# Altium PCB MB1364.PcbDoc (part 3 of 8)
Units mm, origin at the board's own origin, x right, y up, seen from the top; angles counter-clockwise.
Board outline 70 x 133.34 mm, 6 copper layers (Top Layer, Signal Layer 1, Signal Layer 2, Signal Layer 3, Signal Layer 4, Bottom Layer), stack 1.57 mm thick; 321 components, 287 nets, 1372 pads, 2051 vias.

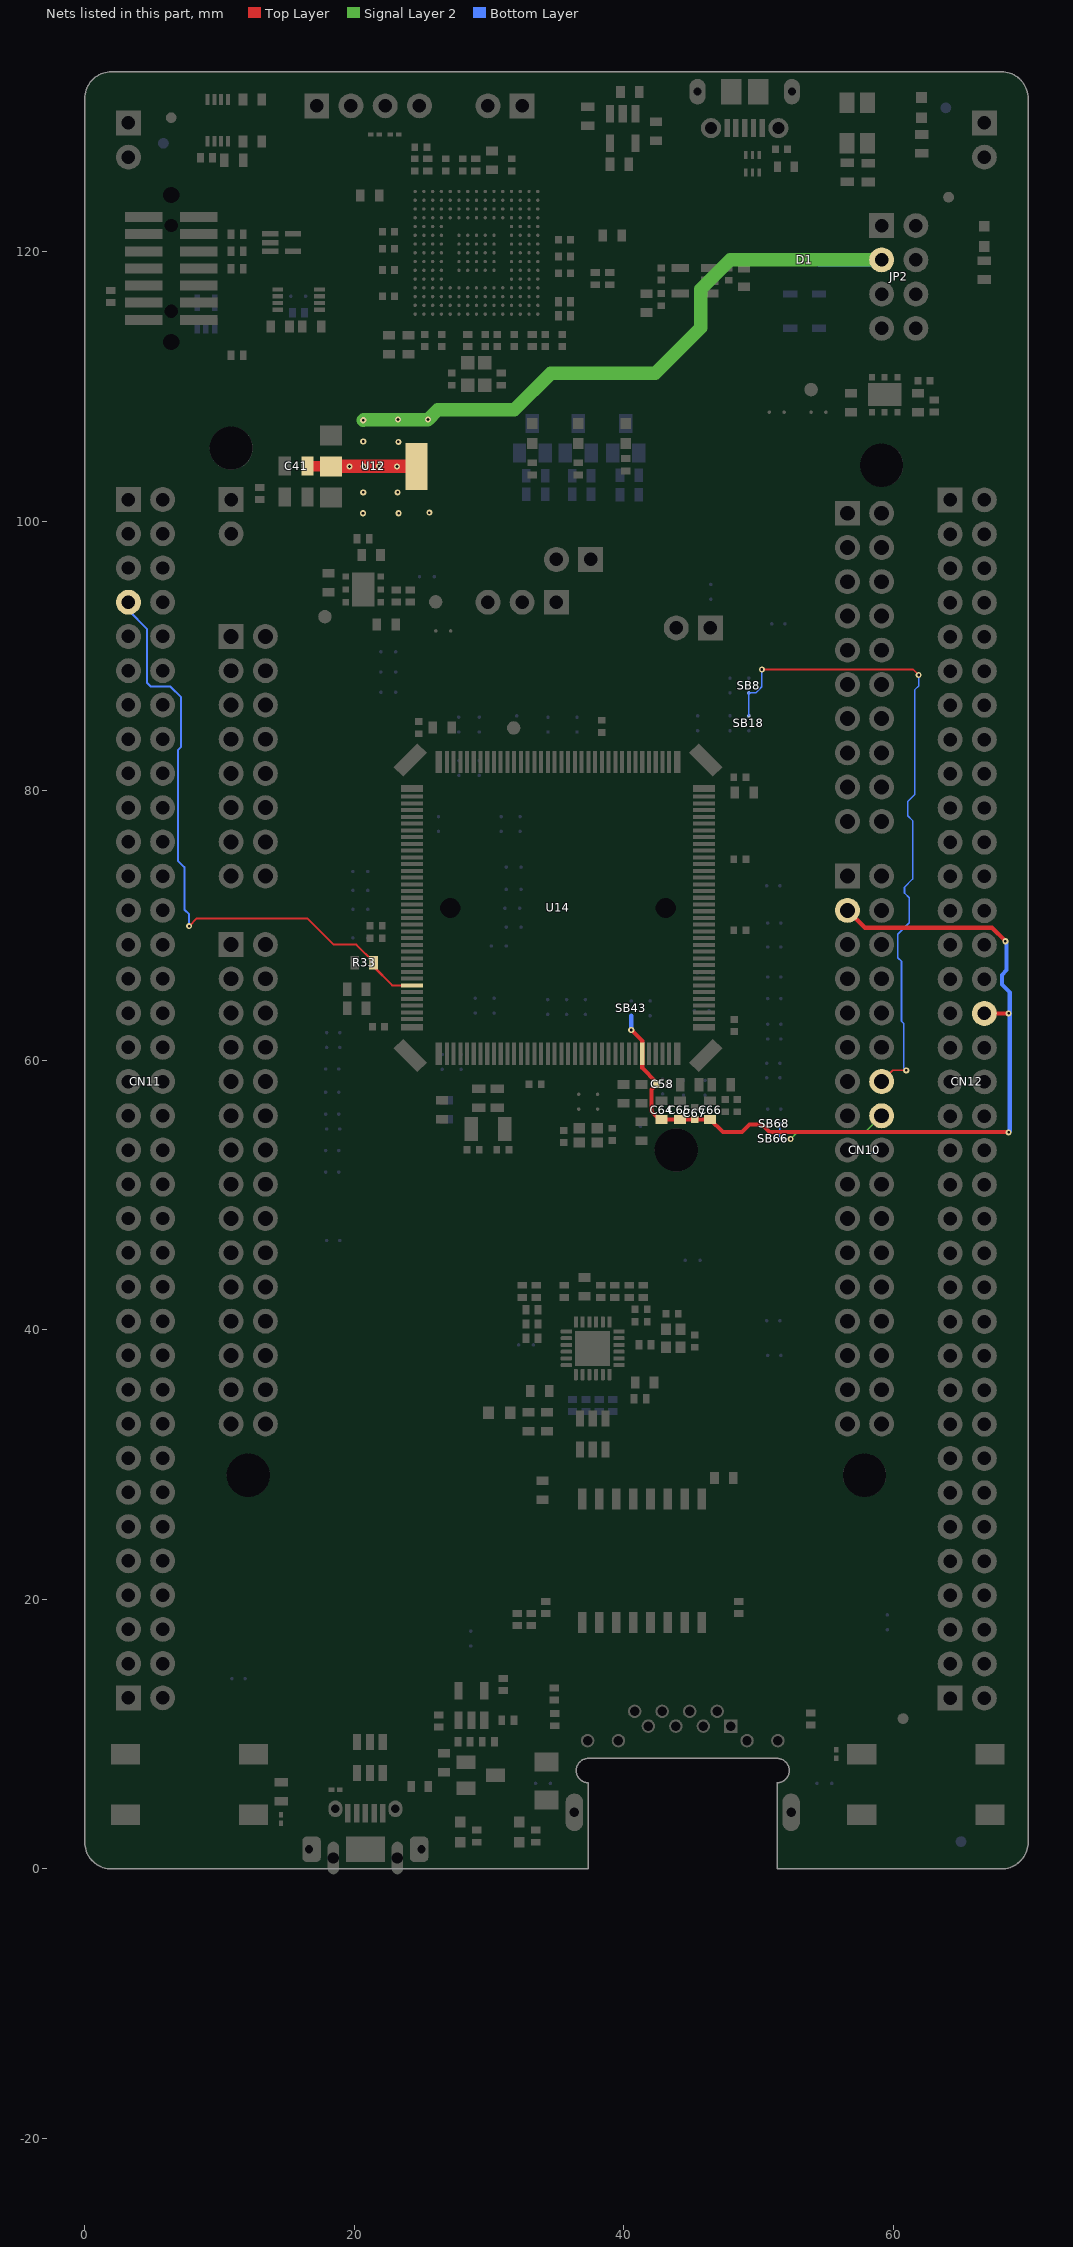
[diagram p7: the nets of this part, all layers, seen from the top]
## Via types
v1: diameter 0.45, hole 0.2, Top Layer to Bottom Layer, tented both sides, 1975 vias
v2: diameter 0.45, hole 0.2, Top Layer to Bottom Layer, tented top, 67 vias
v3: diameter 0.6, hole 0.3, Top Layer to Bottom Layer, tented both sides, 9 vias

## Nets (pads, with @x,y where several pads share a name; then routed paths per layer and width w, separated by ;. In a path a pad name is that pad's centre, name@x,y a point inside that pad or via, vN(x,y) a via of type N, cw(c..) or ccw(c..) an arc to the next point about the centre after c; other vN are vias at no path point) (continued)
5V_VIN: C41.2 D1.1 JP2.3 U12.2 U12.4 | length 57.8
  Top Layer w0.8: C41.2@16.541,104.074 U12.2@18.246,104.074
  Top Layer w1: U12.2@18.246,104.074 U12.2@18.266,104.054 v1(19.641,104.054) v1(20.691,104.054) v1(23.166,104.054) U12.4@24.616,104.054
  Signal Layer 2 w1: v1(20.666,107.479) 20.716,107.529 v1(23.241,107.529) v1(25.466,107.529) 26.191,108.254 31.866,108.254 34.591,110.979 42.341,110.979 45.716,114.354 45.716,117.204 47.891,119.379 JP2.3@59.126,119.379
  Bottom Layer w1: D1.1@54.481,119.379 JP2.3@59.126,119.379
  other v1: 20.641,100.579 23.291,100.579 25.566,100.629 20.666,102.129 23.216,102.129 21.841,104.079 23.266,105.879 20.666,105.904
AGND: C58.1 C64.2 C65.1 C66.2 C67.1 CN10.3 CN12.32 SB43.2 U14.31 | length 64.9
  Top Layer w0.3: v1(40.55,62.25) 41.366,61.434 U14.31@41.366,60.479 41.366,59.409 42.4,58.375 C58.1@42.4,58.225 42.4,58.175 42.05,57.825 42.05,56.2 42.65,55.6 C64.2@42.8,55.6 C65.1@44.15,55.6 C67.1@45.275,55.6 C66.2@46.4,55.6 47.341,54.659 48.421,54.659 48.76,54.659 49.327,55.225 50.25,55.225 50.816,54.659 55.716,54.659 68.541,54.659 v1(68.55,54.65) ; CN10.3@56.586,71.119 57.876,69.829 67.321,69.829 68.322,68.828 v1(68.303,68.828) ; CN12.32@66.746,63.474 68.555,63.474 68.556,63.475 v1(68.553,63.478)
  Bottom Layer w0.3: v1(40.55,62.25) SB43.2@40.55,63.3 ; v1(68.303,68.828) 68.391,68.741 68.391,66.68 68.04,66.329 68.04,65.616 68.631,65.025 68.631,63.556 v1(68.553,63.478) ; v1@68.549,63.474 v1(68.553,63.478) ; v1(68.55,54.65) 68.525,54.65 68.631,54.756 68.631,63.4 v1(68.553,63.478)
ARD_D0_RX: CN10.16 SB66.1 SB68.2 | length 9.4
  Signal Layer 2 w0.12: v1(52.375,54.15) 52.875,54.65 57.897,54.65 CN10.16@59.126,55.879
  Bottom Layer w0.12: SB68.2@51.65,55.275 51.575,55.2 SB66.1@51.575,54.175 52.35,54.175 v1(52.375,54.15)
ARD_D1_TX: CN10.14 SB8.1 SB18.2 | length 48.9
  Top Layer w0.12: v1(50.238,88.988) 61.462,88.988 v1(61.875,88.575) ; CN10.14@59.126,58.419 59.957,59.25 v1(60.95,59.25)
  Bottom Layer w0.12: SB18.2@49.275,85.55 SB8.1@49.275,87.25 49.776,87.25 50.238,87.712 v1(50.238,88.988) ; v1(60.95,59.25) 60.755,59.445 60.755,62.739 60.6,62.894 60.6,67.338 60.325,67.613 60.325,69.352 61.181,70.208 61.181,72.05 60.82,72.411 60.82,72.843 61.421,73.444 61.421,77.781 61.07,78.132 61.07,79.194 61.571,79.695 61.571,87.466 61.875,87.77 v1(61.875,88.575)
BOOT0: CN11.7 R33.1 U14.138 | length 46
  Top Layer w0.155: v1(7.75,69.95) 8.325,70.525 16.525,70.525 18.475,68.575 20.161,68.575 21.425,67.311 R33.1@21.425,67.225 21.425,66.95 22.821,65.554 U14.138@24.291,65.554
  Bottom Layer w0.155: CN11.7@3.246,93.979 3.246,93.376 4.616,92.006 4.616,88.023 4.911,87.728 6.353,87.728 7.156,86.926 7.156,83.252 6.909,83.005 6.909,74.813 7.395,74.326 7.395,71.179 7.75,70.825 v1(7.75,69.95)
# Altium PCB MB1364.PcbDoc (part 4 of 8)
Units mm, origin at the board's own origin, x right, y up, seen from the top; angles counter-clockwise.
Board outline 70 x 133.34 mm, 6 copper layers (Top Layer, Signal Layer 1, Signal Layer 2, Signal Layer 3, Signal Layer 4, Bottom Layer), stack 1.57 mm thick; 321 components, 287 nets, 1372 pads, 2051 vias.

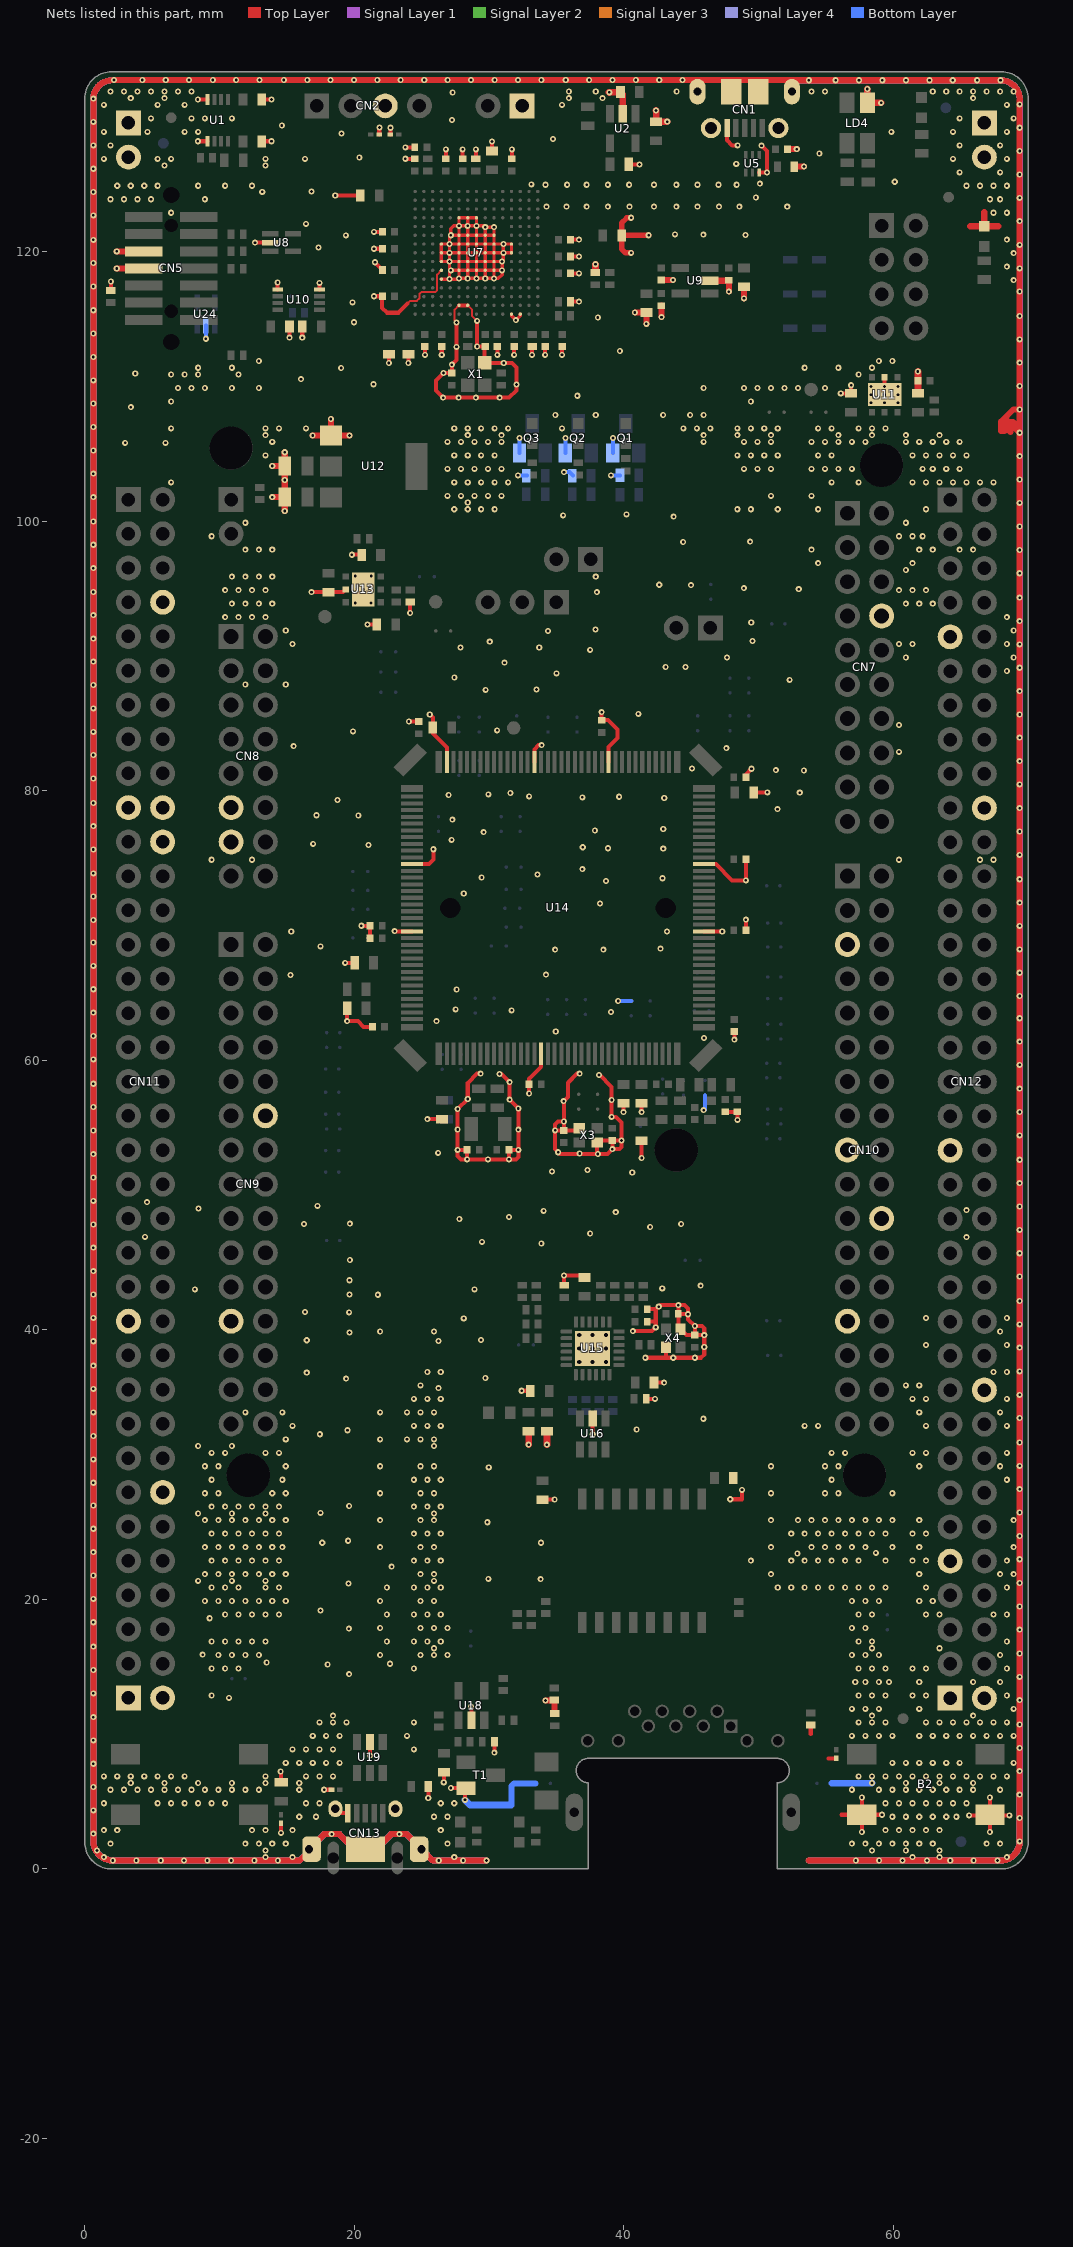
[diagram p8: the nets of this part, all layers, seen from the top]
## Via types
v1: diameter 0.45, hole 0.2, Top Layer to Bottom Layer, tented both sides, 1975 vias
v2: diameter 0.45, hole 0.2, Top Layer to Bottom Layer, tented top, 67 vias
v3: diameter 0.6, hole 0.3, Top Layer to Bottom Layer, tented both sides, 9 vias

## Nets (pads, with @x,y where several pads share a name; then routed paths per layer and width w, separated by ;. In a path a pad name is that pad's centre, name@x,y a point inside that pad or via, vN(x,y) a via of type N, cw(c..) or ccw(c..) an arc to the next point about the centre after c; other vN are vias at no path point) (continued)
GND: B2.3 B2.4 C1.1 C2.1 C3.1 C4.2 C5.1 C6.1 C7.1 C8.1 C9.1 C10.1 C11.1 C12.1 C13.1 C14.1 C15.1 C16.1 C17.1 C18.2 C19.1 C20.1 C21.1 C22.1 C23.1 C24.1 C25.1 C26.2 C27.1 C28.1 C29.1 C30.1 C31.1 C32.1 C33.1 C34.1 C35.1 C36.1 C37.1 C38.2 C39.1 C40.1 C41.1 C42.1 C43.1 C44.1 C45.1 C46.1 C47.1 C48.1 C49.1 C50.1 C51.1 C52.1 C53.1 C54.1 C55.1 C56.1 C57.1 C59.1 C60.1 C61.1 C62.2 C63.2 C68.1 C69.2 C70.2 C71.2 C72.2 C73.1 C74.1 C75.1 C76.1 C77.1 C78.1 C79.2 C80.1 C81.1 C82.1 C83.1 C84.1 CN1.5 CN1.6 CN1.7 CN1.8 CN1.9 CN1.10 CN1.11 CN2.3 CN3.1 CN3.2 CN4.1 CN4.2 CN5.5 CN5.7 CN7.8 CN8.11 CN8.13 CN9.12 CN9.23 CN10.5 CN10.17 CN10.22 CN10.27 CN11.8 CN11.19 CN11.20 CN11.22 CN11.49 CN11.60 CN12.9 CN12.20 CN12.39 CN12.54 CN12.63 CN13.5 CN13.6 CN13.7 CN13.8 CN13.9 CN13.10 CN15.1 CN15.2 CN16.1 CN16.2 JP1.1 LD4.1 LD5.2 Q1.2 Q2.2 Q3.2 R6.1 R7.2 R14.1 R17.1 R18.2 R22.1 R32.1 R33.2 R35.2 R42.2 R51.2 R57.1 R58.1 R59.1 R63.1 R64.1 R68.1 R69.1 R70.1 SB43.1 SB56.2 SB78.2 SB79.2 T1.2 U1.4 U1.5 U2.2 U3.2 U4.2 U5.3 U6.2 U7.D5 U7.D6 U7.D7 U7.D8 U7.D9 U7.F2 U7.F6 U7.F7 U7.F8 U7.F9 U7.F10 U7.F12 U7.G2 U7.G6 U7.G7 U7.G8 U7.G9 U7.G10 U7.G12 U7.H6 U7.H7 U7.H8 U7.H9 U7.H10 U7.H12 U7.J6 U7.J7 U7.J8 U7.J9 U7.J10 U7.K6 U7.K7 U7.K8 U7.K9 U7.K10 U7.M1 U7.M8 U7.M9 U7.N1 U8.2 U9.2 U10.4 U10.5 U11.2 U11.EP U12.1 U13.2 U13.EP U14.16 U14.51 U14.61 U14.83 U14.94 U14.107 U14.120 U14.130 U15.EP U16.2 U18.2 U19.2 U20.2 U21.2 U22.2 U23.2 U24.2 X1.2 X3.2 X3.4 X4.2 X4.4 | length 2601
  Top Layer w0.15: 23.966,116.154 24.146,116.334 24.649,116.334 24.841,116.526 24.841,116.854 24.971,116.984 25.996,116.984 26.146,117.134 26.146,118.284 U7.D6@26.466,118.604 ; v1(27.591,114.729) 27.441,114.879 27.441,115.679 U7.F2@27.766,116.004 ; U7.G2@28.416,116.004 28.741,115.679 28.741,115.204 29.091,114.854 v1(29.116,114.854)
  Top Layer w0.25: U7.D5@26.466,117.954 v1(27.066,117.954) ; U7.M1@31.666,115.354 31.666,115.229 v1(31.991,114.904) 32.316,115.229 U7.N1@32.316,115.354 ; U7.D8@26.466,119.904 v1(27.066,119.904) ; U7.D8@26.466,119.904 U7.D7@26.466,119.254 v1(27.066,119.254) ; U7.D8@26.466,119.904 U7.D9@26.466,120.554 v1(27.066,120.554) ; v1(27.066,117.954) 27.066,118.504 v1(27.166,118.604) ; v1(27.066,117.954) 27.716,117.954 v1(27.766,118.004) ; v1(27.066,119.254) U7.F7@27.766,119.254 ; v1(27.066,119.254) v1(27.066,119.904) ; v1(27.066,119.254) 27.066,118.704 v1(27.166,118.604) ; v1(27.066,119.904) U7.F8@27.766,119.904 ; v1(27.066,119.904) v1(27.066,120.554) ; v1(27.066,120.554) U7.F9@27.766,120.554 ; v1(27.066,120.554) 27.066,121.104 v1(27.166,121.204) ; v1(27.166,118.604) U7.F6@27.766,118.604 ; v1(27.166,121.204) U7.F10@27.766,121.204 ; v1(27.166,121.204) 27.166,121.679 27.391,121.904 v1(27.766,121.904) ; v1(27.766,118.004) U7.F6@27.766,118.604 ; v1(27.766,118.004) v1(28.416,118.004) ; U7.F6@27.766,118.604 U7.F7@27.766,119.254 ; U7.F6@27.766,118.604 U7.G6@28.416,118.604 ; U7.F7@27.766,119.254 U7.F8@27.766,119.904 ; U7.F7@27.766,119.254 U7.G7@28.416,119.254 ; U7.F8@27.766,119.904 U7.F9@27.766,120.554 ; U7.F8@27.766,119.904 U7.G8@28.416,119.904 ; U7.F9@27.766,120.554 U7.F10@27.766,121.204 ; U7.F9@27.766,120.554 U7.G9@28.416,120.554 ; U7.F10@27.766,121.204 U7.G10@28.416,121.204 ; U7.F10@27.766,121.204 v1(27.766,121.904) ; v1(27.766,121.904) U7.F12@27.766,122.504 U7.G12@28.416,122.504 ; v1(27.766,121.904) v1(28.416,121.904) ; v1(28.416,118.004) U7.G6@28.416,118.604 ; v1(28.416,118.004) v1(29.066,118.004) ; U7.G6@28.416,118.604 U7.H6@29.066,118.604 ; U7.G6@28.416,118.604 U7.G7@28.416,119.254 ; U7.G7@28.416,119.254 U7.H7@29.066,119.254 ; U7.G7@28.416,119.254 U7.G8@28.416,119.904 ; U7.G8@28.416,119.904 U7.H8@29.066,119.904 ; U7.G8@28.416,119.904 U7.G9@28.416,120.554 ; U7.G9@28.416,120.554 U7.H9@29.066,120.554 ; U7.G9@28.416,120.554 U7.G10@28.416,121.204 ; U7.G10@28.416,121.204 U7.H10@29.066,121.204 ; U7.G10@28.416,121.204 v1(28.416,121.904) ; v1(28.416,121.904) U7.G12@28.416,122.504 ; v1(28.416,121.904) v1(29.066,121.904) ; U7.G12@28.416,122.504 U7.H12@29.066,122.504 v1(29.066,121.904) ; v1(29.066,118.004) U7.H6@29.066,118.604 ; v1(29.066,118.004) v1(29.716,118.004) ; U7.H6@29.066,118.604 U7.J6@29.716,118.604 ; U7.H6@29.066,118.604 U7.H7@29.066,119.254 ; U7.H7@29.066,119.254 U7.J7@29.716,119.254 ; U7.H7@29.066,119.254 U7.H8@29.066,119.904 ; U7.H8@29.066,119.904 U7.J8@29.716,119.904 ; U7.H8@29.066,119.904 U7.H9@29.066,120.554 ; U7.H9@29.066,120.554 U7.J9@29.716,120.554 ; U7.H9@29.066,120.554 U7.H10@29.066,121.204 ; U7.H10@29.066,121.204 U7.J10@29.716,121.204 ; U7.H10@29.066,121.204 v1(29.066,121.904) ; v1(29.066,121.904) 29.616,121.904 v1(29.716,121.804) ; v1(29.716,118.004) U7.J6@29.716,118.604 ; v1(29.716,118.004) v1(30.366,118.004) ; U7.J6@29.716,118.604 U7.K6@30.366,118.604 ; U7.J6@29.716,118.604 U7.J7@29.716,119.254 ; U7.J7@29.716,119.254 U7.K7@30.366,119.254 ; U7.J7@29.716,119.254 U7.J8@29.716,119.904 ; U7.J8@29.716,119.904 U7.J9@29.716,120.554 ; U7.J8@29.716,119.904 U7.K8@30.366,119.904 ; U7.J9@29.716,120.554 U7.J10@29.716,121.204 ; U7.J9@29.716,120.554 U7.K9@30.366,120.554 ; U7.J10@29.716,121.204 v1(29.716,121.804) ; U7.J10@29.716,121.204 U7.K10@30.366,121.204 ; v1(29.716,121.804) v1(30.366,121.804) U7.K10@30.366,121.204 ; v1(30.366,118.004) U7.K6@30.366,118.604 ; v1(30.366,118.004) 30.691,118.004 30.966,118.279 v1(30.966,118.604) ; U7.K6@30.366,118.604 v1(30.966,118.604) ; U7.K6@30.366,118.604 U7.K7@30.366,119.254 ; U7.K7@30.366,119.254 v1(30.966,119.254) ; U7.K7@30.366,119.254 U7.K8@30.366,119.904 ; U7.K8@30.366,119.904 U7.K9@30.366,120.554 ; U7.K8@30.366,119.904 v1(31.066,119.904) ; U7.K9@30.366,120.554 U7.K10@30.366,121.204 ; U7.K9@30.366,120.554 v1(31.066,120.554) ; v1(30.966,118.604) v1(30.966,119.254) ; v1(30.966,119.254) 31.066,119.354 v1(31.066,119.904) ; v1(31.066,119.904) U7.M8@31.666,119.904 U7.M9@31.666,120.554 v1(31.066,120.554) ; v1(31.066,119.904) v1(31.066,120.554)
  Top Layer w0.3: R17.1@1.941,117.104 v1(1.941,117.779) ; v1(8.391,128.179) U1.5@9.116,128.179 ; v1(8.391,131.279) U1.4@9.116,131.279 ; v1(12.641,120.654) U8.2@13.766,120.654 ; C4.2@13.141,128.179 v1(13.866,128.179) ; C2.1@13.141,131.279 v1(13.866,131.279) ; U10.5@14.316,117.179 v1(14.316,117.704) ; v1(14.541,7.229) 14.566,7.204 R64.1@14.566,6.429 ; v1(14.566,2.679) U23.2@14.566,3.391 ; v1(15.191,113.604) C26.2@15.191,114.454 ; v1(16.141,113.604) C27.1@16.141,114.454 ; v1(16.825,94.725) C44.1@18.075,94.725 19.162,94.725 U13.2@19.366,94.929 ; U10.4@17.416,117.179 v1(17.416,117.679) ; v1(17.766,5.879) U22.2@18.304,5.879 ; v1(18.591,124.154) C12.1@20.441,124.154 ; CN13.6@18.598,4.464 18.923,4.139 CN13.5@19.523,4.139 ; v1(19.325,67.225) R33.2@20.025,67.225 ; R35.2@19.475,63.85 v1(19.475,62.9) 20.275,62.9 20.7,62.475 C56.1@21.35,62.475 ; v1(19.816,97.504) C43.1@20.566,97.504 ; v1(20.525,69.975) C52.1@21.175,69.975 C54.1@21.175,69.05 ; v1(20.975,92.325) C45.1@21.675,92.325 ; v1(21.166,8.404) U19.2@21.166,9.429 ; v1(21.466,116.679) C25.1@22.091,116.679 22.067,116.655 22.067,115.808 22.419,115.456 23.269,115.456 23.966,116.154 ; v1(21.466,120.204) C16.1@22.091,120.204 ; v1(21.466,121.454) C14.1@22.091,121.454 ; v1(21.541,119.204) 21.541,119.179 C21.1@22.091,118.629 ; U3.2@21.853,128.679 21.853,129.191 v1(21.866,129.204) ; v1(22.566,111.729) C35.1@22.566,112.379 ; U4.2@22.679,128.679 22.679,129.166 v1(22.691,129.179) ; v1(23,69.575) 23.021,69.554 U14.130@24.291,69.554 ; v1(23.791,126.879) C8.1@24.491,126.879 ; v1(23.791,127.729) C5.1@24.491,127.729 ; v1(24.016,111.729) C36.1@24.016,112.379 ; v1(24.05,85.125) C47.1@24.8,85.125 ; v1(24.15,93.175) R32.1@24.15,94 ; U14.120@24.291,74.554 25.529,74.554 25.866,74.891 v1(25.866,75.651) ; v1(25.241,112.329) C29.1@25.241,112.954 ; v1(25.425,55.625) C61.1@26.525,55.625 ; v1(25.491,5.264) U21.2@25.491,6.129 ; v1(25.6,85.65) 25.825,85.425 C48.1@25.825,84.675 25.825,84.24 26.866,83.199 U14.107@26.866,82.129 ; v1(26.491,112.329) C30.1@26.491,112.954 ; v1(26.641,6.429) C84.1@26.641,7.179 ; C9.1@26.791,126.879 v1(26.791,127.579) ; v1(27.166,6.004) T1.2@28.291,6.004 28.216,5.929 v1(28.216,5.129) ; v1(27.591,114.729) v1(27.591,112.929) 27.591,111.954 v1(27.241,111.604) C37.1@27.241,110.979 v1(26.616,110.979) 26.066,110.429 26.066,109.679 v1(26.591,109.154) v1(27.741,109.154) v1(29.016,109.154) v1(30.791,109.154) 31.491,109.154 32.041,109.704 v1(32.041,110.129) 32.036,110.134 32.036,111.384 31.691,111.729 v1(31.091,111.729) X1.2@29.666,111.729 29.666,112.904 C28.1@29.716,112.954 v1(29.116,112.954) v1(29.116,114.854) ; U7.F2@27.766,116.004 U7.G2@28.416,116.004 ; C10.1@28.041,126.879 v1(28.041,127.579) ; v1(28.666,12.054) 28.691,12.029 U18.2@28.691,11.024 ; R6.1@29.016,126.879 v1(29.016,127.579) ; v1(29.375,59) 29.1,59 28.42,58.32 v1(28.42,57.12) v1(27.675,56.375) v1(27.675,54.862) v1(27.675,53.35) ; C7.1@30.216,127.454 v1(30.216,128.154) ; v1(30.391,8.629) R63.1@30.391,9.454 ; v1(30.616,112.329) C31.1@30.616,112.954 ; v1(30.775,58.975) 30.925,58.975 v1(31.525,58.375) v1(31.525,57.075) v1(32.175,56.425) v1(32.175,54.85) v1(32.175,53.35) ; C11.1@31.691,126.879 v1(31.691,127.579) ; v1(31.866,112.329) C32.1@31.866,112.954 ; v1(32.416,35.479) C79.2@33.066,35.479 ; v1(32.975,57.525) C57.1@32.975,58.225 32.975,58.625 33.866,59.516 U14.16@33.866,60.479 ; v1(33.191,112.329) R22.1@33.191,112.954 ; U14.94@33.366,82.129 33.366,83.066 33.675,83.375 v1(33.9,83.375) ; C83.1@33.916,27.429 33.941,27.404 v1(34.866,27.404) ; v1(34.166,112.329) C33.1@34.166,112.954 ; v1(35.416,112.329) C34.1@35.416,112.954 ; v1(35.537,56.962) v1@35.55,56.975 ; R42.2@35.566,43.304 v1(35.566,44.029) 36.741,44.029 36.891,43.879 C73.1@37.091,43.879 ; R18.2@36.041,116.279 v1(36.666,116.279) ; C22.1@36.041,118.379 v1(36.666,118.379) ; C17.1@36.041,119.629 v1(36.666,119.629) ; C15.1@36.041,120.879 v1(36.666,120.879) ; X3.4@36.675,54.95 36.525,54.8 C70.2@35.55,54.8 ; v1(36.725,59) 36.521,59 35.85,58.329 35.85,57.275 v1@35.55,56.975 ; v1(37.691,32.229) U16.2@37.691,33.429 ; v1(38.15,58.9) 38.179,58.929 39.1,58.008 v1(39.1,57.05) v1(39.1,55.8) ; v1(38.35,85.825) C46.1@38.35,85.225 38.825,85.225 39.52,84.53 39.52,83.895 38.866,83.241 U14.83@38.866,82.129 ; v1@39.1,55.775 v1(39.1,55.8) ; v1(39.975,56.15) C59.1@39.975,56.8 ; R7.2@40.373,126.459 41.161,126.459 v1(41.166,126.454) ; v1(40.666,39.904) 42.091,39.904 v1(42.366,40.179) 42.366,40.629 ; v1(41.325,52.75) C68.1@41.325,54.025 ; v1(41.325,56.15) C60.1@41.325,56.8 ; v1(41.591,37.929) 43.141,37.929 ; R51.2@41.666,34.879 v1(42.316,34.879) ; C76.1@41.741,40.604 42.341,40.604 42.366,40.629 ; C74.1@41.741,41.529 42.366,41.529 ; C78.1@42.241,36.079 v1(42.991,36.079) ; X4.4@43.141,38.704 43.141,37.929 ; U14.51@45.941,69.554 47.296,69.554 v1(47.3,69.55) ; U14.61@45.941,74.554 46.821,74.554 48.025,73.35 v1(49.05,73.35) C51.1@49.05,74.925 ; C62.2@47.525,56.175 C63.2@48.425,56.175 v1(48.425,55.575) ; CN1.5@47.666,129.158 47.666,128.254 48.041,127.879 v1(48.441,127.879) ; v1(47.896,27.429) 48.766,27.429 v1(48.766,28.129) ; v1(48.2,61.525) C55.1@48.2,62.125 ; C53.1@49.05,69.65 49.05,70.426 v1(49.052,70.428) ; C49.1@49.05,81 49.05,81.2 v1(49.475,81.625) ; C50.1@49.625,79.875 v1(50.65,79.875) ; U5.3@50.041,125.854 v1(50.616,125.854) 50.616,127.454 v1(50.216,127.854) ; 53.866,10.004 R58.1@53.866,10.679 ; 55.185,8.21 U20.2@55.748,8.21 ; v1(56.091,109.479) C39.1@56.866,109.479 v1(56.866,110.079) ; 56.16,4.023 B2.3@57.653,4.023 ; v1(57.653,2.74) B2.3@57.653,4.023 ; v1(57.653,5.305) B2.3@57.653,4.023 ; v1(59.145,4.023) B2.3@57.653,4.023 ; v1(59.341,109.979) 59.348,109.986 U11.2@59.348,110.676 ; v1(65.616,3.979) B2.4@67.109,3.979 ; v1(67.153,2.74) B2.4@67.153,3.979 ; v1(67.153,5.305) B2.4@67.153,4.023 ; v1(68.602,3.979) B2.4@67.153,3.979 ; v1(27.675,53.35) 27.675,52.9 27.925,52.65 v1(28.375,52.65) ; v1(27.675,53.35) C71.2@28.375,53.35 v1(28.375,52.65) ; v1(28.375,52.65) v1(29.925,52.65) v1(31.475,52.65) ; v1(31.475,52.65) 32,52.65 32.175,52.825 v1(32.175,53.35) ; v1(31.475,52.65) C72.2@31.475,53.35 v1(32.175,53.35) ; v1(34.9,54.8) C70.2@35.55,54.8 ; v1(34.9,54.8) 34.9,55.225 35.125,55.45 v1(35.55,55.45) ; v1(34.9,54.8) 34.9,53.4 v1(35.125,53.175) 35.25,53.05 v1(38.075,53.05) ; C70.2@35.55,54.8 v1(35.55,55.45) ; v1(35.55,55.45) v1@35.55,56.975 ; v1(38.075,53.05) 38.8,53.05 v1(39.15,53.4) ; v1(38.075,53.05) 38.025,53.1 X3.2@38.025,53.9 38.175,54.05 C69.2@39.15,54.05 ; v1(39.1,55.8) 39.4,55.8 39.825,55.375 v1(39.825,54.05) ; v1(39.15,53.4) C69.2@39.15,54.05 ; v1(39.15,53.4) 39.675,53.4 39.825,53.55 v1(39.825,54.05) ; C69.2@39.15,54.05 v1(39.825,54.05) ; 42.366,40.629 42.366,41.529 ; 42.366,41.529 42.403,41.529 v1(42.591,41.716) 42.703,41.829 v1(44.041,41.829) ; 43.141,37.929 v1(43.666,37.929) v1(45.266,37.929) 45.741,37.929 45.966,38.154 v1(45.966,38.729) v1(45.966,39.604) ; C75.1@44.041,41.179 44.041,40.204 X4.2@44.191,40.054 44.641,39.604 C77.1@45.266,39.604 ; C75.1@44.041,41.179 44.741,41.179 v1(44.766,41.154) ; C75.1@44.041,41.179 v1(44.041,41.829) ; v1(44.041,41.829) 44.516,41.829 44.766,41.579 v1(44.766,41.154) ; v1(44.766,41.154) 44.766,40.779 v1(45.266,40.279) ; C77.1@45.266,39.604 v1(45.966,39.604) ; C77.1@45.266,39.604 v1(45.266,40.279) ; v1(45.266,40.279) 45.791,40.279 45.966,40.104 v1(45.966,39.604) ; B2.4@67.109,3.979 B2.4@67.153,3.979 ; B2.4@67.109,3.979 B2.4@67.153,4.023 ; B2.4@67.153,3.979 B2.4@67.153,4.023
  Top Layer w0.4: v1(40.541,119.904) 40.121,119.904 39.841,120.184 C13.1@39.841,121.204 ; v1(40.541,122.504) 40.229,122.504 39.841,122.116 C13.1@39.841,121.204 ; v1(41.841,121.204) C13.1@39.841,121.204
  Top Layer w0.45: v1(2.381,118.744) CN5.7@4.389,118.744 ; v1(2.381,120.014) CN5.5@4.389,120.014 ; v1@13.921,101.774 C42.1@14.841,101.774 ; v1@13.921,104.074 C41.1@14.841,104.074 ; v1(14.841,100.744) C42.1@14.841,101.774 ; v1(14.841,105.104) C41.1@14.841,104.074 ; v1(16.916,106.354) U12.1@18.266,106.354 ; v1(18.266,107.579) U12.1@18.266,106.354 ; v1(19.641,106.354) U12.1@18.266,106.354 ; v1@29.816,0.625 25.837,0.625 CN13.9@24.998,1.464 23.883,2.579 v1(23.341,2.579) 22.741,2.579 21.626,1.464 CN13.10@20.823,1.464 20.006,1.464 18.891,2.579 v1(18.327,2.579) 17.763,2.579 CN13.8@16.648,1.464 16.648,1.33 15.947,0.629 v1(14.329,0.629) v1(12.591,0.629) v1(10.866,0.629) v1(9.104,0.629) v1(7.366,0.629) v1(5.641,0.629) v1(3.829,0.629) v1(2.091,0.629) cw(c2.091,2.079) 0.641,2.079 v1(0.641,2.616) v1(0.641,4.354) v1(0.641,6.079) v1(0.641,7.804) v1(0.641,9.541) v1(0.641,11.266) v1(0.641,13.029) v1(0.641,14.766) v1(0.641,16.491) v1(0.641,18.304) v1(0.641,20.041) v1(0.641,21.766) v1(0.641,23.504) v1(0.641,25.241) v1(0.641,26.966) v1(0.641,28.654) v1(0.641,30.391) v1(0.641,32.116) v1(0.641,33.879) v1(0.641,35.616) v1(0.641,37.341) v1(0.641,39.154) v1(0.641,40.891) v1(0.641,42.616) v1(0.641,44.354) v1(0.641,46.091) v1(0.641,47.816) v1(0.641,49.566) v1(0.641,51.304) v1(0.641,53.029) v1(0.641,54.791) v1(0.641,56.529) v1(0.641,58.254) v1(0.641,60.066) v1(0.641,61.804) v1(0.641,63.529) v1(0.641,65.266) v1(0.641,67.004) v1(0.641,68.729) v1(0.641,70.404) v1(0.641,72.141) v1(0.641,73.866) v1(0.641,75.629) v1(0.641,77.366) v1(0.641,79.091) v1(0.641,80.904) v1(0.641,82.641) v1(0.641,84.366) v1(0.641,86.104) v1(0.641,87.841) v1(0.641,89.566) v1(0.641,91.279) v1(0.641,93.016) v1(0.641,94.741) v1(0.641,96.504) v1(0.641,98.241) v1(0.641,99.966) v1(0.641,101.779) v1(0.641,103.516) v1(0.641,105.241) v1(0.641,106.979) v1(0.641,108.716) v1(0.641,110.441) v1(0.641,112.179) v1(0.641,113.916) v1(0.641,115.641) v1(0.641,117.404) v1(0.641,119.141) v1(0.641,120.866) v1(0.641,122.679) v1(0.641,124.416) v1(0.641,126.141) v1(0.641,127.879) v1(0.641,129.616) 0.641,131.294 cw(c2.062,131.294) 2.062,132.715 CN1.8@45.441,132.715 ; v1(34.191,12.504) 34.822,12.504 R57.1@34.841,12.523 34.866,12.498 R59.1@34.866,11.529 ; v1(40.816,115.479) C23.1@41.666,115.479 v1(41.666,114.629) ; v1(42.791,115.129) C24.1@42.791,115.979 ; C19.1@42.791,117.879 v1(43.641,117.879) ; CN1.8@45.466,131.858 45.466,132.69 CN1.8@45.441,132.715 ; U9.2@46.391,117.829 47.752,117.829 C20.1@47.794,117.87 v1(47.794,117.02) ; v1(48.916,116.529) C18.2@48.916,117.379 ; C6.1@52.149,127.593 v1(52.83,127.593) ; U6.2@52.649,126.293 53.355,126.293 v1(53.366,126.304) ; 53.741,0.625 v1(57.216,0.625) v1(58.941,0.625) v1(60.678,0.625) v1(62.491,0.625) v1(64.216,0.625) v1(65.954,0.625) v1(67.716,0.625) 67.938,0.625 ccw(c67.938,2.053) v1(69.366,2.053) v1(69.366,3.778) v1(69.366,5.515) v1(69.366,7.253) v1(69.366,8.978) v1(69.366,10.715) v1(69.366,12.528) v1(69.366,14.253) v1(69.366,15.99) v1(69.366,17.753) v1(69.366,19.478) v1(69.366,21.215) v1(69.366,22.979) v1(69.366,24.704) v1(69.366,26.441) v1(69.366,28.179) v1(69.366,29.904) v1(69.366,31.641) v1(69.366,33.454) v1(69.366,35.179) v1(69.366,36.916) v1(69.366,38.679) v1(69.366,40.404) v1(69.366,42.141) v1(69.366,43.954) v1(69.366,45.679) v1(69.366,47.416) v1(69.366,49.154) v1(69.366,50.879) v1(69.366,52.616) v1(69.366,54.429) v1(69.366,56.154) v1(69.366,57.891) v1(69.366,59.654) v1(69.366,61.379) v1(69.366,63.116) v1(69.366,64.766) v1(69.366,66.491) v1(69.366,68.229) v1(69.366,69.966) v1(69.366,71.691) v1(69.366,73.429) v1(69.366,75.241) v1(69.366,76.966) v1(69.366,78.704) v1(69.366,80.466) v1(69.366,82.191) v1(69.366,83.929) v1(69.366,85.654) v1(69.366,87.379) v1(69.366,89.116) v1(69.366,90.854) v1(69.366,92.579) v1(69.366,94.316) v1(69.366,96.129) v1(69.366,97.854) v1(69.366,99.591) v1(69.366,101.354) v1(69.366,103.079) v1(69.366,104.816) v1(69.366,106.554) ; C42.1@14.841,101.774 v1(14.841,103.044) C41.1@14.841,104.074 ; CN1.8@45.441,132.715 52.341,132.715 52.352,132.704 v1(53.729,132.704) v1(55.712,132.704) v1(57.449,132.704) v1(59.174,132.704) v1(60.937,132.704) v1(62.674,132.704) v1(64.399,132.704) v1(66.212,132.704) v1(67.949,132.704) cw(c67.949,131.278) 69.375,131.278 69.366,131.269 v1(69.366,130.916) v1(69.366,129.179) v1(69.366,127.454) v1(69.366,125.716) v1(69.366,123.979) v1(69.366,122.254) v1(69.366,120.491) v1(69.366,118.754) v1(69.366,117.029) v1(69.366,115.216) v1(69.366,113.479) v1(69.366,111.754) v1(69.366,110.016) v1(69.366,108.279) ; 68.525,107.35 68.875,107.35 68.975,107.25 68.975,106.945 v1(69.366,106.554) ; 68.525,107.35 68.525,106.775 68.7,106.6 68.7,107.175 68.525,107.35 ; 68.525,107.35 68.4,107.475 68.225,107.475 68.225,106.675 68,106.675 68,107.375 68.904,108.279 v1(69.366,108.279) ; v1(69.366,106.554) v1(69.366,108.279)
  Top Layer w0.5: v1(32.941,31.479) C80.1@32.941,32.479 ; v1(34.291,31.479) C81.1@34.291,32.479 ; R14.1@37.891,118.429 v1(37.891,119.054) ; v1(38.923,131.804) 38.907,131.82 C1.1@39.748,131.82 39.916,131.652 U2.2@39.916,130.214 ; v1(42.391,130.454) 42.396,130.449 C3.1@42.396,129.627 43.218,129.627 v1(43.223,129.632) ; v1(58.066,132.054) LD4.1@58.066,131.029 v1(59.091,131.029) ; C40.1@61.816,109.479 C38.2@61.816,110.404 v1(61.816,111.104) ; 65.721,121.869 LD5.2@66.746,121.869 ; 66.746,122.894 LD5.2@66.746,121.869 ; 67.771,121.869 LD5.2@66.746,121.869
  Signal Layer 1 w0.45: v1@29.816,0.625 25.837,0.625 CN13.9@24.998,1.464 23.883,2.579 v1(23.341,2.579) 22.741,2.579 21.626,1.464 20.006,1.464 18.891,2.579 v1(18.327,2.579) 17.763,2.579 CN13.8@16.648,1.464 16.648,1.33 15.947,0.629 v1(14.329,0.629) v1(12.591,0.629) v1(10.866,0.629) v1(9.104,0.629) v1(7.366,0.629) v1(5.641,0.629) v1(3.829,0.629) v1(2.091,0.629) cw(c2.091,2.079) 0.641,2.079 v1(0.641,2.616) v1(0.641,4.354) v1(0.641,6.079) v1(0.641,7.804) v1(0.641,9.541) v1(0.641,11.266) v1(0.641,13.029) v1(0.641,14.766) v1(0.641,16.491) v1(0.641,18.304) v1(0.641,20.041) v1(0.641,21.766) v1(0.641,23.504) v1(0.641,25.241) v1(0.641,26.966) v1(0.641,28.654) v1(0.641,30.391) v1(0.641,32.116) v1(0.641,33.879) v1(0.641,35.616) v1(0.641,37.341) v1(0.641,39.154) v1(0.641,40.891) v1(0.641,42.616) v1(0.641,44.354) v1(0.641,46.091) v1(0.641,47.816) v1(0.641,49.566) v1(0.641,51.304) v1(0.641,53.029) v1(0.641,54.791) v1(0.641,56.529) v1(0.641,58.254) v1(0.641,60.066) v1(0.641,61.804) v1(0.641,63.529) v1(0.641,65.266) v1(0.641,67.004) v1(0.641,68.729) v1(0.641,70.404) v1(0.641,72.141) v1(0.641,73.866) v1(0.641,75.629) v1(0.641,77.366) v1(0.641,79.091) v1(0.641,80.904) v1(0.641,82.641) v1(0.641,84.366) v1(0.641,86.104) v1(0.641,87.841) v1(0.641,89.566) v1(0.641,91.279) v1(0.641,93.016) v1(0.641,94.741) v1(0.641,96.504) v1(0.641,98.241) v1(0.641,99.966) v1(0.641,101.779) v1(0.641,103.516) v1(0.641,105.241) v1(0.641,106.979) v1(0.641,108.716) v1(0.641,110.441) v1(0.641,112.179) v1(0.641,113.916) v1(0.641,115.641) v1(0.641,117.404) v1(0.641,119.141) v1(0.641,120.866) v1(0.641,122.679) v1(0.641,124.416) v1(0.641,126.141) v1(0.641,127.879) v1(0.641,129.616) 0.641,131.294 cw(c2.062,131.294) 2.062,132.715 CN1.8@45.441,132.715 ; CN1.8@45.466,131.858 45.466,132.69 CN1.8@45.441,132.715 ; 53.741,0.625 v1(57.216,0.625) v1(58.941,0.625) v1(60.678,0.625) v1(62.491,0.625) v1(64.216,0.625) v1(65.954,0.625) v1(67.716,0.625) 67.938,0.625 ccw(c67.938,2.053) v1(69.366,2.053) v1(69.366,3.778) v1(69.366,5.515) 69.366,5.552 69.375,5.561 69.375,131.278 ccw(c67.949,131.278) v1(67.949,132.704) v1(66.212,132.704) v1(64.399,132.704) v1(62.674,132.704) v1(60.937,132.704) v1(59.174,132.704) v1(57.449,132.704) v1(55.712,132.704) v1(53.729,132.704) 52.352,132.704 52.341,132.715 CN1.8@45.441,132.715
  Signal Layer 2 w0.3: v1@49.05,70.426 v1(49.052,70.428)
  Signal Layer 2 w0.45: v1@29.816,0.625 25.837,0.625 CN13.9@24.998,1.464 23.883,2.579 v1(23.341,2.579) 22.741,2.579 21.626,1.464 20.006,1.464 18.891,2.579 v1(18.327,2.579) 17.763,2.579 CN13.8@16.648,1.464 16.648,1.33 15.947,0.629 v1(14.329,0.629) v1(12.591,0.629) v1(10.866,0.629) v1(9.104,0.629) v1(7.366,0.629) v1(5.641,0.629) v1(3.829,0.629) v1(2.091,0.629) cw(c2.091,2.079) 0.641,2.079 v1(0.641,2.616) v1(0.641,4.354) v1(0.641,6.079) v1(0.641,7.804) v1(0.641,9.541) v1(0.641,11.266) v1(0.641,13.029) v1(0.641,14.766) v1(0.641,16.491) v1(0.641,18.304) v1(0.641,20.041) v1(0.641,21.766) v1(0.641,23.504) v1(0.641,25.241) v1(0.641,26.966) v1(0.641,28.654) v1(0.641,30.391) v1(0.641,32.116) v1(0.641,33.879) v1(0.641,35.616) v1(0.641,37.341) v1(0.641,39.154) v1(0.641,40.891) v1(0.641,42.616) v1(0.641,44.354) v1(0.641,46.091) v1(0.641,47.816) v1(0.641,49.566) v1(0.641,51.304) v1(0.641,53.029) v1(0.641,54.791) v1(0.641,56.529) v1(0.641,58.254) v1(0.641,60.066) v1(0.641,61.804) v1(0.641,63.529) v1(0.641,65.266) v1(0.641,67.004) v1(0.641,68.729) v1(0.641,70.404) v1(0.641,72.141) v1(0.641,73.866) v1(0.641,75.629) v1(0.641,77.366) v1(0.641,79.091) v1(0.641,80.904) v1(0.641,82.641) v1(0.641,84.366) v1(0.641,86.104) v1(0.641,87.841) v1(0.641,89.566) v1(0.641,91.279) v1(0.641,93.016) v1(0.641,94.741) v1(0.641,96.504) v1(0.641,98.241) v1(0.641,99.966) v1(0.641,101.779) v1(0.641,103.516) v1(0.641,105.241) v1(0.641,106.979) v1(0.641,108.716) v1(0.641,110.441) v1(0.641,112.179) v1(0.641,113.916) v1(0.641,115.641) v1(0.641,117.404) v1(0.641,119.141) v1(0.641,120.866) v1(0.641,122.679) v1(0.641,124.416) v1(0.641,126.141) v1(0.641,127.879) v1(0.641,129.616) 0.641,131.294 cw(c2.062,131.294) 2.062,132.715 CN1.8@45.441,132.715 ; CN1.8@45.466,131.858 45.466,132.69 CN1.8@45.441,132.715 ; 53.741,0.625 v1(57.216,0.625) v1(58.941,0.625) v1(60.678,0.625) v1(62.491,0.625) v1(64.216,0.625) v1(65.954,0.625) v1(67.716,0.625) 67.938,0.625 ccw(c67.938,2.053) v1(69.366,2.053) v1(69.366,3.778) v1(69.366,5.515) 69.366,5.552 69.375,5.561 69.375,131.278 ccw(c67.949,131.278) v1(67.949,132.704) v1(66.212,132.704) v1(64.399,132.704) v1(62.674,132.704) v1(60.937,132.704) v1(59.174,132.704) v1(57.449,132.704) v1(55.712,132.704) v1(53.729,132.704) 52.352,132.704 52.341,132.715 CN1.8@45.441,132.715
  Signal Layer 3 w0.45: v1@29.816,0.625 25.837,0.625 CN13.9@24.998,1.464 23.883,2.579 v1(23.341,2.579) 22.741,2.579 21.626,1.464 20.006,1.464 18.891,2.579 v1(18.327,2.579) 17.763,2.579 CN13.8@16.648,1.464 16.648,1.33 15.947,0.629 v1(14.329,0.629) v1(12.591,0.629) v1(10.866,0.629) v1(9.104,0.629) v1(7.366,0.629) v1(5.641,0.629) v1(3.829,0.629) v1(2.091,0.629) cw(c2.091,2.079) 0.641,2.079 v1(0.641,2.616) v1(0.641,4.354) v1(0.641,6.079) v1(0.641,7.804) v1(0.641,9.541) v1(0.641,11.266) v1(0.641,13.029) v1(0.641,14.766) v1(0.641,16.491) v1(0.641,18.304) v1(0.641,20.041) v1(0.641,21.766) v1(0.641,23.504) v1(0.641,25.241) v1(0.641,26.966) v1(0.641,28.654) v1(0.641,30.391) v1(0.641,32.116) v1(0.641,33.879) v1(0.641,35.616) v1(0.641,37.341) v1(0.641,39.154) v1(0.641,40.891) v1(0.641,42.616) v1(0.641,44.354) v1(0.641,46.091) v1(0.641,47.816) v1(0.641,49.566) v1(0.641,51.304) v1(0.641,53.029) v1(0.641,54.791) v1(0.641,56.529) v1(0.641,58.254) v1(0.641,60.066) v1(0.641,61.804) v1(0.641,63.529) v1(0.641,65.266) v1(0.641,67.004) v1(0.641,68.729) v1(0.641,70.404) v1(0.641,72.141) v1(0.641,73.866) v1(0.641,75.629) v1(0.641,77.366) v1(0.641,79.091) v1(0.641,80.904) v1(0.641,82.641) v1(0.641,84.366) v1(0.641,86.104) v1(0.641,87.841) v1(0.641,89.566) v1(0.641,91.279) v1(0.641,93.016) v1(0.641,94.741) v1(0.641,96.504) v1(0.641,98.241) v1(0.641,99.966) v1(0.641,101.779) v1(0.641,103.516) v1(0.641,105.241) v1(0.641,106.979) v1(0.641,108.716) v1(0.641,110.441) v1(0.641,112.179) v1(0.641,113.916) v1(0.641,115.641) v1(0.641,117.404) v1(0.641,119.141) v1(0.641,120.866) v1(0.641,122.679) v1(0.641,124.416) v1(0.641,126.141) v1(0.641,127.879) v1(0.641,129.616) 0.641,131.294 cw(c2.062,131.294) 2.062,132.715 CN1.8@45.441,132.715 ; CN1.8@45.466,131.858 45.466,132.69 CN1.8@45.441,132.715 ; 53.691,0.625 v1(57.216,0.625) v1(58.941,0.625) v1(60.678,0.625) v1(62.491,0.625) v1(64.216,0.625) v1(65.954,0.625) v1(67.716,0.625) 67.938,0.625 ccw(c67.938,2.053) v1(69.366,2.053) v1(69.366,3.778) v1(69.366,5.515) 69.366,5.552 69.375,5.561 69.375,131.278 ccw(c67.949,131.278) v1(67.949,132.704) v1(66.212,132.704) v1(64.399,132.704) v1(62.674,132.704) v1(60.937,132.704) v1(59.174,132.704) v1(57.449,132.704) v1(55.712,132.704) v1(53.729,132.704) 52.352,132.704 52.341,132.715 CN1.8@45.441,132.715
  Signal Layer 4 w0.45: v1@29.816,0.625 25.837,0.625 CN13.9@24.998,1.464 23.883,2.579 v1(23.341,2.579) 22.741,2.579 21.626,1.464 20.006,1.464 18.891,2.579 v1(18.327,2.579) 17.763,2.579 CN13.8@16.648,1.464 16.648,1.33 15.947,0.629 v1(14.329,0.629) v1(12.591,0.629) v1(10.866,0.629) v1(9.104,0.629) v1(7.366,0.629) v1(5.641,0.629) v1(3.829,0.629) v1(2.091,0.629) cw(c2.091,2.079) 0.641,2.079 v1(0.641,2.616) v1(0.641,4.354) v1(0.641,6.079) v1(0.641,7.804) v1(0.641,9.541) v1(0.641,11.266) v1(0.641,13.029) v1(0.641,14.766) v1(0.641,16.491) v1(0.641,18.304) v1(0.641,20.041) v1(0.641,21.766) v1(0.641,23.504) v1(0.641,25.241) v1(0.641,26.966) v1(0.641,28.654) v1(0.641,30.391) v1(0.641,32.116) v1(0.641,33.879) v1(0.641,35.616) v1(0.641,37.341) v1(0.641,39.154) v1(0.641,40.891) v1(0.641,42.616) v1(0.641,44.354) v1(0.641,46.091) v1(0.641,47.816) v1(0.641,49.566) v1(0.641,51.304) v1(0.641,53.029) v1(0.641,54.791) v1(0.641,56.529) v1(0.641,58.254) v1(0.641,60.066) v1(0.641,61.804) v1(0.641,63.529) v1(0.641,65.266) v1(0.641,67.004) v1(0.641,68.729) v1(0.641,70.404) v1(0.641,72.141) v1(0.641,73.866) v1(0.641,75.629) v1(0.641,77.366) v1(0.641,79.091) v1(0.641,80.904) v1(0.641,82.641) v1(0.641,84.366) v1(0.641,86.104) v1(0.641,87.841) v1(0.641,89.566) v1(0.641,91.279) v1(0.641,93.016) v1(0.641,94.741) v1(0.641,96.504) v1(0.641,98.241) v1(0.641,99.966) v1(0.641,101.779) v1(0.641,103.516) v1(0.641,105.241) v1(0.641,106.979) v1(0.641,108.716) v1(0.641,110.441) v1(0.641,112.179) v1(0.641,113.916) v1(0.641,115.641) v1(0.641,117.404) v1(0.641,119.141) v1(0.641,120.866) v1(0.641,122.679) v1(0.641,124.416) v1(0.641,126.141) v1(0.641,127.879) v1(0.641,129.616) 0.641,131.294 cw(c2.062,131.294) 2.062,132.715 CN1.8@45.441,132.715 ; CN1.8@45.466,131.858 45.466,132.69 CN1.8@45.441,132.715 ; v1(57.216,0.625) v1(58.941,0.625) v1(60.678,0.625) v1(62.491,0.625) v1(64.216,0.625) v1(65.954,0.625) v1(67.716,0.625) 67.938,0.625 ccw(c67.938,2.053) v1(69.366,2.053) v1(69.366,3.778) v1(69.366,5.515) 69.366,5.552 69.375,5.561 69.375,131.278 ccw(c67.949,131.278) v1(67.949,132.704) v1(66.212,132.704) v1(64.399,132.704) v1(62.674,132.704) v1(60.937,132.704) v1(59.174,132.704) v1(57.449,132.704) v1(55.712,132.704) v1(53.729,132.704) 52.352,132.704 52.341,132.715 CN1.8@45.441,132.715
  Bottom Layer w0.3: v1(8.991,113.529) U24.2@8.991,114.504 ; v1(32.15,103.392) 32.157,103.385 R70.1@32.811,103.385 ; Q3.2@32.258,105.047 v1(32.258,106.165) ; v1(35.566,103.629) 35.967,103.629 R69.1@36.211,103.385 ; Q2.2@35.666,105.047 v1(35.666,106.165) ; v1(39.05,103.392) 39.057,103.385 R68.1@39.711,103.385 ; Q1.2@39.191,105.047 v1(39.191,106.165) ; v1(39.575,64.4) SB43.1@40.55,64.4 ; v1(45.925,56.3) 46.025,56.3 SB56.2@46.025,57.4
  Bottom Layer w0.45: v1@29.816,0.625 25.837,0.625 CN13.9@24.998,1.464 23.883,2.579 v1(23.341,2.579) 22.741,2.579 21.626,1.464 20.006,1.464 18.891,2.579 v1(18.327,2.579) 17.763,2.579 CN13.8@16.648,1.464 16.648,1.33 15.947,0.629 v1(14.329,0.629) v1(12.591,0.629) v1(10.866,0.629) v1(9.104,0.629) v1(7.366,0.629) v1(5.641,0.629) v1(3.829,0.629) v1(2.091,0.629) cw(c2.091,2.079) 0.641,2.079 v1(0.641,2.616) v1(0.641,4.354) v1(0.641,6.079) v1(0.641,7.804) v1(0.641,9.541) v1(0.641,11.266) v1(0.641,13.029) v1(0.641,14.766) v1(0.641,16.491) v1(0.641,18.304) v1(0.641,20.041) v1(0.641,21.766) v1(0.641,23.504) v1(0.641,25.241) v1(0.641,26.966) v1(0.641,28.654) v1(0.641,30.391) v1(0.641,32.116) v1(0.641,33.879) v1(0.641,35.616) v1(0.641,37.341) v1(0.641,39.154) v1(0.641,40.891) v1(0.641,42.616) v1(0.641,44.354) v1(0.641,46.091) v1(0.641,47.816) v1(0.641,49.566) v1(0.641,51.304) v1(0.641,53.029) v1(0.641,54.791) v1(0.641,56.529) v1(0.641,58.254) v1(0.641,60.066) v1(0.641,61.804) v1(0.641,63.529) v1(0.641,65.266) v1(0.641,67.004) v1(0.641,68.729) v1(0.641,70.404) v1(0.641,72.141) v1(0.641,73.866) v1(0.641,75.629) v1(0.641,77.366) v1(0.641,79.091) v1(0.641,80.904) v1(0.641,82.641) v1(0.641,84.366) v1(0.641,86.104) v1(0.641,87.841) v1(0.641,89.566) v1(0.641,91.279) v1(0.641,93.016) v1(0.641,94.741) v1(0.641,96.504) v1(0.641,98.241) v1(0.641,99.966) v1(0.641,101.779) v1(0.641,103.516) v1(0.641,105.241) v1(0.641,106.979) v1(0.641,108.716) v1(0.641,110.441) v1(0.641,112.179) v1(0.641,113.916) v1(0.641,115.641) v1(0.641,117.404) v1(0.641,119.141) v1(0.641,120.866) v1(0.641,122.679) v1(0.641,124.416) v1(0.641,126.141) v1(0.641,127.879) v1(0.641,129.616) 0.641,131.294 cw(c2.062,131.294) 2.062,132.715 CN1.8@45.441,132.715 ; 31.65,4.75 31.65,6.15 31.85,6.35 SB79.2@33.45,6.35 ; CN1.8@45.466,131.858 45.466,132.69 CN1.8@45.441,132.715 ; v1(57.216,0.625) v1(58.941,0.625) v1(60.678,0.625) v1(62.491,0.625) v1(64.216,0.625) v1(65.954,0.625) v1(67.716,0.625) 67.938,0.625 ccw(c67.938,2.053) v1(69.366,2.053) v1(69.366,3.778) v1(69.366,5.515) 69.366,5.552 69.375,5.561 69.375,131.278 ccw(c67.949,131.278) v1(67.949,132.704) v1(66.212,132.704) v1(64.399,132.704) v1(62.674,132.704) v1(60.937,132.704) v1(59.174,132.704) v1(57.449,132.704) v1(55.712,132.704) v1(53.729,132.704) 52.352,132.704 52.341,132.715 CN1.8@45.441,132.715
  Bottom Layer w0.5: v1(28.216,5.129) 28.595,4.75 31.65,4.75 ; SB78.2@55.425,6.35 58.392,6.35 v2(58.417,6.375)
  other v1: 26.266,0.629 28.079,0.629 29.816,0.629 1.418,0.876 13.418,0.876 15.418,0.876 27.418,0.876 61.418,0.876 63.418,0.876 68.418,0.876 1.918,1.876 11.918,1.876 12.918,1.876 13.918,1.876 14.918,1.876 26.918,1.876 56.918,1.876 57.918,1.876 58.918,1.876 59.918,1.876 60.918,1.876 61.918,1.876 62.918,1.876 66.918,1.876 67.918,1.876 1.418,2.876 2.418,2.876 12.418,2.876 13.418,2.876 15.418,2.876 26.418,2.876 59.418,2.876 60.418,2.876 61.418,2.876 62.418,2.876 63.418,2.876 15.918,3.876 25.918,3.876 26.918,3.876 59.918,3.876 60.918,3.876 61.918,3.876 62.918,3.876 63.918,3.876 1.418,4.876 5.418,4.876 6.418,4.876 7.418,4.876 8.418,4.876 9.418,4.876 10.418,4.876 16.418,4.876 17.418,4.876 26.418,4.876 27.418,4.876 59.418,4.876 60.418,4.876 61.418,4.876 62.418,4.876 63.418,4.876 64.418,4.876 65.418,4.876 1.918,5.876 2.918,5.876 3.918,5.876 4.918,5.876 5.918,5.876 6.918,5.876 7.918,5.876 8.918,5.876 9.918,5.876 10.918,5.876 11.918,5.876 12.918,5.876 15.918,5.876 56.918,5.876 58.918,5.876 59.918,5.876 60.918,5.876 61.918,5.876 62.918,5.876 63.918,5.876 64.918,5.876 65.918,5.876 67.918,5.876 1.418,6.876 2.418,6.876 3.418,6.876 4.418,6.876 5.418,6.876 6.418,6.876 7.418,6.876 13.418,6.876 16.418,6.876 17.418,6.876 18.418,6.876 57.418,6.876 58.418,6.876 59.418,6.876 60.418,6.876 61.418,6.876 62.418,6.876 63.418,6.876 64.418,6.876 65.418,6.876 66.418,6.876 67.418,6.876 68.418,6.876 14.918,7.876 15.918,7.876 16.918,7.876 17.918,7.876 18.918,7.876 59.918,7.876 60.918,7.876 61.918,7.876 62.918,7.876 63.918,7.876 64.918,7.876 68.918,7.876 15.418,8.876 16.418,8.876 17.418,8.876 18.418,8.876 24.418,8.876 16.918,9.876 17.918,9.876 18.918,9.876 23.918,9.876 56.918,9.876 57.918,9.876 58.918,9.876 59.918,9.876 61.918,9.876 62.918,9.876 63.918,9.876 64.918,9.876 65.918,9.876 66.918,9.876 67.918,9.876 68.918,9.876 17.418,10.876 18.418,10.876 19.418,10.876 24.418,10.876 57.418,10.876 58.418,10.876 59.418,10.876 62.418,10.876 63.418,10.876 64.418,10.876 65.418,10.876 66.418,10.876 67.418,10.876 68.418,10.876 56.918,11.876 57.918,11.876 58.918,11.876 61.918,11.876 68.918,11.876 10.7,12.7 9.418,12.876 57.418,12.876 58.418,12.876 59.418,12.876 61.418,12.876 62.418,12.876 68.418,12.876 57.918,13.876 58.918,13.876 61.918,13.876 65.918,13.876 67.918,13.876 19.625,14.45 9.418,14.876 10.418,14.876 11.418,14.876 24.418,14.876 57.418,14.876 58.418,14.876 59.418,14.876 61.418,14.876 62.418,14.876 68.418,14.876 18.025,15.175 22.65,15.225 13.5,15.325 9.918,15.876 10.918,15.876 11.918,15.876 12.918,15.876 21.918,15.876 24.918,15.876 25.918,15.876 26.918,15.876 56.918,15.876 57.918,15.876 58.918,15.876 67.918,15.876 8.75,15.9 9.418,16.876 10.418,16.876 11.418,16.876 12.418,16.876 13.418,16.876 22.418,16.876 24.418,16.876 25.418,16.876 26.418,16.876 57.418,16.876 58.418,16.876 68.418,16.876 19.6,17.825 21.918,17.876 24.918,17.876 25.918,17.876 26.918,17.876 56.918,17.876 57.918,17.876 9.275,18.6 10.418,18.876 11.418,18.876 12.418,18.876 13.418,18.876 14.418,18.876 22.418,18.876 24.418,18.876 25.418,18.876 26.418,18.876 57.418,18.876 58.418,18.876 62.418,18.876 63.418,18.876 67.418,18.876 68.418,18.876 17.5,19.175 8.918,19.876 9.918,19.876 10.918,19.876 11.918,19.876 12.918,19.876 13.918,19.876 14.918,19.876 21.918,19.876 24.918,19.876 25.918,19.876 56.918,19.876 57.918,19.876 58.918,19.876 61.918,19.876 62.918,19.876 9.418,20.876 10.418,20.876 11.418,20.876 13.418,20.876 14.418,20.876 22.418,20.876 24.418,20.876 25.418,20.876 26.418,20.876 51.418,20.876 52.418,20.876 53.418,20.876 54.418,20.876 55.418,20.876 56.418,20.876 57.418,20.876 58.418,20.876 59.418,20.876 62.418,20.876 68.418,20.876 19.575,21.175 33.825,21.5 29.95,21.525 8.918,21.876 9.918,21.876 10.918,21.876 11.918,21.876 12.918,21.876 13.918,21.876 14.918,21.876 24.918,21.876 25.918,21.876 50.918,21.876 61.918,21.876 67.918,21.876 68.918,21.876 22.775,22.425 9.418,22.876 10.418,22.876 11.418,22.876 12.418,22.876 13.418,22.876 14.418,22.876 24.418,22.876 25.418,22.876 26.418,22.876 49.418,22.876 52.418,22.876 53.418,22.876 54.418,22.876 55.418,22.876 56.418,22.876 57.418,22.876 59.418,22.876 61.418,22.876 62.418,22.876 68.418,22.876 52.875,23.4 58.7,23.45 8.918,23.876 9.918,23.876 10.918,23.876 11.918,23.876 12.918,23.876 13.918,23.876 21.918,23.876 24.918,23.876 25.918,23.876 50.918,23.876 53.918,23.876 54.918,23.876 55.918,23.876 56.918,23.876 57.918,23.876 59.918,23.876 61.918,23.876 68.918,23.876 17.625,24.2 33.85,24.2 19.55,24.35 9.418,24.876 10.418,24.876 11.418,24.876 12.418,24.876 13.418,24.876 14.418,24.876 24.418,24.876 25.418,24.876 26.418,24.876 52.418,24.876 53.418,24.876 54.418,24.876 55.418,24.876 56.418,24.876 57.418,24.876 58.418,24.876 59.418,24.876 61.418,24.876 62.418,24.876 29.875,25.725 8.918,25.876 9.918,25.876 10.918,25.876 11.918,25.876 12.918,25.876 13.918,25.876 14.918,25.876 21.918,25.876 24.918,25.876 25.918,25.876 50.918,25.876 52.918,25.876 53.918,25.876 54.918,25.876 55.918,25.876 56.918,25.876 57.918,25.876 58.918,25.876 59.918,25.876 61.918,25.876 68.918,25.876 17.5,26.425 9.418,26.876 10.418,26.876 11.418,26.876 12.418,26.876 13.418,26.876 14.418,26.876 24.418,26.876 25.418,26.876 26.418,26.876 19.625,26.925 8.918,27.876 9.918,27.876 13.918,27.876 14.918,27.876 21.918,27.876 24.918,27.876 25.918,27.876 50.918,27.876 54.918,27.876 55.918,27.876 59.918,27.876 9.418,28.876 24.418,28.876 25.418,28.876 26.418,28.876 55.418,28.876 68.418,28.876 29.975,29.8 8.918,29.876 9.918,29.876 14.918,29.876 21.918,29.876 24.918,29.876 25.918,29.876 50.918,29.876 54.918,29.876 55.918,29.876 61.918,29.876 67.918,29.876 9.418,30.876 10.418,30.876 13.418,30.876 14.418,30.876 55.418,30.876 56.418,30.876 61.418,30.876 62.418,30.876 68.418,30.876 14.918,31.876 21.918,31.876 23.918,31.876 24.918,31.876 25.918,31.876 17.45,32.25 19.5,32.55 40.95,32.6 15.418,32.876 24.418,32.876 25.418,32.876 26.418,32.876 53.418,32.876 54.418,32.876 62.418,32.876 68.418,32.876 45.9,33.4 11.918,33.876 21.918,33.876 23.918,33.876 24.918,33.876 25.918,33.876 61.918,33.876 67.918,33.876 24.418,34.876 25.418,34.876 26.418,34.876 61.418,34.876 62.418,34.876 68.418,34.876 26.25,35.675 24.918,35.876 60.918,35.876 61.918,35.876 19.4,36.375 29.725,36.425 16.475,36.825 25.418,36.876 26.418,36.876 67.418,36.876 68.418,36.876 62.418,38.876 68.418,38.876 26.25,39.175 16.475,39.225 29.4,39.25 19.65,39.8 21.918,39.876 25.918,39.876 67.918,39.876 28.125,40.85 62.418,40.876 68.418,40.876 19.625,41.3 16.35,41.325 21.75,42.6 19.65,42.625 8.175,43 28.925,43 42.85,43.075 45.7,43.275 19.65,43.675 19.675,45.175 33.875,46.4 29.475,46.525 65.418,46.876 4.475,46.9 37.5,47.15 41.95,47.625 16.275,47.85 44.25,47.85 19.675,47.875 27.8,48.225 31.475,48.375 39.4,48.725 34.05,48.825 65.418,48.876 8.45,49 17.275,49.2 4.625,49.475 40.625,51.675 34.675,51.75 37.3,51.85 36.725,53.075 26.225,53.125 45.95,61.65 34.95,62.125 26.1,62.9 39.05,63.575 31.675,63.7 27.525,63.775 27.6,65.25 15.275,66.325 34.225,66.35 34.9,68.2 38.475,68.2 42.725,68.275 17.5,68.45 15.325,69.55 43.2,69.55 38.225,71.625 28.125,72.375 38.675,73.3 42.875,73.5 29.45,73.55 33.6,73.775 36.925,74.175 9.418,74.876 12.418,74.876 60.418,74.876 66.418,74.876 67.418,74.876 38.825,75.725 42.925,75.7 36.95,75.8 21.05,75.975 16.95,76.05 27.225,76.35 29.6,76.925 37.85,77.05 42.925,77.15 27.275,77.85 20.3,78.15 17.2,78.175 51.4,78.625 18.75,79.3 43,79.45 36.925,79.5 39.65,79.55 32.975,79.575 27,79.675 29.95,79.725 31.575,79.825 53.05,79.85 53.35,81.5 51.275,81.525 45.05,81.65 60.418,82.876 47.6,83.15 15.5,83.3 19.9,84.4 30.6,84.475 60.418,84.876 41.075,85.7 29.75,87.475 33.525,87.5 11.918,87.876 14.918,87.876 52.3,88.225 27.425,88.4 35,88.7 68.418,88.876 43.1,89.175 44.575,89.175 31.15,89.5 47.65,89.875 60.918,89.876 68.918,89.876 37.5,90.45 27.875,90.625 33.725,90.625 15.418,90.876 60.418,90.876 61.418,90.876 68.418,90.876 30.05,91.05 49.55,91.1 34.375,91.85 14.918,91.876 68.918,91.876 37.9,91.95 49.45,92.475 10.418,92.876 11.418,92.876 12.418,92.876 13.418,92.876 68.418,92.876 10.918,93.876 11.918,93.876 12.918,93.876 13.918,93.876 60.918,93.876 61.918,93.876 62.918,93.876 20.066,93.929 21.241,93.929 38,94.725 10.418,94.876 11.418,94.876 12.418,94.876 13.418,94.876 60.418,94.876 61.418,94.876 62.418,94.876 20.666,94.929 52.975,94.95 48.9,95.025 44.975,95.25 42.625,95.275 10.918,95.876 11.918,95.876 12.918,95.876 13.918,95.876 37.918,95.876 20.066,95.929 21.266,95.929 54.418,96.876 61.418,96.876 11.918,97.876 12.918,97.876 13.918,97.876 53.918,97.876 61.918,97.876 62.918,97.876 64.918,97.876 65.918,97.876 44.4,98.45 49.375,98.475 9.418,98.876 60.418,98.876 61.418,98.876 11.918,99.876 60.918,99.876 43.7,100.325 35.5,100.425 40.2,100.5 27.418,100.876 28.418,100.876 29.418,100.876 30.418,100.876 48.418,100.876 49.418,100.876 51.418,100.876 54.418,100.876 62.418,100.876 13.916,101.779 26.918,101.876 27.918,101.876 28.918,101.876 29.918,101.876 30.918,101.876 50.918,101.876 53.918,101.876 6.418,102.876 27.418,102.876 28.418,102.876 29.418,102.876 30.418,102.876 31.418,102.876 55.418,102.876 57.418,102.876 61.418,102.876 62.418,102.876 63.418,102.876 64.418,102.876 65.418,102.876 66.418,102.876 67.418,102.876 26.918,103.876 27.918,103.876 28.918,103.876 29.918,103.876 30.918,103.876 48.918,103.876 49.918,103.876 50.918,103.876 53.918,103.876 54.918,103.876 55.918,103.876 56.918,103.876 62.918,103.876 63.918,103.876 64.918,103.876 13.916,104.079 13.418,104.876 27.418,104.876 28.418,104.876 29.418,104.876 30.418,104.876 48.418,104.876 49.418,104.876 50.418,104.876 51.418,104.876 54.418,104.876 55.418,104.876 61.418,104.876 62.418,104.876 63.418,104.876 64.418,104.876 65.418,104.876 3,105.8 6,105.8 13.918,105.876 26.918,105.876 27.918,105.876 28.918,105.876 29.918,105.876 30.918,105.876 45.918,105.876 48.918,105.876 49.918,105.876 50.918,105.876 53.918,105.876 54.918,105.876 55.918,105.876 56.918,105.876 57.918,105.876 60.918,105.876 61.918,105.876 62.918,105.876 63.918,105.876 64.918,105.876 6.418,106.876 13.418,106.876 14.418,106.876 16.418,106.876 27.418,106.876 28.418,106.876 29.418,106.876 30.418,106.876 31.418,106.876 35.418,106.876 44.418,106.876 45.418,106.876 46.418,106.876 48.418,106.876 49.418,106.876 50.418,106.876 51.418,106.876 54.418,106.876 55.418,106.876 57.418,106.876 58.418,106.876 59.418,106.876 34.918,107.876 37.918,107.876 42.918,107.876 44.918,107.876 45.918,107.876 3.425,108.45 58.341,108.779 59.341,108.779 60.341,108.779 6.418,108.876 49.418,108.876 36.55,109.3 58.341,109.379 59.348,109.376 60.341,109.379 6.918,109.876 7.918,109.876 8.918,109.876 10.918,109.876 12.918,109.876 45.918,109.876 48.918,109.876 49.918,109.876 50.918,109.876 51.918,109.876 52.918,109.876 54.918,109.876 58.341,109.979 60.341,109.979 21.425,110.15 16.05,110.525 6.418,110.876 7.418,110.876 8.418,110.876 11.418,110.876 57.418,110.876 3.75,110.95 19.025,111.35 12.918,111.876 58.918,111.876 59.918,111.876 39.7,112.625 19.975,114.75 38.075,115.1 19.875,116.225 68.918,117.876 68.418,118.876 68.918,119.876 17.35,120.3 68.418,120.876 19.375,121.2 49.025,121.225 45.9,121.25 43.8,121.275 16.425,122.05 6.418,122.876 67.418,122.876 68.418,122.876 34.266,123.329 35.741,123.329 37.241,123.329 38.816,123.329 40.416,123.329 42.241,123.329 43.891,123.329 45.466,123.329 47.066,123.329 48.566,123.329 52.125,123.325 1.918,123.876 2.918,123.876 3.918,123.876 4.918,123.876 8.918,123.876 67.918,123.876 49.791,124.004 13.175,124.425 16.825,124.45 2.418,124.876 3.418,124.876 4.418,124.876 5.418,124.876 8.418,124.876 10.418,124.876 12.418,124.876 65.418,124.876 66.418,124.876 67.418,124.876 68.418,124.876 34.191,124.954 35.791,124.954 37.241,124.954 38.816,124.954 40.391,124.954 42.241,124.954 43.891,124.954 45.466,124.954 47.016,124.954 48.366,124.954 33.141,124.979 50.091,125.029 60.1,125.175 64.918,125.876 67.918,125.876 48.341,126.504 1.418,126.876 5.418,126.876 6.418,126.876 13.418,126.876 16.35,126.875 64.418,126.876 68.418,126.876 20.375,126.975 54.5,127.275 1.918,127.876 64.918,127.876 67.918,127.876 34.75,128.35 19.05,128.75 1.418,128.876 7.418,128.876 8.418,128.876 59.85,128.875 64.418,128.876 68.418,128.876 14.625,129.35 27.25,129.75 4.918,129.876 7.918,129.876 8.918,129.876 10.918,129.876 64.918,129.876 68.918,129.876 1.418,130.876 5.418,130.876 7.418,130.876 35.418,130.876 68.418,130.876 0.641,131.341 27.3,131.8 1.918,131.876 2.918,131.876 3.918,131.876 4.918,131.876 5.918,131.876 6.918,131.876 7.918,131.876 35.918,131.876 37.918,131.876 43.918,131.876 53.918,131.876 54.918,131.876 62.918,131.876 63.918,131.876 64.918,131.876 65.918,131.876 66.918,131.876 67.918,131.876 68.918,131.876 2.178,132.716 4.279,132.716 6.016,132.716 7.741,132.716 9.503,132.716 11.241,132.716 12.966,132.716 14.778,132.716 16.516,132.716 18.241,132.716 19.978,132.716 21.716,132.716 23.441,132.716 25.191,132.716 26.929,132.716 28.654,132.716 30.416,132.716 32.153,132.716 33.878,132.716 35.691,132.716 37.429,132.716 39.154,132.716 40.891,132.716 42.628,132.716 44.354,132.716
  other v2: 0.917,1.375 13.417,1.375 58.417,1.375 60.917,1.375 63.417,1.375 17.167,3.875 64.667,3.875 3.417,6.375 5.917,6.375 8.417,6.375 10.917,6.375 13.417,6.375 15.917,6.375 60.917,6.375 63.417,6.375 65.917,6.375 18.417,11.375 58.417,11.375 65.917,11.375 57.167,13.875 59.667,13.875 25.917,16.375 58.417,16.375 63.417,16.375 8.417,21.375 10.917,21.375 13.417,21.375 25.917,21.375 14.667,23.875 8.417,26.375 10.917,26.375 13.417,26.375 25.917,26.375 14.667,28.875 8.417,31.375 10.917,31.375 25.917,31.375 14.667,33.875 60.917,96.376 62.167,98.876 28.417,101.376 62.167,103.876 13.417,106.376 28.417,106.376 30.917,106.376 45.917,106.376 48.417,106.376 50.917,106.376 55.917,106.376 58.417,106.376 60.917,106.376 63.417,106.376 8.417,111.376 10.917,111.376 53.417,111.376 55.917,111.376 58.417,111.376 67.167,123.876 5.917,126.376 13.417,126.376 4.667,128.876 3.417,131.376 5.917,131.376 35.917,131.376 38.417,131.376 65.917,131.376
  other v3: 36.691,37.629 37.691,37.629 38.691,37.629 36.691,38.629 37.691,38.629 38.691,38.629 36.691,39.629 37.691,39.629 38.691,39.629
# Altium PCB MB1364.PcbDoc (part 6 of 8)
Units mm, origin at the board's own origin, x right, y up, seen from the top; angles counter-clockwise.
Board outline 70 x 133.34 mm, 6 copper layers (Top Layer, Signal Layer 1, Signal Layer 2, Signal Layer 3, Signal Layer 4, Bottom Layer), stack 1.57 mm thick; 321 components, 287 nets, 1372 pads, 2051 vias.

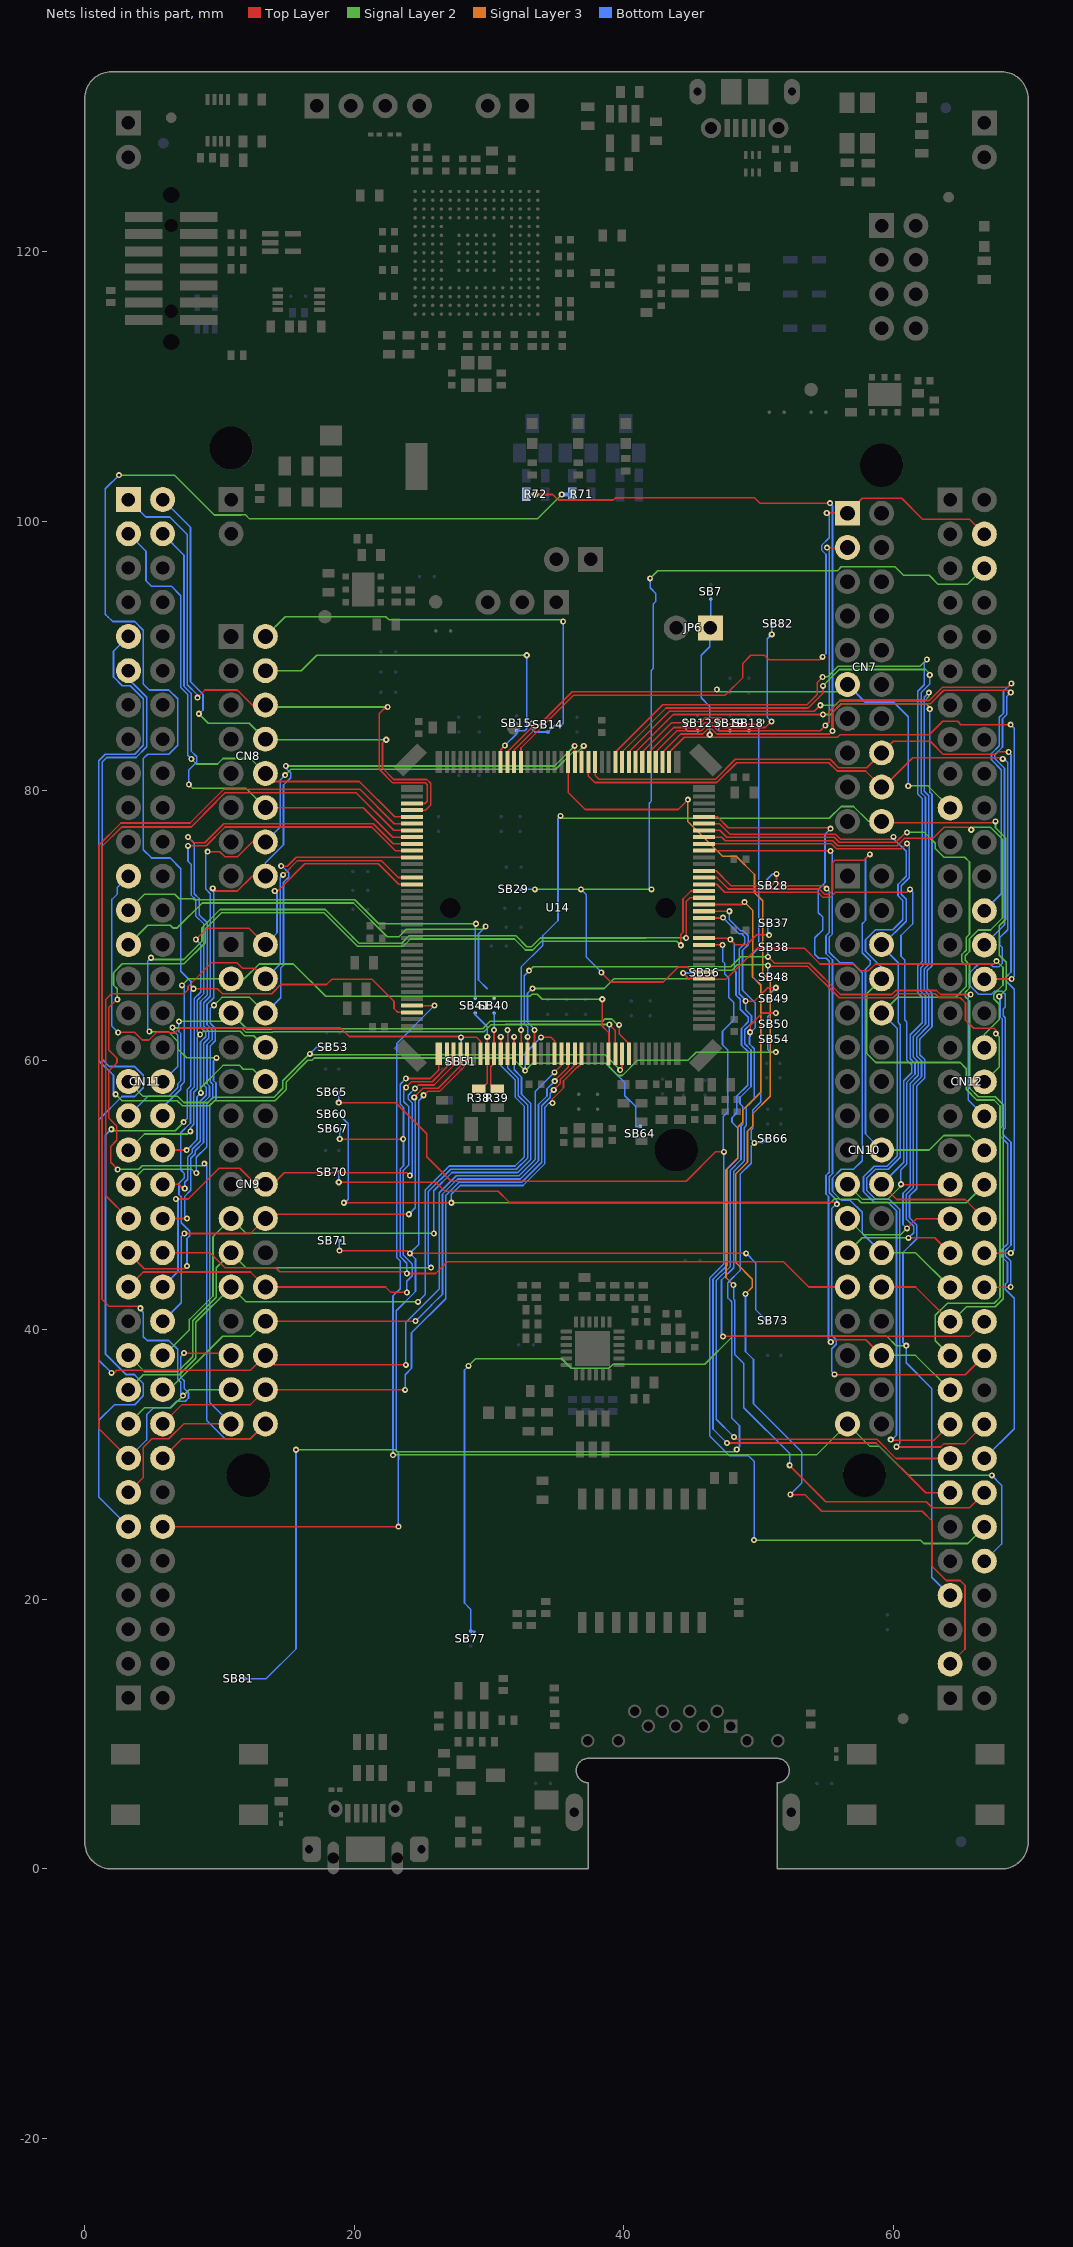
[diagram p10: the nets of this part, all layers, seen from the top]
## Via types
v1: diameter 0.45, hole 0.2, Top Layer to Bottom Layer, tented both sides, 1975 vias
v2: diameter 0.45, hole 0.2, Top Layer to Bottom Layer, tented top, 67 vias
v3: diameter 0.6, hole 0.3, Top Layer to Bottom Layer, tented both sides, 9 vias

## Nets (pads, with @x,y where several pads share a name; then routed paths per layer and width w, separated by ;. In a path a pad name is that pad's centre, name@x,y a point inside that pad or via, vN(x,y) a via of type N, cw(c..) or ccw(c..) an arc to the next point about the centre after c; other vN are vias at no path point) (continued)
PB13: CN12.30 JP6.1 SB7.1 U14.74 | length 59
  Top Layer w0.12: U14.74@43.366,82.129 43.366,82.858 44.473,83.965 46.2,83.965 46.375,84.14 v1(46.375,84.15) 46.56,83.965 55.846,83.965 56.029,84.148 62.658,84.148 63.649,85.139 64.763,85.139 65.003,84.899 v1(68.7,84.9) v1(68.7,84.9) ; CN12.30@66.746,66.014 66.757,66.025 v1(68.775,66.025)
  Bottom Layer w0.12: v1(46.375,84.15) 46.375,86.25 45.741,86.884 45.741,90.041 46.375,90.675 46.375,92.023 JP6.1@46.426,92.074 46.45,92.098 SB7.1@46.45,94.2 ; v1(68.7,84.9) 68.961,84.639 68.961,66.211 v1(68.775,66.025)
PB14: CN12.28 R72.1 U14.75 | length 90
  Top Layer w0.12: v1(33.427,101.98) 33.432,101.975 34.725,101.975 35.138,101.562 39.226,101.562 39.399,101.735 49.69,101.735 50.1,101.325 v1(55.3,101.325) ; U14.75@42.866,82.129 42.866,82.858 44.213,84.205 45.857,84.205 46.207,84.555 46.543,84.555 46.893,84.205 55.255,84.205 v1(55.481,84.431) 55.481,85.801 56.128,86.448 62.748,86.448 63.739,87.439 68.686,87.439 68.85,87.275 68.708,87.275 v1(68.703,87.279)
  Bottom Layer w0.12: R72.1@32.766,101.979 33.426,101.979 v1(33.427,101.98) ; v1(55.3,101.325) 55.3,101.35 55.481,101.169 v1(55.481,84.431) ; CN12.28@66.746,68.554 68.241,70.049 68.241,81.661 67.515,82.387 67.515,82.661 68.091,83.237 68.091,85.337 68.405,85.651 68.405,86.981 v1(68.703,87.279)
PB15: CN7.3 CN12.26 U14.76 | length 63.2
  Top Layer w0.12: U14.76@42.366,82.863 43.948,84.445 45.758,84.445 46.108,84.795 46.642,84.795 46.992,84.445 54.569,84.445 v1(54.953,84.829) 55.241,85.117 55.241,85.9 56.029,86.688 62.648,86.688 63.639,87.679 68.479,87.679 v1(68.75,87.95) ; v1(55.075,98.025) 56.568,98.025 CN7.3@56.586,98.043
  Top Layer w0.127: U14.76@42.366,82.129 U14.76@42.366,82.863
  Bottom Layer w0.12: v1(54.953,84.829) 55.241,85.117 55.241,97.859 v1(55.075,98.025) ; CN12.26@66.746,71.094 68.001,72.349 68.001,81.562 67.275,82.288 67.275,82.76 67.851,83.336 67.851,85.437 68.165,85.751 68.165,87.365 v1(68.75,87.95)
PC0: CN9.3 CN11.38 U14.26 | length 47.7
  Top Layer w0.12: v1(38.4,64.525) 38.4,62.525 38.866,62.059 U14.26@38.866,60.479
  Signal Layer 2 w0.12: v1(7.216,65.554) 7.701,66.039 CN9.3@10.866,66.039 11.843,66.039 12.948,67.144 15.471,67.144 17.876,64.739 33.017,64.739 33.182,64.904 33.571,64.904 33.95,64.525 v1(38.4,64.525)
  Bottom Layer w0.12: CN11.38@5.786,55.879 5.786,56.511 7.131,57.856 7.131,58.115 7.396,58.38 7.396,65.374 v1(7.216,65.554)
PC1: CN11.36 SB64.2 U14.27 | length 48.5
  Top Layer w0.12: v1(38.925,62.65) 39.366,62.209 U14.27@39.366,60.479
  Signal Layer 2 w0.12: v1(6.516,62.429) 6.591,62.429 6.626,62.394 11.632,62.394 11.962,62.064 13.931,62.064 13.972,62.105 29.623,62.105 30.164,62.646 31.198,62.646 31.207,62.655 33.543,62.655 33.548,62.65 v1(38.925,62.65)
  Bottom Layer w0.12: CN11.36@5.786,58.419 6.891,59.524 6.891,61.887 6.516,62.262 v1(6.516,62.429) ; v1(38.925,62.65) 38.925,59.5 40.075,58.35 40.075,57.375 40.875,56.575 40.875,55.075 41.2,55.075 SB64.2@41.225,55.1
PC2: CN11.35 SB53.1 U14.28 | length 42.1
  Top Layer w0.12: v1(39.725,59.275) 39.866,59.416 U14.28@39.866,60.479
  Signal Layer 2 w0.12: CN11.35@3.246,58.419 4.351,57.314 6.9,57.314 7.353,56.862 9.15,56.862 9.529,57.24 14.025,57.24 14.7,57.915 14.7,58.471 v1(16.704,60.475) 16.774,60.405 38.595,60.405 v1(39.725,59.275)
  Bottom Layer w0.12: v1(16.704,60.475) 17.179,60.95 SB53.1@17.95,60.95
PC3: CN9.5 CN11.37 U14.29 | length 45.9
  Top Layer w0.12: v1(39.65,62.625) 39.65,61.95 40.366,61.234 U14.29@40.366,60.479
  Signal Layer 2 w0.12: v1(6.991,62.879) 10.246,62.879 CN9.5@10.866,63.499 12.061,62.304 13.832,62.304 13.873,62.345 29.524,62.345 30.074,62.895 38.42,62.895 38.425,62.89 38.59,63.055 39.093,63.055 39.523,62.625 v1(39.65,62.625)
  Bottom Layer w0.12: CN11.37@3.246,55.879 4.681,57.314 6.244,57.314 6.891,57.961 ; 6.891,57.955 6.891,57.961 ; v1(6.991,62.879) 6.991,62.127 7.141,61.977 7.141,58.494 6.891,58.244 6.891,57.961
PC4: CN12.34 SB36.2 U14.44 | length 34
  Top Layer w0.12: v1(44.4,66.475) 44.821,66.054 U14.44@45.941,66.054 45.941,65.995 47.563,65.995 49.888,68.32 53.374,68.32 54.55,67.144 57.044,67.144 57.559,66.629 58.153,66.629 58.668,67.144 67.444,67.144 v1(67.653,67.353)
  Signal Layer 2 w0.12: CN12.34@66.746,60.934 66.746,61.911 67.851,63.016 67.851,64.151 67.445,64.557 67.445,64.893 68.13,65.578 68.13,66.877 v1(67.653,67.353)
  Bottom Layer w0.12: v1(44.4,66.475) SB36.2@45.45,66.475
PC5: CN12.6 SB29.2 U14.45 | length 74.7
  Top Layer w0.12: v1(38.327,66.503) 39.03,65.8 42.925,65.8 44.05,66.925 44.7,66.925 45.071,66.554 U14.45@45.941,66.554
  Signal Layer 2 w0.12: v1(33.4,72.675) v1(36.825,72.675) v1(42.05,72.675) ; v1(41.95,95.75) 42.525,96.325 55.845,96.325 56.128,96.608 60.112,96.608 60.749,95.971 62.656,95.971 63.327,95.3 65.477,95.3 66.671,96.494 CN12.6@66.746,96.494
  Bottom Layer w0.12: SB29.2@32.375,72.675 v1(33.4,72.675) ; v1(36.825,72.675) 37.225,72.275 37.225,67.65 38.327,66.548 v1(38.327,66.503) ; v1(41.95,95.75) 41.95,95.05 42.355,94.645 42.355,94.035 42.195,93.875 42.195,89.073 42.047,88.925 42.047,79.237 41.885,79.075 41.885,72.84 v1(42.05,72.675)
PC6: CN7.1 CN12.4 U14.96 | length 51.6
  Top Layer w0.12: U14.96@32.366,82.129 32.366,83.166 36.29,87.09 47.526,87.09 48.835,88.399 48.835,89.449 49.426,90.04 50.437,90.04 50.769,89.708 54.533,89.708 v1(54.75,89.925) ; v1(55.053,100.605) 56.564,100.605 CN7.1@56.586,100.583 57.691,101.688 60.607,101.688 62.156,100.139 65.641,100.139 CN12.4@66.746,99.034
  Bottom Layer w0.12: v1(54.75,89.925) 55.001,90.176 55.001,97.526 54.67,97.857 54.67,98.193 55.241,98.764 55.241,100.459 55.095,100.605 v1(55.053,100.605)
PC7: CN7.11 CN12.19 U14.97 | length 42.2
  Top Layer w0.12: U14.97@31.866,82.129 31.866,83.016 36.18,87.33 46.73,87.33 v1(46.9,87.5)
  Signal Layer 2 w0.12: v1(46.9,87.5) 47.055,87.345 56.048,87.345 CN7.11@56.586,87.883 ; v1(61.1,80.35) 62.57,80.35 CN12.19@64.206,78.714
  Bottom Layer w0.12: CN7.11@56.586,87.883 57.919,86.55 60.025,86.55 61.1,85.475 v1(61.1,80.35)
PC8: CN8.2 SB14.2 U14.98 | length 37.1
  Top Layer w0.12: U14.98@31.366,82.129 31.366,82.891 33.2,84.725 v1(33.2,84.975)
  Signal Layer 2 w0.12: CN8.2@13.406,91.439 14.876,92.909 22.341,92.909 22.575,92.675 35.375,92.675 v1(35.5,92.55)
  Bottom Layer w0.12: v1(33.2,84.975) 33.2,84.55 33.4,84.35 SB14.2@34.375,84.35 34.88,84.855 35.355,84.855 35.5,85 v1(35.5,92.55)
PC9: CN8.4 SB15.1 U14.99 | length 28.9
  Top Layer w0.12: U14.99@30.866,82.129 30.866,83.041 v1(31.175,83.35)
  Signal Layer 2 w0.12: CN8.4@13.406,88.899 16.074,88.899 17.225,90.05 17.23,90.045 v1(32.795,90.045)
  Bottom Layer w0.12: v1(31.175,83.35) 32.05,84.225 SB15.1@32.05,84.45 32.65,84.45 32.795,84.595 v1(32.795,90.045)
PC10: CN8.6 CN11.1 U14.111 | length 44.2
  Top Layer w0.12: v1(8.366,86.904) 8.929,87.467 10.991,87.467
  Top Layer w0.127: 10.991,87.467 11.325,87.467 12.434,86.359 CN8.6@13.406,86.359 ; v1(22.475,86.2) 22.325,86.2 21.85,85.725 21.85,81.575 22.838,80.587 25.288,80.587 25.425,80.45 25.425,79.225 25.254,79.054 U14.111@24.291,79.054
  Signal Layer 2 w0.127: CN8.6@13.406,86.359 13.565,86.2 v1(22.475,86.2)
  Bottom Layer w0.12: 6.316,100.304 7.611,99.009 7.611,87.853 8.366,87.098 v1(8.366,86.904)
  Bottom Layer w0.127: CN11.1@3.246,101.599 4.541,100.304 6.316,100.304
PC11: CN8.8 CN11.2 U14.112 | length 42.3
  Top Layer w0.12: v1(22.375,83.775) 22.375,83.825 22.093,83.544 22.093,81.676 22.938,80.831 25.388,80.831 25.669,80.551 25.669,78.943 25.279,78.554 U14.112@24.291,78.554
  Top Layer w0.127: CN8.8@13.406,83.819 CN8.8@14.206,83.819
  Signal Layer 2 w0.12: CN8.8@13.406,83.819 13.45,83.775 v1(22.375,83.775)
  Signal Layer 2 w0.127: v1(8.466,85.704) 9.159,85.01 12.214,85.01 CN8.8@13.406,83.819
  Bottom Layer w0.127: CN11.2@5.786,101.599 7.854,99.53 7.854,88.079 8.775,87.159 8.775,85.987 8.466,85.679 v1(8.466,85.704)
PC12: CN8.10 CN11.3 U14.113 | length 38
  Top Layer w0.12: CN8.10@13.406,81.279 14.01,80.675 20.375,80.675 22.996,78.054 U14.113@24.291,78.054
  Signal Layer 2 w0.12: v1(7.916,82.354) 8.295,81.975 9.85,81.975 10.259,82.384 12.301,82.384 CN8.10@13.406,81.279
  Bottom Layer w0.12: 4.551,97.754 4.551,95.569 4.941,95.179 6.416,95.179 7.131,94.464 7.131,87.654 7.653,87.132 7.653,82.617 v1(7.916,82.354)
  Bottom Layer w0.127: CN11.3@3.246,99.059 4.551,97.754
PC13: CN11.23 SB51.2 U14.7 | length 42.4
  Top Layer w0.12: v1(2.486,62.064) 3.704,62.064 4.268,61.5 4.764,61.5 5.328,62.064 6.308,62.064 6.348,62.024 6.684,62.024 7.054,62.394 18.992,62.394 19.624,61.761 27.864,61.761 v1(27.925,61.7) 29.075,61.7 29.366,61.409 U14.7@29.366,60.479
  Bottom Layer w0.12: v1(2.486,62.064) 2.02,62.53 2.02,71.922 2.43,72.332 2.43,72.843 CN11.23@3.246,73.659 ; SB51.2@27.925,60.425 v1(27.925,61.7)
PC14: CN11.25 SB41.1 | length 32.7
  Signal Layer 2 w0.12: CN11.25@3.246,71.119 4.441,72.314 6.686,72.314 7.02,71.98 8.05,71.98 8.121,71.909 20.041,71.909 21.825,70.125 v1(29.025,70.125)
  Bottom Layer w0.12: SB41.1@28.975,64.6 28.975,70.075 v1(29.025,70.125)
PC14-OSC32_IN: R38.1 SB41.2 U14.8 | length 6.4
  Top Layer w0.12: R38.1@29.225,57.875 29.425,57.875 29.866,58.316 U14.8@29.866,60.479 v1(29.866,61.734)
  Bottom Layer w0.12: SB41.2@28.975,63.5 28.975,63.375 29.866,62.484 v1(29.866,61.734)
PC15: CN11.27 SB40.1 | length 34.4
  Signal Layer 2 w0.127: CN11.27@3.246,68.579 4.678,70.01 6.337,70.01 6.531,69.816 6.869,69.816 8.718,71.665 19.941,71.665 22.439,69.166 23.316,69.166 23.867,69.717 29.541,69.717 v1(29.75,69.925)
  Bottom Layer w0.127: v1(29.75,69.925) 29.218,69.394 29.218,65.957 29.875,65.3
PC15-OSC32_OUT: R39.1 SB40.2 U14.9 | length 6
  Top Layer w0.12: v1(30.366,62.241) U14.9@30.366,60.479 30.366,59.749 30.125,59.508 30.125,58.225 30.475,57.875 R39.1@30.625,57.875
  Bottom Layer w0.12: v1(30.366,62.241) 30.375,62.25 SB40.2@30.375,63.5
PD0: CN9.25 CN11.57 U14.114 | length 87
  Top Layer w0.12: CN11.57@3.246,30.479 1.046,32.679 1.046,75.955 2.692,77.601 7.816,77.601 10.306,80.091 20.434,80.091 22.971,77.554 U14.114@24.291,77.554 ; v1(7.375,38.275) 10.69,38.275 CN9.25@10.866,38.099
  Bottom Layer w0.12: CN11.57@3.246,30.479 4.591,31.824 4.591,33.702 5.103,34.214 6.343,34.214 6.837,34.708 7.468,34.708 7.705,34.945 7.705,35.323 7.378,35.65 7.378,36.218 7.138,36.458 7.138,38.038 v1(7.375,38.275)
PD1: CN9.27 CN11.55 U14.115 | length 80
  Top Layer w0.127: v1(4.125,41.602) 3.98,41.747 1.803,41.747 1.289,42.261 1.289,75.854 2.743,77.307 7.894,77.307 9.758,79.17 9.758,79.198 10.407,79.847 20.128,79.847 22.921,77.054 U14.115@24.291,77.054
  Signal Layer 2 w0.127: CN11.55@3.246,33.019 4.438,34.21 6.398,34.21 v1(7.3,35.113) 7.746,35.559 CN9.27@10.866,35.559
  Bottom Layer w0.127: v1(4.125,41.602) 4.1,41.577 4.1,41.55 4.354,41.296 4.354,39.496 4.643,39.207 6.245,39.207 6.894,38.558 6.894,36.357 7.134,36.117 7.134,35.3 7.3,35.134 v1(7.3,35.113)
PD2: CN8.12 CN11.4 U14.116 | length 38.1
  Top Layer w0.12: CN8.12@13.406,78.739 20.661,78.739 22.846,76.554 U14.116@24.291,76.554
  Signal Layer 2 w0.12: v1(7.725,80.45) 8.001,80.174 11.971,80.174 CN8.12@13.406,78.739
  Bottom Layer w0.12: CN11.4@5.786,99.059 7.371,97.474 7.371,87.754 7.893,87.232 7.893,82.95 8.321,82.522 8.321,82.125 7.725,81.529 v1(7.725,80.45)
PD3: CN9.10 CN11.40 U14.117 | length 50.9
  Top Layer w0.12: v1(7.666,76.555) 8.076,76.145 8.91,76.145 10.309,77.544 21.406,77.544 22.896,76.054 U14.117@24.291,76.054
  Top Layer w0.127: CN11.40@5.786,53.339 7.576,53.339 v1(7.566,53.329)
  Signal Layer 2 w0.12: v1(8.616,57.579) 8.616,57.966 10.264,59.614 11.497,59.614 11.771,59.34 12.485,59.34 CN9.10@13.406,58.419
  Bottom Layer w0.12: v1(7.566,53.329) 8.331,54.094 8.331,57.294 v1(8.616,57.579) 8.596,57.599 8.596,61.361 8.971,61.736 8.971,62.072 8.596,62.447 8.596,64.355 9.086,64.845 9.086,70.201 8.486,70.801 8.486,72.003 8.133,72.356 8.133,76.088 v1(7.666,76.555)
PD4: CN9.8 CN11.39 U14.118 | length 50.8
  Top Layer w0.12: v1(7.666,75.905) 9.009,75.905 10.408,77.304 21.296,77.304 23.046,75.554 U14.118@24.291,75.554
  Signal Layer 2 w0.12: CN11.39@3.246,53.339 4.434,54.527 7.639,54.527 v1(7.841,54.729) ; v1(8.566,61.904) 8.816,62.154 11.532,62.154 11.862,61.824 12.541,61.824 CN9.8@13.406,60.959
  Bottom Layer w0.12: v1(7.666,75.905) 7.666,74.759 7.893,74.532 7.893,72.257 8.246,71.904 8.246,70.702 8.846,70.102 8.846,64.944 8.356,64.454 8.356,62.114 v1(8.566,61.904) 8.356,61.694 8.356,57.892 8.091,57.627 8.091,55.242 7.847,54.998 7.847,54.735 v1(7.841,54.729)
PD5: CN9.6 CN11.41 U14.119 | length 45.6
  Top Layer w0.12: v1@9.554,64.125 v1(9.6,64.078) ; v1(14.576,74.404) 14.572,74.4 15.036,74.4 15.689,75.054 U14.119@24.291,75.054
  Signal Layer 2 w0.12: CN11.41@3.246,50.799 4.372,51.925 7.925,51.925 8.25,51.6 8.281,51.631 v1(8.281,51.637) ; v1(9.6,64.078) 10.182,64.66 12.245,64.66 CN9.6@13.406,63.499
  Signal Layer 3 w0.12: v1(8.281,51.637) v1@8.293,51.625
  Bottom Layer w0.12: v1(8.281,51.637) 8.281,52.792 9.051,53.562 9.051,56.762 9.501,57.212 9.501,58.215 9.316,58.4 9.316,61.063 9.691,61.438 9.691,62.37 9.316,62.745 9.316,63.841 9.575,64.1 9.579,64.1 v1(9.6,64.078) ; CN9.6@13.406,63.499 14.55,64.643 14.55,66.843 14.751,67.044 14.751,73.203 15.13,73.582 15.13,73.918 14.644,74.404 v1(14.576,74.404)
PD6: CN9.4 CN11.43 U14.122 | length 49.3
  Top Layer w0.12: CN11.43@3.246,48.259 1.556,49.948 1.556,64.507 1.984,64.934 7.371,64.934 7.661,65.224 7.661,65.472 9.414,67.225 11.302,67.225 11.707,66.82 12.625,66.82 CN9.4@13.406,66.039 ; v1(14.725,73.75) 15.789,74.814 22.011,74.814 23.271,73.554 U14.122@24.291,73.554
  Bottom Layer w0.12: CN9.4@13.406,66.039 14.511,67.144 14.511,73.536 v1(14.725,73.75)
PD7: CN9.2 CN11.45 U14.123 | length 52.7
  Top Layer w0.12: v1(8.25,68.95) 9.079,69.779 12.206,69.779 CN9.2@13.406,68.579 ; v1(14.101,72.554) 14.101,72.599 14.351,72.6 16.325,74.574 21.776,74.574 23.296,73.054 U14.123@24.291,73.054
  Top Layer w0.127: CN11.45@3.246,45.719 4.431,44.534 7.397,44.534 v1(7.591,44.729)
  Bottom Layer w0.12: v1(7.591,44.729) 7.591,46.778 7.796,46.983 7.796,47.318 7.171,47.943 7.171,49.872 7,50.043 7,50.865 7.396,51.261 7.396,51.596 7.159,51.834 7.151,51.834 7.131,51.854 7.131,54.621 7.851,55.341 7.851,57.726 8.116,57.991 8.116,64.554 8.606,65.044 8.606,68.594 v1(8.25,68.95) ; CN9.2@13.406,68.579 14.271,69.444 14.271,72.383 v1(14.101,72.554)
PD8: SB18.1 SB19.1 SB82.2 U14.77 | length 21.4
  Top Layer w0.12: U14.77@41.866,82.129 41.866,82.858 43.693,84.685 45.658,84.685 46.008,85.035 46.865,85.035 46.95,84.95 46.973,84.95 v1(47.027,85.004) 47.346,84.685 50.485,84.685 50.95,85.15 v1(50.95,85.125)
  Bottom Layer w0.12: v1(47.027,85.004) 47.027,84.543 47.12,84.45 SB19.1@47.875,84.45 SB18.1@49.275,84.45 ; v1(50.95,85.125) 50.643,85.432 50.643,91.268 v1(50.975,91.6) SB82.2@50.975,92.375
PD9: SB12.1 SB66.2 SB81.1 U14.78 | length 121.9
  Top Layer w0.12: U14.78@41.366,82.129 41.366,82.866 43.55,85.05 44.55,85.05 v1(44.6,85.1) 45.734,85.1 46.043,85.409 47.195,85.409 47.679,84.925 50.025,84.925 v1(50.225,85.125)
  Signal Layer 2 w0.12: v1(15.675,31.1) 22.702,31.1 22.707,31.105 23.043,31.105 23.189,30.959 48.209,30.959 v1(48.375,31.125)
  Bottom Layer w0.12: SB81.1@11.9,14.125 13.475,14.125 15.675,16.325 v1(15.675,31.1) ; v1(44.6,85.1) 44.6,84.575 44.75,84.425 45.45,84.425 SB12.1@45.475,84.45 ; v1(48.375,31.125) 48.58,31.33 48.58,32.88 47.995,33.465 47.995,42.089 47.722,42.362 47.722,43.495 47.786,43.559 47.786,43.564 48.625,44.403 48.625,51.542 49.442,52.359 49.442,53.631 v1(49.686,53.875) ; v1(50.225,85.125) 50,84.9 50,68.337 49.525,67.862 49.525,66.214 50.15,65.589 50.15,56.896 49.55,56.296 49.55,54.932 49.442,54.824 49.442,54.119 v1(49.686,53.875) ; SB66.2@50.6,54.175 50.3,53.875 v1(49.686,53.875)
PD10: CN12.65 SB77.1 U14.79 | length 148.9
  Top Layer w0.12: U14.79@40.866,82.129 40.866,82.858 43.658,85.65 v1(54.775,85.65)
  Signal Layer 2 w0.12: v1(28.475,37.325) 29,37.85 35.4,37.85 36.101,37.149 38.89,37.149 39.191,37.45 46.006,37.45 48.065,39.509 59.525,39.509 60.209,38.825 v1(60.95,38.825) ; v1(54.775,85.65) 55.33,85.65 56.128,86.448 62.427,86.448 62.725,86.15 62.696,86.121 v1(62.696,86.043)
  Bottom Layer w0.12: v1(28.475,37.325) 28.175,37.025 28.175,19.725 28.65,19.25 28.65,17.644 28.986,17.644 28.646,17.304 SB77.1@28.646,17.644 ; v1(60.95,38.825) v1@60.95,38.8 ; v1(62.696,86.043) 62.696,79.888 62.861,79.723 62.861,67 62.766,66.905 62.757,66.905 62.52,66.668 62.52,65.305 62.861,64.964 62.861,62.486 61.967,61.592 61.967,61.571 61.962,61.565 61.962,60.418 62.322,60.058 62.322,58.682 61.722,58.082 61.722,50.468 61.191,49.937 61.191,48.323 61.74,47.774 61.74,46.765 60.711,45.736 60.711,39.039 v1@60.95,38.8 ; CN12.65@64.206,20.294 62.854,21.646 62.854,35.646 60.95,37.55 v1@60.95,38.8
PD11: CN10.23 CN12.45 U14.80 | length 75.9
  Top Layer w0.12: U14.80@40.366,82.129 40.366,82.866 43.39,85.89 54.128,85.89 v1(54.575,86.337) ; v1(61.125,46.824) 63.076,46.824 CN12.45@64.206,45.694
  Signal Layer 2 w0.12: v1(54.575,86.337) 55.678,86.337 56.029,86.688 62.338,86.688 62.628,86.978 v1(62.628,87.272) ; CN10.23@56.586,45.719 57.691,46.824 v1(61.125,46.824)
  Bottom Layer w0.12: v1(61.125,46.824) 61.5,47.199 61.5,47.675 60.951,48.224 60.951,50.037 61.482,50.568 61.482,58.181 62.082,58.781 62.082,59.958 61.722,60.318 61.722,61.67 61.727,61.676 61.727,61.692 62.621,62.585 62.621,64.865 62.28,65.206 62.28,66.767 62.621,67.108 62.621,79.624 62.291,79.954 62.291,86.935 v1(62.628,87.272)
PD12: CN10.21 CN12.43 U14.81 | length 78.1
  Top Layer w0.12: U14.81@39.866,82.129 39.866,82.866 43.13,86.13 53.68,86.13 54.775,87.225 v1(54.775,87.775) ; v1(61,47.525) 61.709,48.234 CN12.43@64.206,48.234
  Signal Layer 2 w0.12: v1(54.775,87.775) 55.988,88.988 62.387,88.988 62.725,88.65 62.725,88.604 v1(62.696,88.575) ; CN10.21@56.586,48.259 57.781,47.064 60.539,47.064 v1(61,47.525)
  Signal Layer 3 w0.12: v1(62.696,88.575) v1@62.696,88.595
  Bottom Layer w0.12: v1(61,47.525) 60.711,47.814 60.711,50.136 61.242,50.667 61.242,58.281 61.842,58.881 61.842,59.859 61.482,60.219 61.482,61.775 61.487,61.78 ; 61.482,61.786 62.381,62.685 62.381,64.765 62.04,65.106 62.04,66.867 62.381,67.208 62.381,79.524 62.051,79.854 62.051,87.268 62.696,87.913 v1(62.696,88.575)
PD13: CN10.19 CN12.41 U14.82 | length 76.5
  Top Layer w0.12: U14.82@39.366,82.129 39.366,82.858 42.878,86.37 53.581,86.37 54.35,87.139 54.35,88.025 v1(54.75,88.425) ; v1(60.556,50.8) 60.582,50.774 CN12.41@64.206,50.774
  Signal Layer 2 w0.12: v1(54.75,88.425) 54.782,88.457 55.118,88.457 55.888,89.228 61.978,89.228 v1(62.475,89.725) ; CN10.19@56.586,50.799 57.71,49.675 59.565,49.675 60.556,50.666 v1(60.556,50.8)
  Bottom Layer w0.12: v1(60.556,50.8) 60.556,51.885 61.002,52.331 61.002,58.38 61.602,58.98 61.602,59.759 61.242,60.119 61.242,61.885 62.141,62.784 62.141,64.666 61.8,65.007 61.8,66.984 62.141,67.325 62.141,79.425 61.811,79.755 61.811,87.367 62.291,87.847 62.291,89.491 62.525,89.725 v1(62.475,89.725)
PD14: CN7.16 CN12.46 U14.85 | length 73.7
  Top Layer w0.12: U14.85@37.866,82.129 37.866,81.134 38.154,80.846 46.796,80.846 48.27,82.32 55.305,82.32 55.927,81.698 58.021,81.698 CN7.16@59.126,82.803 59.991,83.668 62.726,83.668 63.705,82.689 67.543,82.689 67.729,82.875 v1(68.55,82.875) ; CN12.46@66.746,45.694 68.695,45.694 v1(68.703,45.702)
  Bottom Layer w0.12: v1(68.55,82.875) 68.721,82.704 68.721,66.544 68.37,66.193 68.37,65.857 68.961,65.266 68.961,45.936 68.725,45.7 68.723,45.702 v1(68.703,45.702)
PD15: CN7.18 CN12.48 U14.86 | length 81.5
  Top Layer w0.12: U14.86@37.366,82.129 37.366,81.084 37.844,80.606 46.896,80.606 48.369,82.08 55.206,82.08 55.828,81.458 57.931,81.458 CN7.18@59.126,80.263 59.126,80.149 61.426,82.449 68.001,82.449 68.088,82.362 v1(68.112,82.362) ; CN12.48@66.746,43.154 68.679,43.154 v1(68.7,43.175)
  Bottom Layer w0.12: v1(68.112,82.362) 68.214,82.362 68.481,82.095 68.481,69.681 67.898,69.098 67.898,68.538 68.061,68.375 68.061,67.172 67.825,66.936 67.387,66.936 67.204,67.119 66.288,67.119 65.641,66.472 65.641,65.556 66.288,64.909 67.284,64.909 67.505,65.13 68.059,65.13 68.301,64.888 68.301,63.951 68.148,63.799 68.148,63.31 68.301,63.158 68.301,54.975 68.145,54.819 68.145,54.482 68.721,53.906 68.721,46.293 68.298,45.87 68.298,45.502 68.7,45.1 v1(68.7,43.175)
PE0: CN10.33 CN12.64 U14.141 | length 90.7
  Top Layer w0.12: U14.141@24.291,64.054 v1(25.954,64.054)
  Signal Layer 2 w0.12: v1(22.875,30.7) 22.894,30.719 54.286,30.719 CN10.33@56.586,33.019 58.255,31.35 58.975,31.35 61.125,29.2 v1(67.3,29.2)
  Bottom Layer w0.12: v1(22.875,30.7) 22.875,42.518 23.407,43.05 23.407,45.102 23.164,45.346 23.164,61.264 v1(25.954,64.054) ; CN12.64@66.746,22.834 68.025,24.113 68.025,28.475 v1(67.3,29.2)
PE1: CN11.61 R71.1 U14.142 | length 151
  Top Layer w0.127: v1(8.066,65.304) 9.846,65.304 10.22,64.93 13.865,64.93 14.551,65.616 17.944,65.616 18.344,66.016 21.311,66.016 22.95,64.377 22.95,63.841 23.238,63.554 U14.142@24.291,63.554
  Signal Layer 2 w0.12: v1(2.541,103.406) 2.543,103.404 6.666,103.404 9.616,100.454 11.593,100.454 11.598,100.459 11.934,100.459 12.234,100.159 33.571,100.159 v1(35.391,101.979)
  Signal Layer 2 w0.127: v1(1.975,54.878) 1.975,54.825 2.03,54.77 6.707,54.77 v1(7.341,55.404)
  Signal Layer 3 w0.12: v1@2.489,103.406 v1(2.541,103.406)
  Bottom Layer w0.12: 1.734,92.885 1.526,93.094 1.526,102.392 v1(2.541,103.406) ; v1(7.341,55.404) 7.611,55.674 7.611,57.825 7.876,58.09 7.876,65.114 7.879,65.118
  Bottom Layer w0.127: 1.734,92.885 2.073,92.547 3.705,92.547 4.354,91.898 4.354,87.915 4.802,87.467 6.245,87.467 6.894,86.818 6.894,83.36 6.245,82.71 4.678,82.71 4.354,82.387 4.354,75.615 4.962,75.007 6.345,75.007 7.134,74.217 7.134,66.597 7.879,65.852 7.879,65.491 v1(8.066,65.304) 7.879,65.118 ; v1(1.975,54.878) 1.536,54.439 1.536,38.233 3.091,36.679 3.694,36.679 4.354,36.018 4.354,35.1 3.705,34.45 2.215,34.45 1.049,33.285 1.049,27.595 CN11.61@3.246,25.399
  Bottom Layer w0.3: v1(35.391,101.979) R71.1@36.166,101.979
PE2: CN10.25 CN11.46 SB67.2 U14.1 | length 77.1
  Top Layer w0.12: CN11.46@5.786,45.719 9.303,45.719 10.408,44.614 14.167,44.614 14.477,44.304 23.771,44.304 v1(23.9,44.175) 26.025,44.175 26.9,45.05 51.85,45.05 53.721,43.179 CN10.25@56.586,43.179 ; v1(18.925,54.15) 18.95,54.125 23.65,54.125 v1(23.625,54.15)
  Top Layer w0.127: v1(23.825,58.65) 25.637,58.65 26.266,59.279 U14.1@26.266,60.479
  Bottom Layer w0.12: v1(18.925,54.15) SB67.2@18.925,54.9 ; v1(23.625,54.15) 23.65,54.175 23.65,56.5 23.404,56.746 23.404,58.229 v1(23.825,58.65) ; v1@23.65,54.15 23.65,52.17 23.404,51.924 23.404,45.445 23.9,44.949 v1(23.9,44.175)
PE3: CN9.22 CN11.47 U14.2 | length 42.4
  Top Layer w0.12: 15.425,43.179 22.321,43.179 22.725,42.775 v1(23.9,42.775) ; v1(23.851,57.978) 23.851,58.008 24.25,58.406 25.782,58.406 26.866,59.491 U14.2@26.866,60.479
  Top Layer w0.127: CN11.47@3.246,43.179 4.354,44.287 12.298,44.287 CN9.22@13.406,43.179 15.425,43.179
  Signal Layer 2 w0.12: v1@23.851,57.976 v1(23.851,57.978)
  Bottom Layer w0.12: v1(23.851,57.978) 23.675,57.802 23.675,56.93 24.055,56.55 24.055,54.1 24.048,54.093 24.048,52.229 23.644,51.825 23.644,45.544 24.305,44.883 24.305,44.005 23.9,43.6 v1(23.9,42.775)
PE4: CN9.16 CN11.48 U14.3 | length 37.6
  Top Layer w0.12: v1(24.508,57.908) 24.508,57.925 24.75,58.167 25.916,58.167 27.366,59.616 U14.3@27.366,60.479
  Top Layer w0.127: v1(6.766,49.704) 7.679,49.704 9.965,51.99 11.51,51.99 12.701,50.799 CN9.16@13.406,50.799 13.949,50.799 14.81,51.66 23.915,51.66 v1(24.125,51.45)
  Bottom Layer w0.12: 24.295,52.225 24.295,56.83 24,57.125 24,57.4 v1(24.508,57.908)
  Bottom Layer w0.127: CN11.48@5.786,43.179 6.916,44.309 6.916,49.554 v1(6.766,49.704) ; v1(24.125,51.45) 24.292,51.617 24.292,52.225
PE5: CN9.18 CN11.50 U14.4 | length 38.6
  Top Layer w0.12: CN9.18@13.406,48.259 13.722,48.575 v1(24.05,48.575) ; v1(24.45,57.25) 24.45,57.277 25.099,57.927 26.227,57.927 27.866,59.566 U14.4@27.866,60.479
  Top Layer w0.127: v1(7.391,47.15) 12.298,47.15 CN9.18@13.406,48.259
  Bottom Layer w0.12: v1(24.05,48.575) 24.535,49.06 24.535,57.165 v1(24.45,57.25)
  Bottom Layer w0.127: CN11.50@5.786,40.639 7.166,42.019 7.166,46.925 v1(7.391,47.15)
PE6: CN11.62 SB71.2 SB73.2 U14.5 | length 92.3
  Top Layer w0.12: CN11.62@5.786,25.399 23.274,25.399 v1(23.275,25.4) ; v1(18.9,45.875) 23.925,45.875 v1(24.125,45.675) v1(49.075,45.675) ; v1(25.15,57.4) 25.163,57.4 25.45,57.687 26.326,57.687 28.366,59.727 U14.5@28.366,60.479
  Bottom Layer w0.12: v1(18.9,45.875) SB71.2@18.9,46.625 ; v1(23.275,25.4) 23.275,30.362 23.28,30.367 23.28,30.868 23.115,31.033 23.115,41.417 24.545,42.847 24.545,45.255 v1(24.125,45.675) 24.775,46.325 24.775,57 25.15,57.375 v1(25.15,57.4) ; v1(49.075,45.675) 49.775,44.975 49.775,41.5 SB73.2@50.6,40.675
PE7: CN10.20 CN12.44 U14.58 | length 48.2
  Top Layer w0.12: U14.58@45.941,73.054 46.896,73.054 47.486,72.464 54.399,72.464 54.783,72.08 55.317,72.08 55.701,72.464 60.989,72.464 61.2,72.675 v1(61.225,72.675)
  Top Layer w0.127: CN10.20@59.126,50.799 60.26,49.665 65.314,49.665 CN12.44@66.746,48.234
  Bottom Layer w0.12: CN10.20@59.126,50.799 CN10.20@59.361,51.034 ; 60.841,62.992 60.84,62.993 60.84,67.437 60.565,67.712 60.565,69.253 61.421,70.109 61.421,72.479 v1(61.225,72.675)
  Bottom Layer w0.127: CN10.20@59.361,51.034 60.758,52.431 60.758,58.481 61.359,59.081 61.359,59.659 60.998,60.019 60.998,62.84 60.844,62.995
PE8: CN10.18 CN12.40 U14.59 | length 46.8
  Top Layer w0.12: U14.59@45.941,73.554 46.896,73.554 47.746,72.704 54.498,72.704 54.882,72.32 55.218,72.32 55.481,72.583 55.481,74.658 55.648,74.825 57.8,74.825 v1(58.25,75.275)
  Signal Layer 2 w0.12: CN10.18@59.126,53.339 62.664,53.339 63.744,54.419 65.641,54.419 CN12.40@66.746,53.314
  Bottom Layer w0.12: v1(58.25,75.275) 57.931,74.956 57.931,70.374 57.691,70.134 57.691,67.982 58.282,67.391 58.282,67.097 57.931,66.746 57.931,54.534 CN10.18@59.126,53.339
PE9: CN12.52 SB28.2 SB70.1 U14.60 | length 99.2
  Top Layer w0.12: v1(18.85,50.95) 26.05,50.95 26.725,50.275 30.675,50.275 31.474,49.476 55.648,49.476 v1(55.8,49.325) ; U14.60@45.941,74.054 46.846,74.054 47.956,72.944 50.944,72.944 51.328,73.328 ; v1(51.328,73.829) 51.328,73.328 ; v1(55.05,72.725) 54.831,72.944 51.711,72.944 51.328,73.328 ; v1(55.625,36.7) 55.661,36.664 65.336,36.664 CN12.52@66.746,38.074
  Bottom Layer w0.12: v1(18.85,50.95) SB70.1@18.85,51.7 ; SB28.2@50.6,72.944 50.6,73.4 51,73.8 51.299,73.8 v1(51.328,73.829) ; v1(55.05,72.725) 55.235,72.54 55.235,69.469 55.001,69.235 55.001,67.922 55.481,67.442 55.481,51.596 55.241,51.356 55.241,50.17 55.8,49.611 v1(55.8,49.325) 55.75,49.325 55.425,49 55.425,39.598 55.755,39.268 55.755,38.93 55.425,38.6 55.425,36.9 v1(55.625,36.7)
PE10: CN10.24 CN12.47 U14.63 | length 50.5
  Top Layer w0.12: U14.63@45.941,75.554 45.945,75.55 55.3,75.55 v1(55.325,75.525)
  Signal Layer 2 w0.12: CN10.24@59.126,45.719 61.641,45.719 CN12.47@64.206,43.154
  Bottom Layer w0.12: v1(55.325,75.525) 55.325,75.55 55.475,75.4 55.475,69.37 55.241,69.136 55.241,68.022 56.029,67.234 56.954,67.234 57.691,66.497 57.691,52.551 57.044,51.904 56.128,51.904 55.481,51.257 55.481,50.269 56.15,49.6 56.808,49.6 57.691,48.717 57.691,47.154 CN10.24@59.126,45.719
PE11: CN10.6 CN12.56 U14.64 | length 72.5
  Top Layer w0.12: U14.64@45.941,76.054 55.403,76.054 55.774,75.683 56.325,75.683 ; 56.325,75.68 60.605,75.68 v1(61,76.075) ; v1(60.225,31.325) 60.245,31.305 63.495,31.305 63.748,31.559 65.311,31.559 CN12.56@66.746,32.994
  Bottom Layer w0.12: v1(60.225,31.325) 60.471,31.571 60.471,48.922 59.699,49.694 58.668,49.694 58.021,50.341 58.021,51.257 58.668,51.904 59.618,51.904 60.515,52.801 60.515,62.639 60.36,62.794 60.36,64.864 60.36,67.169 60.36,67.238 59.126,68.472 CN10.6@59.126,68.579 59.213,68.579 60.941,70.307 60.941,71.951 60.58,72.312 60.58,72.942 61.181,73.543 61.181,75.894 v1(61,76.075)
PE12: CN10.26 CN12.49 U14.65 | length 72.2
  Top Layer w0.12: U14.65@45.941,76.554 47.271,76.554 47.531,76.294 55.502,76.294 55.873,75.923 60.275,75.923 60.832,76.48 62.949,76.48 63.748,77.279 65.571,77.279 65.75,77.1 v1(65.775,77.1) ; CN10.26@59.126,43.179 61.641,43.179 CN12.49@64.206,40.614
  Signal Layer 2 w0.12: CN12.49@64.206,40.614 64.314,40.614 65.419,41.719 67.558,41.719 68.145,42.306 68.145,56.705 67.561,57.289 66.288,57.289 65.641,57.936 65.641,64.393 65.323,64.71 65.323,65.046 65.641,65.364 65.641,67.086 65.32,67.407 65.32,67.743 65.641,68.064 65.641,69.012 66.288,69.659 67.2,69.659 68.091,70.55 68.091,76.392 67.204,77.279 65.954,77.279 v1(65.775,77.1)
PE13: CN10.10 CN12.55 U14.66 | length 78.8
  Top Layer w0.12: U14.66@45.941,77.054 47.111,77.054 47.631,76.534 55.602,76.534 55.973,76.163 60.176,76.163 60.913,76.9 v1(61,76.9) ; v1(59.803,31.852) 59.751,31.8 63.012,31.8 CN12.55@64.206,32.994
  Signal Layer 2 w0.12: CN10.10@59.126,63.499 60.31,64.683 64.621,64.683 65.401,65.463 65.401,66.987 65.08,67.308 65.08,67.842 65.401,68.163 65.401,69.111 65.641,69.351 65.641,74.71 65.282,75.069 63.748,75.069 63.101,75.716 63.101,76.1 62.301,76.9 v1(61,76.9)
  Bottom Layer w0.12: CN10.10@59.126,63.499 60.275,62.35 60.275,52.9 59.519,52.144 58.569,52.144 57.781,51.356 57.781,50.242 58.569,49.454 59.6,49.454 60.231,48.823 60.231,32.181 59.902,31.852 v1(59.803,31.852)
PE14: CN10.8 CN12.51 U14.67 | length 69.8
  Top Layer w0.12: U14.67@45.941,77.554 47.096,77.554 47.876,76.774 55.701,76.774 56.072,76.403 59.828,76.403 v1(60,76.575)
  Signal Layer 2 w0.12: CN10.8@59.126,66.039 58.021,64.934 58.021,60.501 58.693,59.829 64.947,59.829 65.401,59.375 65.401,57.837 66.189,57.049 67.462,57.049 67.905,56.606 67.905,42.405 67.47,41.97 66.47,41.97 66.459,41.959 63.988,41.959 63.101,41.072 63.101,39.179 CN12.51@64.206,38.074
  Bottom Layer w0.12: CN10.8@59.126,66.039 59.126,66.886 57.931,68.081 57.931,68.947 58.668,69.684 59.96,69.684 60.701,70.425 60.701,71.851 60.34,72.212 60.34,73.042 60.941,73.643 60.941,75.5 60.025,76.416 60.025,76.6 v1(60,76.575)
PE15: CN10.30 CN12.53 U14.68 | length 60
  Top Layer w0.12: U14.68@45.941,78.054 46.944,78.054 47.748,77.25 v1@55.305,77.25 ; v1(55.35,39.1) 55.45,39.1 55.619,39.269 57.956,39.269 CN10.30@59.126,38.099
  Signal Layer 2 w0.12: CN10.30@59.126,38.099 61.641,38.099 CN12.53@64.206,35.534
  Bottom Layer w0.12: v1(55.334,77.179) 54.92,76.765 54.92,73.168 54.425,72.673 54.425,70.952 54.755,70.622 54.755,69.668 54.173,69.086 54.173,67.861 54.458,67.575 55.009,67.575 55.241,67.343 55.241,51.695 55.001,51.455 55.001,50.07 55.185,49.886 55.185,39.265 v1(55.35,39.1)
PF0: CN9.21 CN11.53 U14.10 | length 54.4
  Top Layer w0.12: U14.10@30.866,60.479 v1(30.866,61.734)
  Signal Layer 2 w0.12: CN11.53@3.246,35.559 4.351,36.664 7.014,36.664 8.25,37.9 8.25,40.563 CN9.21@10.866,43.179 11.971,42.074 24.724,42.074 v1(24.723,42.075)
  Bottom Layer w0.12: v1(24.723,42.075) 25.255,42.607 25.255,50.355 27.05,52.15 31.925,52.15 32.625,52.85 32.625,56.575 31.93,57.27 31.93,58.545 30.866,59.609 v1(30.866,61.734)
PF1: CN9.19 CN11.51 U14.11 | length 55.9
  Top Layer w0.12: U14.11@31.366,60.479 31.375,60.488 v1(31.375,62.25)
  Signal Layer 2 w0.12: CN11.51@3.246,38.099 4.441,36.904 6.914,36.904 8.01,37.999 8.01,40.662 9.761,42.413 9.761,44.614 CN9.19@10.866,45.719 11.971,44.614 v1(25.686,44.614)
  Bottom Layer w0.12: v1(25.686,44.614) 25.495,44.805 25.495,50.256 27.149,51.91 32.024,51.91 32.865,52.751 32.865,56.674 32.17,57.369 32.17,58.644 31.375,59.439 v1(31.375,62.25)
PF2: CN9.17 CN11.52 U14.12 | length 50
  Top Layer w0.12: U14.12@31.866,60.479 v1(31.866,61.734)
  Signal Layer 2 w0.12: CN11.52@5.786,38.099 5.869,38.099 7.77,40 7.77,40.762 9.521,42.513 9.521,46.914 CN9.17@10.866,48.259 11.971,47.154 25.896,47.154 v1(25.9,47.15)
  Bottom Layer w0.12: v1(25.9,47.15) 25.9,50.321 27.249,51.67 32.124,51.67 33.105,52.651 33.105,56.774 32.41,57.469 32.41,58.744 31.866,59.288 v1(31.866,61.734)
PF3: CN7.20 CN12.58 U14.13 | length 102.3
  Top Layer w0.12: U14.13@32.375,60.488 v1(32.375,62.25) ; CN7.20@59.126,77.723 59.24,77.609 67.459,77.609 v1(67.575,77.725)
  Signal Layer 2 w0.12: v1(35.302,78.129) 35.486,77.945 55.245,77.945 56.128,78.828 57.044,78.828 58.149,77.723 CN7.20@59.126,77.723 ; v1(67.575,77.725) 67.575,77.247 68.331,76.491 68.331,70.45 67.851,69.97 67.851,67.799 68.37,67.28 68.37,65.245 v1(67.85,64.725)
  Bottom Layer w0.12: v1(32.375,62.25) 32.375,66.921 33.995,68.541 33.995,69.251 35.112,70.368 35.112,77.939 v1(35.302,78.129) ; CN12.58@66.746,30.454 68.961,32.669 68.961,42.341 68.295,43.007 68.295,43.385 68.46,43.55 68.46,45.001 68.058,45.402 68.058,45.969 68.481,46.392 68.481,53.807 67.905,54.383 67.905,54.918 68.061,55.074 68.061,63.058 67.908,63.211 67.908,64.667 v1(67.85,64.725)
PF4: CN12.38 SB38.1 U14.14 | length 51.8
  Top Layer w0.12: U14.14@32.866,60.479 v1(32.866,61.734) ; v1(50.7,67.675) 51.175,67.2 53.75,67.2 56.072,64.878 59.878,64.878 60.175,65.175 63.203,65.175 63.5,64.878 v1(65.728,64.878)
  Signal Layer 2 w0.12: v1(32.975,66.65) 33,66.65 33.275,66.925 47.932,66.925 48.682,67.675 v1(50.7,67.675) ; CN12.38@66.746,55.854 CN12.38@67.129,55.854
  Bottom Layer w0.12: v1(32.866,61.734) 32.866,62.459 32.615,62.71 32.615,66.265 32.975,66.625 v1(32.975,66.65) ; SB38.1@50.675,68.4 50.675,67.7 v1(50.7,67.675) ; v1(65.728,64.878) 65.697,64.878 65.675,64.9 65.551,64.776 65.551,57.049 CN12.38@66.746,55.854
PF5: CN12.36 SB48.1 U14.15 | length 48.6
  Top Layer w0.12: U14.15@33.375,60.488 v1(33.375,62.25) ; v1(50.7,67.025) 50.765,66.96 53.651,66.96 55.972,64.638 59.978,64.638 60.274,64.935 63.104,64.935 63.401,64.638 64.962,64.638 65.35,64.25 65.35,62.969 65.95,62.369 67.469,62.369 67.6,62.238 v1(67.6,61.975)
  Signal Layer 2 w0.12: v1@33.2,65.325 v1(33.225,65.325) 38.555,65.325 39.27,66.039 44.864,66.039 45.51,66.685 48.031,66.685 48.421,67.075 50.7,67.075 v1(50.7,67.025) ; CN12.36@66.746,58.394 67.851,59.499 67.851,61.724 v1(67.6,61.975)
  Bottom Layer w0.12: v1@33.213,65.337 32.855,64.98 32.855,62.809 33.375,62.289 v1(33.375,62.25) ; SB48.1@50.675,66.175 50.675,67 v1(50.7,67.025)
PF6: CN11.9 SB54.1 U14.18 | length 98.2
  Top Layer w0.12: v1(33.85,61.7) 34.6,61.7 34.866,61.434 U14.18@34.866,60.479
  Signal Layer 2 w0.12: v1(2.3,57.475) 2.775,57 6.875,57 7.253,56.622 9.25,56.622 9.628,57 14.124,57 14.94,57.816 14.94,58.372 16.559,59.991 16.866,59.991 17.04,60.165 31.735,60.165 v1(32.675,59.225) 33.222,59.772 38.656,59.772 39.557,58.87 39.893,58.87 41.034,60.012 44.787,60.012 45.375,60.6 51.275,60.6 v1(51.278,60.603)
  Bottom Layer w0.12: v1(32.675,59.225) 32.675,60.525 v1(33.85,61.7) ; SB54.1@50.675,61.575 50.675,60.8 50.872,60.603 v1(51.278,60.603)
  Bottom Layer w0.127: v1(2.3,57.475) 2.138,57.637 2.138,58.882 1.049,59.97 1.049,82.229 1.531,82.71 3.705,82.71 4.354,83.36 4.354,86.818 3.382,87.79 2.787,87.79 2.138,88.44 2.138,90.33 CN11.9@3.246,91.439
PF7: CN9.26 CN11.11 U14.19 | length 113.4
  Top Layer w0.12: CN9.26@13.406,38.099 14.105,37.4 v1(23.825,37.4) ; v1@34.85,59.1 35.366,59.616 U14.19@35.366,60.479 ; v1@34.85,59.101 v1(34.852,59.103)
  Top Layer w0.127: v1(1.991,36.804) 2.193,36.804 2.38,36.99 12.298,36.99 CN9.26@13.406,38.099
  Bottom Layer w0.12: v1(23.825,37.4) 23.825,40.55 26.305,43.03 26.305,50.169 27.566,51.43 32.223,51.43 33.425,52.632 33.425,57.676 v1(34.852,59.103)
  Bottom Layer w0.127: v1(1.991,36.804) 1.049,37.745 1.049,55.589 2.77,57.31 3.705,57.31 4.354,57.96 4.354,58.878 3.705,59.527 1.842,59.527 1.296,60.073 1.296,82.127 1.633,82.463 3.807,82.463 4.601,83.257 4.601,86.92 3.484,88.037 3.246,88.037 CN11.11@3.246,88.899
PF8: CN9.24 CN11.54 U14.20 | length 48.1
  Top Layer w0.12: v1(34.875,58.45) 34.875,58.5 35.866,59.491 U14.20@35.866,60.479
  Top Layer w0.127: CN9.24@13.406,40.639 24.514,40.639 24.525,40.65 v1(24.55,40.65)
  Signal Layer 2 w0.127: CN11.54@5.786,35.559 6.259,35.559 10.23,39.53 12.298,39.53 CN9.24@13.406,40.639
  Bottom Layer w0.12: 25.735,41.835 26.545,42.645 26.545,50.07 27.665,51.19 32.323,51.19 33.665,52.532 33.665,56.715 34.3,57.35 34.3,57.875 v1(34.875,58.45)
  Bottom Layer w0.127: v1(24.55,40.65) 25.735,41.835
PF9: CN9.28 CN11.56 U14.21 | length 51.9
  Top Layer w0.12: CN11.56@5.786,33.019 7.221,34.454 12.301,34.454 CN9.28@13.406,35.559 23.766,35.559 v1(23.775,35.55) ; v1(34.8,57.8) 35.28,58.28 35.28,58.566 36.366,59.652 U14.21@36.366,60.479
  Bottom Layer w0.12: v1(23.775,35.55) 23.775,36.675 24.25,37.15 24.25,39.777 26.785,42.312 26.785,49.971 27.764,50.95 32.422,50.95 33.905,52.433 33.905,56.616 34.54,57.251 34.54,57.54 v1(34.8,57.8)
PF10: CN12.42 SB60.1 U14.22 | length 73.4
  Top Layer w0.12: v1(19.227,49.427) 19.23,49.425 20.425,49.425 20.427,49.427 v1(27.201,49.427) ; v1(34.7,56.825) 34.7,57.127 35.52,57.947 35.52,58.466 36.528,59.474 36.591,59.474 36.866,59.749 U14.22@36.866,60.479
  Signal Layer 2 w0.12: v1(27.201,49.427) 27.173,49.427 27.165,49.435 55.337,49.435 55.632,49.73 55.968,49.73 56.004,49.694 57.352,49.694 57.61,49.435 65.407,49.435 CN12.42@66.746,50.774
  Bottom Layer w0.12: SB60.1@18.85,56 19.554,55.296 19.554,49.681 19.3,49.427 v1(19.227,49.427) ; v1(27.201,49.427) 27.201,50.048 27.864,50.71 32.521,50.71 34.145,52.334 34.145,56.516 34.454,56.825 v1(34.7,56.825)
PF11: CN12.62 SB65.1 U14.49 | length 100.6
  Top Layer w0.12: v1(18.85,56.85) 23.075,56.85 25.388,54.537 25.388,52.838 27.198,51.028 44.626,51.028 46.797,53.2 v1(47.425,53.2) ; U14.49@45.941,68.554 47.296,68.554 47.3,68.55 v1(47.325,68.55)
  Signal Layer 2 w0.12: v1(49.65,24.4) 62,24.4 62.25,24.15 65.522,24.15 CN12.62@66.746,25.374
  Bottom Layer w0.12: v1(18.85,56.85) SB65.1@18.85,57.625 ; v1@47.325,68.575 v1(47.325,68.55) 47.325,67.35 47.5,67.175 47.5,66.374 47.773,66.1 47.773,64.654 48.15,64.277 48.15,62.979 47.315,62.144 47.315,61.158 47.697,60.776 47.697,56.149 47.367,55.82 47.367,53.258 v1(47.425,53.2) 47.425,44.9 46.375,43.85 46.375,32.122 47.822,30.675 49.225,30.675 49.675,30.225 49.675,24.425 v1(49.65,24.4)
PF12: CN12.59 SB37.1 U14.50 | length 64.5
  Top Layer w0.12: U14.50@45.941,69.054 47.796,69.054 v1(47.9,68.95) 48.28,68.57 49.12,68.57 49.85,69.3 50.775,69.3 50.775,69.281 v1(50.777,69.278) ; v1(47.65,31.6) 58.711,31.6 62.397,27.914 CN12.59@64.206,27.914
  Bottom Layer w0.12: v1(47.65,31.6) 46.615,32.635 46.615,43.751 47.665,44.801 47.665,51.94 48.454,52.729 48.454,54.973 48.02,55.407 48.02,55.743 48.38,56.103 48.38,57.342 49.19,58.152 49.19,60.656 48.73,61.116 48.73,62.357 49.23,62.857 49.23,63.193 48.63,63.792 48.63,64.52 48.325,64.825 48.325,66.575 48.2,66.7 48.2,67.872 48.205,67.877 48.205,68.645 v1(47.9,68.95) ; SB37.1@50.675,70.175 50.675,69.381 v1(50.777,69.278)
PF13: CN12.57 SB49.1 U14.53 | length 63.9
  Top Layer w0.12: U14.53@45.941,70.554 47.329,70.554 v1(47.35,70.575) ; v1(48.175,32.05) 48.35,31.875 58.775,31.875 60.196,30.454 CN12.57@64.206,30.454 ; v1(49.035,64.39) 49.69,64.39 50.678,65.378 v1(51.278,65.378)
  Bottom Layer w0.12: v1(47.35,70.575) 48.545,69.38 48.743,69.38 48.98,69.143 48.98,68.675 48.565,68.26 48.565,64.924 49.035,64.454 v1(49.035,64.39) 49.035,63.727 49.47,63.292 49.47,62.758 48.97,62.258 48.97,61.216 49.43,60.756 49.43,58.053 48.62,57.243 48.62,56.78 48.83,56.57 48.83,55.23 48.694,55.094 48.694,52.63 47.905,51.841 47.905,44.701 46.855,43.651 46.855,33.37 v1(48.175,32.05) ; SB49.1@50.675,64.575 50.675,64.775 v1(51.278,65.378)
PF14: CN12.50 SB50.1 U14.54 | length 60
  Top Layer w0.12: U14.54@45.941,71.054 v1(47.827,71.053) ; v1(47.35,39.5) 47.359,39.509 65.641,39.509 CN12.50@66.746,40.614 ; v1(49.375,62.075) 49.375,62.6 50.278,63.503 v1(51.278,63.503)
  Bottom Layer w0.12: v1(47.35,39.5) 47.242,39.608 47.242,43.699 48.145,44.602 48.145,51.741 48.934,52.53 48.934,54.995 49.07,55.131 49.07,56.495 49.43,56.855 49.43,56.859 49.67,57.099 49.67,60.855 49.32,61.205 49.32,61.733 49.375,61.788 v1(49.375,62.075) 49.4,62.075 49.76,62.435 49.76,64.238 48.805,65.193 48.805,68.161 49.22,68.576 49.22,69.242 48.842,69.62 48.644,69.62 47.827,70.437 v1(47.827,71.053) ; SB50.1@50.675,62.675 50.675,63.225 50.953,63.503 v1(51.278,63.503)
PF15: CN12.60 U14.55 | length 64.6
  Top Layer w0.12: U14.55@45.941,71.554 48.779,71.554 v1(48.95,71.725) ; v1@48.125,43.329 v1(48.127,43.327) ; v1(52.3,29.95) 52.3,29.921 54.971,27.25 62.445,27.25 62.886,26.809 65.641,26.809 CN12.60@66.746,27.914
  Signal Layer 3 w0.12: v1(48.127,43.327) 47.575,43.879 47.575,51.854 48.454,52.733 48.454,55.031 48.83,55.407 48.83,56.307 50.15,57.627 50.15,65.565 49.575,66.14 49.575,71.1 v1(48.95,71.725)
  Bottom Layer w0.12: v1(48.127,43.327) 48.14,43.314 48.14,42.283 48.235,42.188 48.235,38.165 48.9,37.5 48.9,34.225 52.3,30.825 v1(52.3,29.95)
PG0: CN9.29 CN11.59 U14.56 | length 98.8
  Top Layer w0.12: CN11.59@3.246,27.939 4.351,29.044 4.351,31.276 4.989,31.914 6.244,31.914 7.349,33.019 CN9.29@10.866,33.019 ; v1(44.625,69.075) 44.625,71.775 44.904,72.054 U14.56@45.941,72.054
  Signal Layer 2 w0.12: v1(4.8,62.125) 6.183,62.125 6.891,61.417 6.891,60.859 7.575,60.175 v1(9.775,60.175) ; v1(4.925,67.603) 5.055,67.474 7.349,67.474 8.7,68.825 8.7,69.836 10.046,71.182 17.854,71.182 20.353,68.683 23.517,68.683 24.067,69.233 31.994,69.233 32.807,68.42 33.145,68.42 33.795,69.07 41.668,69.07 41.673,69.075 v1(44.625,69.075)
  Bottom Layer w0.12: v1(4.8,62.125) 4.681,62.244 4.681,67.356 4.925,67.6 v1(4.925,67.603) ; v1(9.775,60.175) 9.556,59.956 9.556,58.499 9.741,58.314 9.741,57.113 9.291,56.663 9.291,34.594 CN9.29@10.866,33.019
PG1: CN9.30 CN11.58 U14.57 | length 107.8
  Top Layer w0.12: v1(2.425,64.503) 2.378,64.503 1.796,63.922 1.796,60.746 2.396,60.147 2.396,59.811 1.796,59.212 1.796,55.697 2.38,55.114 2.38,54.06 1.925,53.605 1.925,52.425 v1(2.45,51.9) ; CN11.58@5.786,30.479 7.221,31.914 12.301,31.914 CN9.30@13.406,33.019 ; v1(44.227,68.528) 44.22,68.536 44.22,69.335 44.385,69.5 44.385,71.96 44.979,72.554 U14.57@45.941,72.554
  Signal Layer 2 w0.12: v1(2.425,64.503) 2.425,65.297 2.141,65.581 2.141,66.497 2.794,67.15 7.364,67.15 8.94,68.726 8.94,69.736 10.145,70.942 17.755,70.942 20.253,68.443 23.616,68.443 24.166,68.993 31.895,68.993 32.708,68.18 33.244,68.18 33.894,68.83 43.927,68.83 v1(44.227,68.528) ; v1(2.45,51.9) 2.454,51.904 4.012,51.904 4.273,52.165 8.715,52.165 v1(8.875,52.325)
  Signal Layer 3 w0.12: v1(44.227,68.528) v1@44.249,68.55
  Bottom Layer w0.12: v1(8.875,52.325) 8.875,52.35 9.051,52.174 9.051,33.271 10.408,31.914 12.301,31.914 CN9.30@13.406,33.019
PG2: CN8.14 CN11.42 U14.87 | length 63.1
  Top Layer w0.12: CN11.42@5.786,50.799 6.976,50.799 7.3,50.475 7.423,50.475 v1(7.425,50.477) ; v1(9.125,75.475) 10.027,75.475 10.408,75.094 11.344,75.094 12.449,76.199 CN8.14@13.406,76.199 ; v1(14.876,81.154) v1@14.876,81.201 ; U14.87@36.866,82.129 36.866,83.191 37,83.325 v1(37.025,83.325)
  Signal Layer 2 w0.12: v1(7.425,50.477) v1@7.425,50.5 ; v1@14.876,81.174 v1(14.876,81.154) 15.307,81.585 34.949,81.585 36.27,82.905 36.605,82.905 v1(37.025,83.325)
  Bottom Layer w0.12: v1(7.425,50.477) 7.425,50.951 7.636,51.161 7.636,52.826 7.971,53.161 7.971,53.394 8.571,53.994 8.571,56.961 9.021,57.411 9.021,57.984 8.836,58.169 8.836,61.262 9.211,61.637 9.211,62.171 8.836,62.546 8.836,64.256 9.326,64.746 9.326,72.351 8.973,72.704 8.973,75.323 v1(9.125,75.475) ; CN8.14@13.406,76.199 14.511,77.304 14.511,80.789 v1(14.876,81.154)
PG3: CN8.16 CN11.44 U14.88 | length 64.6
  Top Layer w0.12: CN11.44@5.786,48.259 v1(7.591,48.259) ; v1(9.5,72.75) 9.696,72.554 11.324,72.554 12.429,73.659 CN8.16@13.406,73.659 ; v1(36.35,83.325) 36.366,83.309 U14.88@36.366,82.129
  Signal Layer 2 w0.12: v1(14.925,81.825) 34.85,81.825 v1(36.35,83.325)
  Bottom Layer w0.12: v1(7.591,48.259) 7.411,48.439 7.411,49.89 7.876,50.355 7.876,52.727 8.211,53.062 8.211,53.295 8.811,53.895 8.811,56.862 9.261,57.312 9.261,58.083 9.076,58.268 9.076,61.162 9.451,61.537 9.451,62.27 9.076,62.645 9.076,64.156 9.566,64.646 9.566,72.526 9.475,72.617 9.475,72.75 v1(9.5,72.75) ; CN8.16@13.406,73.659 13.406,74.636 14.751,75.981 14.751,80.426 15.281,80.956 15.281,81.322 14.925,81.677 v1(14.925,81.825)
PG4: CN12.69 U14.89 | length 94.5
  Top Layer w0.12: U14.89@35.866,82.129 35.866,79.866 37.127,78.605 44.028,78.605 v1(44.752,79.329) ; v1(52.35,27.775) 53.428,27.775 54.673,26.53 62.147,26.53 62.861,25.816 62.861,22.45 63.913,21.399 64.951,21.399 65.311,21.039 65.311,16.319 CN12.69@64.206,15.214
  Signal Layer 3 w0.12: v1(44.752,79.329) 44.752,77.696 47.318,75.13 48.349,75.13 49.695,73.784 49.695,72.434 50.295,71.834 50.295,66.438 50.87,65.863 50.87,57.329 49.55,56.009 49.55,55.109 49.174,54.733 49.174,52.435 48.295,51.556 48.295,44.991 49.532,43.753 49.532,43.157 v1(49.025,42.65)
  Bottom Layer w0.12: v1(49.025,42.65) 49.025,38.393 49.62,37.798 49.62,34.523 53.185,30.958 53.185,28.61 v1(52.35,27.775)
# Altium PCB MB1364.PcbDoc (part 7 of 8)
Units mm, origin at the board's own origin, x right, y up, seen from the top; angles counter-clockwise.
Board outline 70 x 133.34 mm, 6 copper layers (Top Layer, Signal Layer 1, Signal Layer 2, Signal Layer 3, Signal Layer 4, Bottom Layer), stack 1.57 mm thick; 321 components, 287 nets, 1372 pads, 2051 vias.

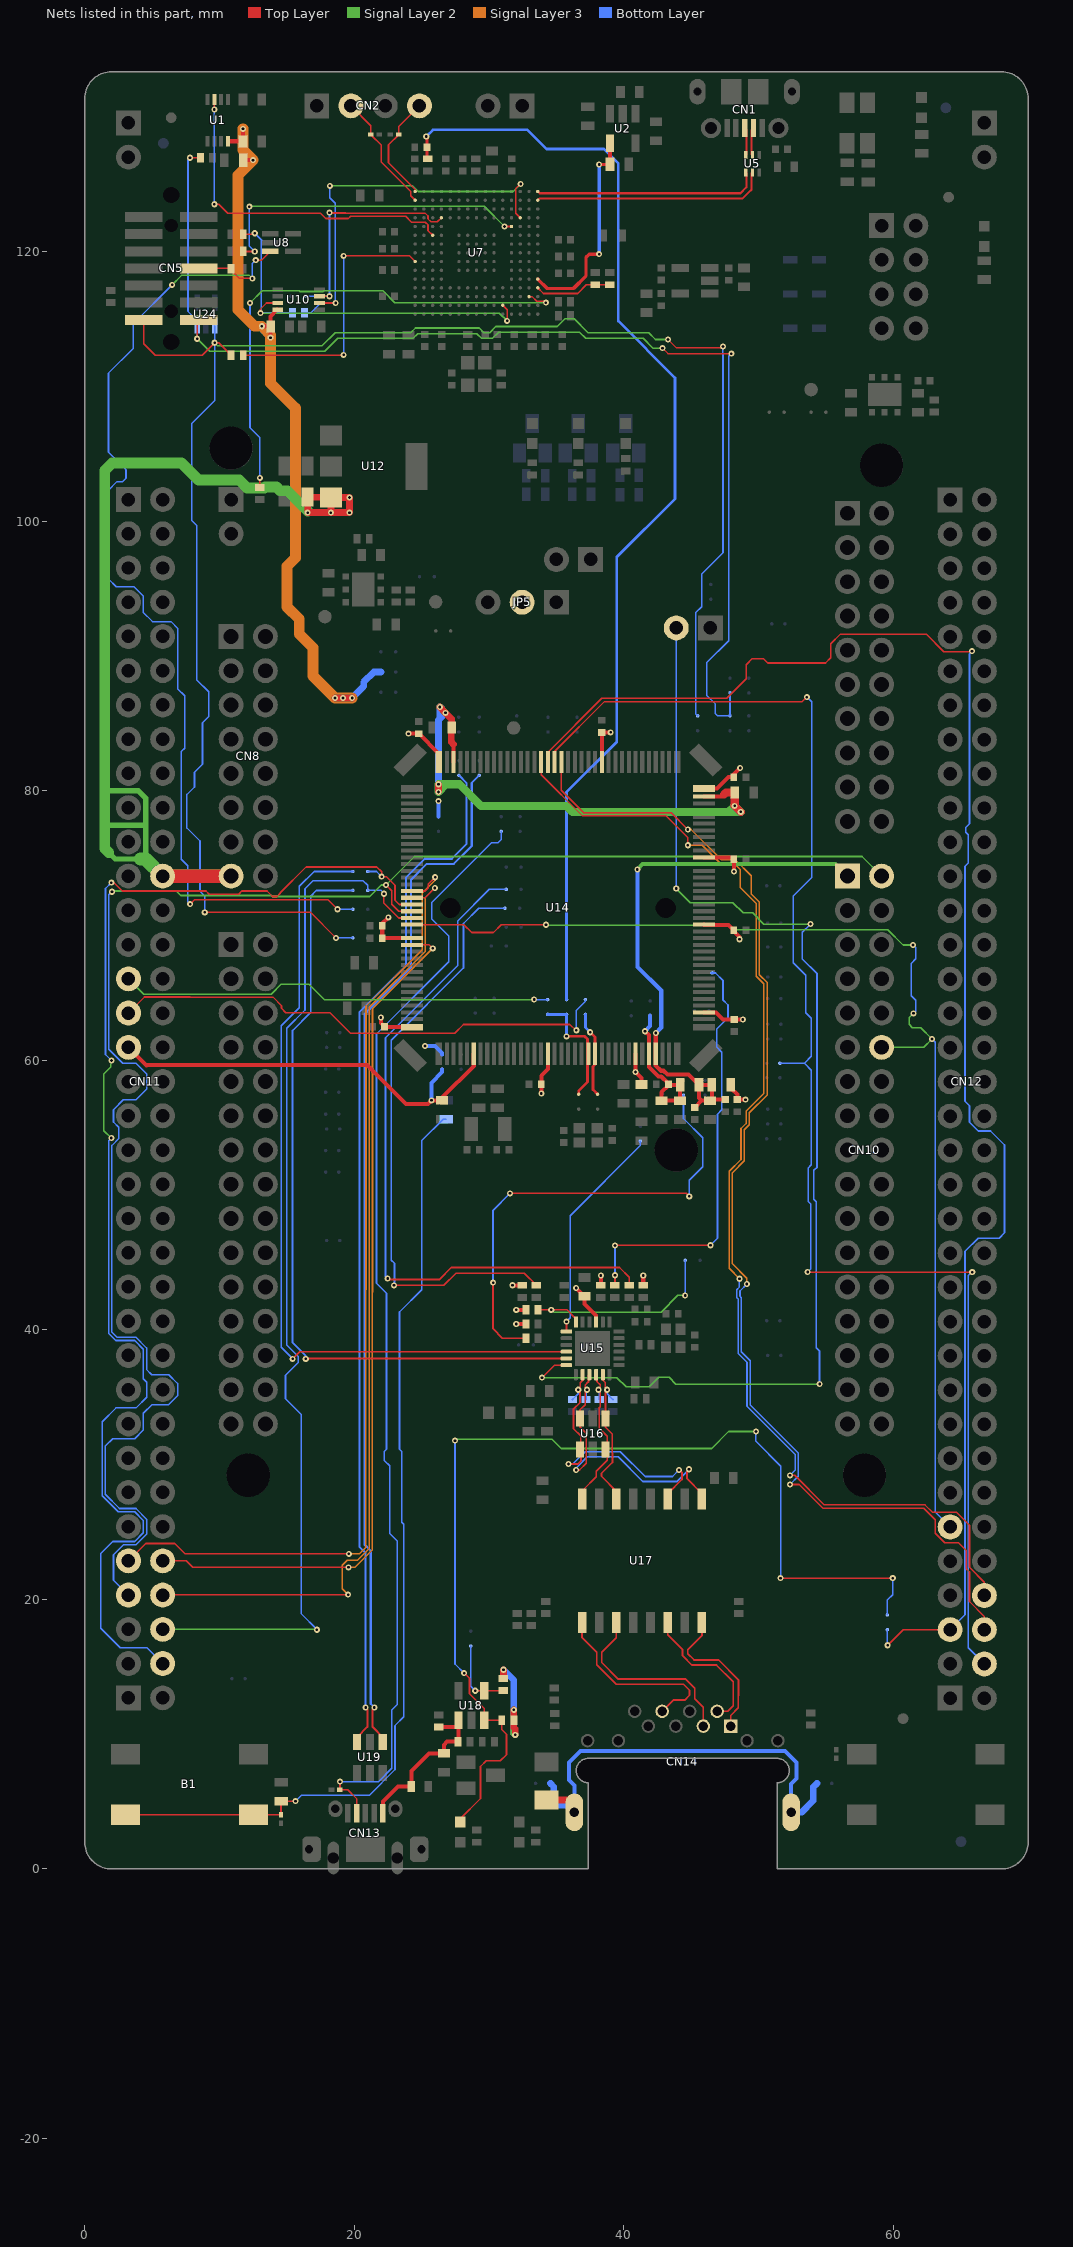
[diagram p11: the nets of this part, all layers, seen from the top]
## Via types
v1: diameter 0.45, hole 0.2, Top Layer to Bottom Layer, tented both sides, 1975 vias
v2: diameter 0.45, hole 0.2, Top Layer to Bottom Layer, tented top, 67 vias
v3: diameter 0.6, hole 0.3, Top Layer to Bottom Layer, tented both sides, 9 vias

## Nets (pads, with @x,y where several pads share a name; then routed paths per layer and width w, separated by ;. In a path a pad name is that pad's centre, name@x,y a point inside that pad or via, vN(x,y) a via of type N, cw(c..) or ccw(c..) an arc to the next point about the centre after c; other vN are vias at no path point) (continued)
PG5: CN12.68 U14.90 | length 90.4
  Top Layer w0.12: U14.90@35.366,82.129 35.366,80.027 37.028,78.365 43.51,78.365 v1(44.75,77.125) ; v1@49.125,43.405 v1(49.127,43.402) ; v1(52.325,28.525) 53.017,28.525 54.772,26.77 62.246,26.77 63.101,25.915 63.101,24.916 63.817,24.2 64.825,24.2 65.401,23.624 65.401,22.277 65.641,22.037 65.641,19.836 66.746,18.731 CN12.68@66.746,17.754
  Signal Layer 3 w0.12: v1(44.75,77.125) 44.983,77.125 47.218,74.89 48.249,74.89 49.455,73.684 49.455,72.334 50.055,71.734 50.055,66.339 50.63,65.764 50.63,57.428 49.31,56.108 49.31,55.208 48.934,54.833 48.934,52.534 48.055,51.655 48.055,44.891 49.127,43.819 v1(49.127,43.402)
  Bottom Layer w0.12: v1(49.127,43.402) 49.127,43.388 48.62,42.881 48.62,42.482 48.715,42.387 48.715,38.364 49.38,37.699 49.38,34.424 52.945,30.859 52.945,29.145 v1(52.325,28.525)
PG6: CN12.70 SB59.1 U14.91 | length 109.6
  Top Layer w0.12: U14.91@34.866,82.129 34.866,82.914 38.562,86.61 53.245,86.61 v1(53.575,86.94) ; v1(53.634,44.284) 65.841,44.284 v1(65.85,44.275)
  Bottom Layer w0.12: SB59.1@51.575,59.775 53.4,59.775 ; v1(53.575,86.94) 53.585,86.94 53.93,86.595 53.93,83.631 53.953,83.608 53.953,73.568 52.576,72.191 52.576,67.232 53.495,66.312 53.495,63.525 53.914,63.106 53.914,60.289 53.4,59.775 ; v1(53.634,44.284) 53.858,44.508 53.858,49.337 53.674,49.521 53.674,52.005 53.914,52.245 53.914,59.261 53.4,59.775 ; v1(65.85,44.275) 65.825,44.3 65.551,44.026 65.551,16.409 CN12.70@66.746,15.214
PG7: CN12.67 SB76.2 U14.92 | length 121.5
  Top Layer w0.12: U14.92@34.366,82.129 34.366,82.858 38.358,86.85 47.625,86.85 49.075,88.3 49.075,89.35 49.525,89.8 50.338,89.8 50.67,89.468 54.968,89.468 55.35,89.85 55.35,90.894 56.074,91.618 62.432,91.618 63.741,90.309 65.784,90.309 v1(65.825,90.35) ; v1(59.575,16.6) 60.729,17.754 CN12.67@64.206,17.754
  Bottom Layer w0.12: SB76.2@59.55,17.75 59.55,16.575 v1(59.575,16.6) ; CN12.67@64.206,17.754 65.311,18.859 65.311,45.822 66.288,46.799 67.849,46.799 68.241,47.191 68.241,53.707 67.2,54.749 66.288,54.749 65.641,55.396 65.641,56.619 65.311,56.949 65.311,74.399 65.551,74.639 65.551,76.731 65.37,76.912 65.37,77.268 65.641,77.539 65.641,90.166 v1(65.825,90.35)
PG8: CN12.66 U14.93 | length 88.6
  Top Layer w0.12: U14.93@33.866,82.129 33.866,81.187 36.928,78.125 43.15,78.125 44.75,76.525 v1(44.75,75.95) ; v1(52.325,29.2) 52.682,29.2 54.872,27.01 62.346,27.01 62.877,26.479 64.664,26.479 65.641,25.502 65.641,22.376 66.746,21.271 CN12.66@66.746,20.294
  Signal Layer 3 w0.12: v1(44.75,75.95) 45.819,75.95 47.119,74.65 48.15,74.65 48.625,74.175 48.625,72.825 49.815,71.635 49.815,66.239 50.39,65.664 50.39,57.528 49.07,56.208 49.07,55.308 48.694,54.932 48.694,52.634 47.815,51.754 47.815,44.559 v1(48.587,43.787)
  Bottom Layer w0.12: v1(48.587,43.787) 48.575,43.775 48.575,43.175 48.38,42.98 48.38,42.383 48.475,42.288 48.475,38.264 49.14,37.599 49.14,34.324 52.705,30.759 52.705,29.58 v1(52.325,29.2)
PG9: CN11.63 U14.124 | length 72.8
  Top Layer w0.12: CN11.63@3.246,22.859 4.537,24.15 6.675,24.15 7.45,23.375 v1(19.6,23.375) ; U14.124@24.291,72.554 25.275,72.554 25.496,72.775 25.496,73.071 v1(26,73.575)
  Signal Layer 3 w0.12: v1(19.6,23.375) 20.371,23.375 20.865,23.869 20.865,42.967 20.87,42.972 20.87,64.024 25.04,68.194 25.04,72.413 26,73.373 v1(26,73.575)
PG10: CN11.66 U14.125 | length 71.7
  Top Layer w0.12: CN11.66@5.786,20.319 5.817,20.35 v1(19.55,20.35) ; U14.125@24.291,72.054 25.254,72.054 v1(25.975,72.775)
  Signal Layer 3 w0.12: v1(19.55,20.35) 19.1,20.8 19.1,22.525 19.475,22.9 20.236,22.9 21.105,23.769 21.105,42.867 21.11,42.872 21.11,63.924 25.28,68.095 25.28,72.08 v1(25.975,72.775)
PG11: CN11.70 SB27.2 U14.126 | length 97.4
  Top Layer w0.12: v1(1.975,73.175) 2.167,73.175 2.788,72.554 8.996,72.554 9.236,72.314 11.423,72.314 11.663,72.554 13.528,72.554 13.933,72.149 14.268,72.149 14.506,72.386 14.506,72.415 16.424,74.334 21.677,74.334 22.032,73.978 v1(22.032,73.618) 22.393,73.618 23.025,72.986 23.025,71.875 23.346,71.554 U14.126@24.291,71.554
  Signal Layer 2 w0.12: v1(1.975,54.228) 1.425,54.778 1.425,58.986 1.941,59.502 1.941,59.93 v1(1.991,59.979)
  Bottom Layer w0.12: v1(1.975,54.228) 1.78,54.033 1.78,39.729 2.305,39.204 3.704,39.204 4.351,38.557 4.351,36.366 4.598,36.119 4.598,34.999 3.806,34.207 2.316,34.207 1.293,33.184 1.293,27.696 2.485,26.504 3.704,26.504 4.351,25.857 4.351,24.941 3.704,24.294 2.081,24.294 1.191,23.404 1.191,17.854 2.641,16.404 4.621,16.404 CN11.70@5.786,15.239 ; v1(1.975,73.175) 1.54,72.74 1.54,60.43 v1(1.991,59.979) ; SB27.2@21,74 21.65,74 v1(22.032,73.618)
PG12: CN10.2 CN11.65 U14.127 | length 129.9
  Top Layer w0.12: v1(22.35,73) 22.785,72.565 22.785,71.565 23.296,71.054 U14.127@24.291,71.054
  Signal Layer 2 w0.12: v1(2.025,72.5) 2.079,72.554 6.786,72.554 7.119,72.22 13.861,72.22 13.933,72.149 21.149,72.149 22,73 v1(22.35,73) 24.465,75.115 57.67,75.115 CN10.2@59.126,73.659
  Bottom Layer w0.12: v1(2.025,72.5) 2,72.5 1.78,72.28 1.78,60.82 2.829,59.771 3.806,59.771 4.598,58.979 4.598,57.859 3.806,57.067 2.871,57.067 2.141,56.337 2.141,55.421 2.535,55.027 2.535,54.19 2.02,53.676 2.02,39.828 2.404,39.444 3.803,39.444 4.591,38.656 4.591,37.059 4.986,36.664 6.244,36.664 6.891,36.017 6.891,35.101 6.244,34.454 5.004,34.454 4.351,33.801 4.351,32.561 3.704,31.914 2.072,31.914 1.533,31.375 1.533,27.796 2.585,26.744 3.803,26.744 4.591,25.956 4.591,24.842 3.803,24.054 2.878,24.054 2.141,23.317 2.141,21.424 CN11.65@3.246,20.319
PG13: CN11.68 SB30.2 U14.128 | length 78.7
  Top Layer w0.12: v1(22.2,72.35) 22.2,71.65 23.296,70.554 U14.128@24.291,70.554
  Signal Layer 2 w0.12: CN11.68@5.786,17.779 v1@17.225,17.779
  Bottom Layer w0.12: v1(17.225,17.75) 17.225,17.779 16.08,18.924 16.08,33.695 14.9,34.875 14.9,36.625 15.848,37.573 15.848,38.025 14.998,38.875 14.998,62.375 16.348,63.725 16.348,72.726 16.942,73.32 20.655,73.32 21,72.975 SB30.2@21,72.6 22,72.6 22.225,72.375 v1(22.2,72.35)
PG14: CN10.12 CN12.61 U14.129 | length 87.7
  Top Layer w0.12: U14.129@24.291,70.054 28.129,70.054 28.71,69.473 30.323,69.473 30.904,70.054 v1(34.225,70.054)
  Signal Layer 2 w0.12: v1(34.225,70.054) 34.265,70.014 47.8,70.014 48.13,69.684 59.584,69.684 60.718,68.55 v1(61.45,68.55)
  Signal Layer 2 w0.127: CN10.12@59.126,60.959 62.246,60.959 v1(62.866,61.579) 62.025,62.42 61.409,62.42 61.17,62.659 61.17,63.17 61.478,63.478 v1(61.496,63.478)
  Signal Layer 3 w0.127: v1(61.496,63.478) v1@61.553,63.478
  Bottom Layer w0.12: v1(61.45,68.55) 61.475,68.55 61.661,68.364 61.661,67.524 61.32,67.183 61.32,64.784 61.661,64.443 61.661,63.643 v1(61.496,63.478)
  Bottom Layer w0.127: v1(62.866,61.579) 63.098,61.347 63.098,26.482 CN12.61@64.206,25.374
PG15: CN11.64 U14.132 | length 64.4
  Top Layer w0.12: CN11.64@5.786,22.859 7.541,22.859 8.025,22.375 v1(19.575,22.375) ; U14.132@24.291,68.554 25.571,68.554 v1(25.825,68.3)
  Signal Layer 3 w0.12: v1(19.575,22.375) 20.05,22.375 21.345,23.67 21.345,42.768 21.35,42.773 21.35,63.825 v1(25.825,68.3)
PH0: CN11.29 SB46.2 | length 32.4
  Signal Layer 2 w0.12: CN11.29@3.246,66.039 4.386,64.899 8.234,64.899 13.835,64.9 14.585,65.65 16.625,65.65 17.776,64.499 v1(33.35,64.499)
  Bottom Layer w0.12: v1(33.35,64.499) 34.349,64.499 SB46.2@34.35,64.5
PH0-OSC_IN: SB3.1 SB45.1 SB46.1 U14.23 | length 9
  Top Layer w0.2: v1(35.75,61.775) 37.1,61.775 37.305,61.57 37.305,58.38 36.65,57.725 SB3.1@36.65,57.475
  Bottom Layer w0.2: SB46.1@34.35,63.4 SB45.1@35.75,63.4 v1(35.75,61.775)
PH1: CN11.31 SB44.2 | length 38
  Top Layer w0.12: CN11.31@3.246,63.499 4.441,64.694 7.835,64.694 7.842,64.687 13.963,64.687 14.6,64.05 14.6,63.85 14.925,63.525 18.2,63.525 19.724,62.001 27.45,62.001 28.104,62.655 35.995,62.655 36.45,62.2 v1(36.475,62.225)
  Bottom Layer w0.12: v1(36.475,62.225) 36.47,62.23 36.47,63.695 37.15,64.375 SB44.2@37.15,64.5
PH1-OSC_OUT: SB4.1 SB44.1 U14.24 | length 6.4
  Top Layer w0.2: v1(37.5,62.075) 37.866,61.709 U14.24@37.866,60.479 37.866,59.693 37.705,59.532 37.705,57.82 SB4.1@38.05,57.475
  Bottom Layer w0.2: SB44.1@37.15,63.4 37.15,62.425 v1(37.5,62.075)
RD_N: R76.1 U15.22 U16.6 U17.8 | length 11.5
  Top Layer w0.11: 38.166,32.705 38.166,34.204
  Top Layer w0.13: U17.8@36.901,27.434 36.966,27.499 36.966,28.116 37.959,29.109 37.959,29.509 38.766,30.316 38.766,31.004 U16.6@38.641,31.129 38.766,31.254 38.766,32.105 38.166,32.705 ; U15.22@37.941,36.679 38.009,36.611 38.009,36.161 38.241,35.929 38.241,35.679 v1(38.116,35.554) 38.25,35.42 38.25,34.288 38.166,34.204
  Bottom Layer w0.13: R76.1@38.191,34.829 38.191,35.479 v1(38.116,35.554) v1@38.25,35.554
RD_P: R75.1 U15.23 U16.1 U17.6 | length 11.4
  Top Layer w0.13: U15.23@38.441,36.679 38.391,36.629 38.391,36.319 38.623,36.087 38.623,35.697 v1(38.766,35.554) 38.632,35.42 38.632,33.438 U16.1@38.641,33.429 38.641,32.781 39.148,32.274 39.148,30.85 ; 39.15,30.85 39.15,30.16 38.341,29.351 38.341,29.134 39.441,28.034 U17.6@39.441,27.434
  Bottom Layer w0.13: v1(38.766,35.554) 38.766,35.254 R75.1@39.191,34.829
RMII_CRS_DV: R41.1 SB31.2 | length 44
  Top Layer w0.127: v1(22.95,43.3) 26.65,43.3 27.55,44.2 32.62,44.2 R41.1@33.516,43.304
  Bottom Layer w0.127: v1(22.95,43.3) 22.984,43.334 22.984,44.927 22.74,45.17 22.74,61.488 28.102,66.849 28.102,70.148 29.229,71.275 SB31.2@31.175,71.275
RMII_MDC: SB64.1 U15.13 | length 16.4
  Top Layer w0.127: U15.13@35.741,39.879 v1(35.741,40.604)
  Bottom Layer w0.127: v1(35.741,40.604) 36.025,40.888 36.025,48.47 41.225,53.67 SB64.1@41.225,54
RMII_MDIO: R47.1 SB72.2 U15.12 | length 16.4
  Top Layer w0.127: R47.1@33.641,41.479 v1(34.616,41.479) 35.787,41.479 36.441,40.825 U15.12@36.441,40.579
  Signal Layer 2 w0.102: v1(34.616,41.479) 34.775,41.32 42.758,41.32 43.987,42.55 v1(44.55,42.55)
  Bottom Layer w0.127: v1(44.55,42.55) 44.556,42.556 SB72.2@44.556,45.156
RMII_REF_CLK: R49.1 SB57.2 | length 35.2
  Top Layer w0.127: v1(30.3,43.5) 30.3,40.069 30.99,39.379 R49.1@32.741,39.379 ; v1(31.55,50.125) 44.625,50.125 v1(44.85,49.9)
  Bottom Layer w0.127: v1(30.3,43.5) 30.3,48.875 v1(31.55,50.125) ; SB57.2@44.425,57.4 44.425,55.675 45.85,54.25 45.85,52.1 44.85,51.1 v1(44.85,49.9)
RMII_RXD0: R44.1 SB36.1 | length 31.8
  Top Layer w0.127: R44.1@39.341,43.304 39.35,43.313 v1(39.35,44.05) ; v1(39.35,46.25) 39.375,46.275 v1(46.425,46.275)
  Bottom Layer w0.127: v1(39.35,44.05) v1(39.35,46.25) ; v1(46.425,46.275) 46.944,46.794 46.944,55.995 47.273,56.325 47.273,60.601 46.892,60.983 46.892,62.319 47.727,63.155 47.727,64.102 47.35,64.479 47.35,65.925 46.8,66.475 SB36.1@46.55,66.475 SB36.1@46.5,66.475
RMII_RXD1: R45.1 SB29.1 | length 52.8
  Top Layer w0.127: v1(22.475,43.8) 22.548,43.727 26.302,43.727 27.202,44.627 39.673,44.627 40.391,43.909 R45.1@40.391,43.304
  Bottom Layer w0.127: v1@22.475,43.95 v1(22.475,43.8) 22.313,43.961 22.313,61.665 27.675,67.026 27.675,70.325 30.025,72.675 SB29.1@31.275,72.675
RMII_TX_EN: SB27.1 U15.16 | length 60.9
  Top Layer w0.127: v1(15.425,37.85) 15.954,38.379 U15.16@35.741,38.379
  Bottom Layer w0.127: v1(15.425,37.85) 14.575,38.7 14.575,62.55 15.925,63.9 15.925,72.902 17.023,74 SB27.1@19.9,74
RMII_TXD0: SB30.1 U15.17 | length 57.9
  Top Layer w0.127: v1(16.4,37.85) 16.429,37.879 U15.17@35.741,37.879
  Bottom Layer w0.127: v1(16.4,37.85) 16.4,38.073 15.424,39.049 15.424,45.576 15.422,45.578 15.422,62.199 16.772,63.549 16.772,72.175 17.197,72.6 SB30.1@19.9,72.6
RMII_TXD1: JP6.2 U15.18 | length 89.1
  Top Layer w0.127: v1(33.925,36.45) 34.854,37.379 U15.18@35.741,37.379
  Signal Layer 2 w0.102: v1(33.925,36.45) 39.488,36.45 40.163,35.775 41.895,35.775 42.595,36.475 43.35,36.475 43.85,35.975 v1(54.525,35.975) ; v1(43.886,72.736) 44.922,71.7 48.075,71.7 48.846,70.929 49.553,70.929 50.383,70.1 v1(53.85,70.1)
  Bottom Layer w0.127: v1(43.886,72.736) JP6.2@43.886,92.074 ; v1(53.85,70.1) 53.246,69.496 53.246,67.509 54.338,66.418 54.338,52.07 54.098,51.83 54.098,49.696 54.282,49.512 54.282,38.657 54.522,38.417 54.522,35.978 v1(54.525,35.975)
RX_N: CN14.6 U17.9 | length 14.1
  Top Layer w0.13: U17.9@36.901,18.284 36.901,17.149 37.984,16.066 37.984,15.161 39.441,13.704 44.426,13.704 44.871,13.259 44.871,12.884 44.516,12.529 43.668,12.529 CN14.6@42.839,11.7
RX_P: CN14.3 U17.11 | length 14.2
  Top Layer w0.13: U17.11@39.441,18.284 39.441,17.141 38.366,16.066 38.366,15.319 39.599,14.086 44.584,14.086 45.253,13.417 45.253,12.642 45.899,11.996 CN14.3@45.899,10.6
SHGND: C85.1 CN14.SH1 CN14.SH2 SB78.1 SB79.1 | length 35.1
  Top Layer w0.5: C85.1@34.25,5.125 36.444,5.125 36.329,5.01 CN14.SH2@36.329,4.2
  Bottom Layer w0.3: CN14.SH2@36.329,4.2 36.329,6.196 35.919,6.606 35.919,7.894 36.774,8.75 51.963,8.75 52.819,7.894 52.819,6.705 52.409,6.295 CN14.SH1@52.409,4.2
  Bottom Layer w0.5: SB79.1@34.55,6.35 34.8,6.1 34.8,5.2 35.25,4.75 35.778,4.75 CN14.SH2@36.329,4.2 ; CN14.SH1@52.409,4.2 53.175,4.2 54.05,5.075 54.05,6.075 SB78.1@54.325,6.35
STLK_MCO: C5.2 R5.2 SB45.2 | length 84.3
  Top Layer w0.2: v1(25.341,128.529) 25.391,128.479 C5.2@25.391,127.729 25.391,126.954 R5.2@25.466,126.879
  Bottom Layer w0.2: v1(25.341,128.529) 25.841,129.029 32.841,129.029 34.266,127.604 38.516,127.604 39.591,126.529 39.591,114.829 43.791,110.629 43.791,101.654 39.475,97.338 39.475,83.625 35.75,79.9 SB45.2@35.75,64.5
STLK_SWCLK: CN2.2 U3.1 U7.A14 | length 9
  Top Layer w0.12: CN2.2@19.756,130.809 21.229,129.336 U3.1@21.229,128.679 21.229,128.672 22.016,127.884 22.016,126.615 24.184,124.447 24.184,124.136 U7.A14@24.516,123.804
STLK_SWDIO: CN2.4 U4.1 U7.A15 | length 8.1
  Top Layer w0.12: U7.A15@24.516,124.454 24.516,124.604 22.541,126.579 22.541,127.909 23.303,128.672 U4.1@23.303,128.679 23.303,129.276 CN2.4@24.836,130.809
STLK_VCP_RX: U1.3 U7.C10 | length 25.3
  Top Layer w0.12: v1(9.616,123.504) 9.941,123.504 10.616,122.829 17.491,122.829 17.876,122.444 19.566,122.444 19.731,122.609 23.811,122.609 24.241,122.179 25.272,122.179 25.471,121.98 25.471,121.549 U7.C10@25.816,121.204 ; v1(9.616,130.529) U1.3@9.616,131.279
  Bottom Layer w0.12: v1(9.616,123.504) v1(9.616,130.529)
STLK_VCP_TX: R23.1 U7.A7 | length 20.3
  Top Layer w0.12: R23.1@11.766,112.304 19.191,112.304 v1(19.216,112.329) ; v1(19.216,119.679) 24.091,119.679 U7.A7@24.516,119.254
  Bottom Layer w0.12: v1(19.216,112.329) v1(19.216,119.679)
T_NRSTa: R29.1 U7.P3 | length 38.1
  Top Layer w0.12: R29.1@12.991,102.504 v1(12.991,103.204) ; U7.P3@32.966,116.654 33.185,116.654 33.53,116.309 34.111,116.309 v1(34.216,116.204)
  Signal Layer 2 w0.12: v1(12.266,116.179) 13.171,117.084 15.922,117.084 15.972,117.034 17.683,117.034 17.733,117.084 22.134,117.084 23.014,116.204 v1(34.216,116.204)
  Bottom Layer w0.12: v1(12.266,116.179) 12.266,106.929 12.991,106.204 v1(12.991,103.204)
T_PWR_EN: R7.1 U2.4 U7.R5 | length 15.7
  Top Layer w0.25: U7.R5@33.616,117.954 34.316,117.254 36.266,117.254 37.191,118.179 37.191,119.554 37.441,119.804 v1(38.166,119.804) ; v1(38.166,126.454) 38.969,126.454 R7.1@38.973,126.459
  Top Layer w0.3: U2.4@38.966,128.014 38.973,128.006 R7.1@38.973,126.459
  Bottom Layer w0.25: v1(38.166,119.804) v1(38.166,126.454)
T_PWR_EXT: R14.2 R15.2 U7.R4 | length 5.8
  Top Layer w0.12: U7.R4@33.616,117.304 34.036,116.884 36.571,116.884 37.216,117.529 R14.2@37.891,117.529 R15.2@38.941,117.529
T_SWCLKa: R11.1 U7.M11 | length 24.4
  Top Layer w0.12: R11.1@11.766,120.004 v1(12.616,120.004) ; v1(31.141,121.854) U7.M11@31.666,121.854
  Signal Layer 2 w0.12: v1(12.216,123.329) 12.241,123.354 29.641,123.354 v1(31.141,121.854)
  Bottom Layer w0.12: v1(12.216,123.329) 12.216,121.552 12.211,121.547 12.211,120.409 v1(12.616,120.004)
T_SWDIO_IN: R67.2 U7.N12 U10.2 | length 30
  Top Layer w0.12: U10.2@17.416,116.179 v1(18.616,116.179) ; U7.N12@32.316,122.504 31.991,122.829 31.991,124.679 32.316,125.004 v1(32.341,125.004)
  Signal Layer 2 w0.12: v1(18.186,124.874) 24.321,124.874 24.741,124.454 31.791,124.454 v1(32.341,125.004)
  Bottom Layer w0.12: R67.2@16.316,115.454 16.791,115.454 17.516,116.179 v1(18.616,116.179) 18.591,116.204 18.591,123.581 18.186,123.986 v1(18.186,124.874)
T_SWDIOa: R10.2 R67.1 U7.L2 U10.7 | length 31
  Top Layer w0.12: R10.2@11.766,121.279 12.616,121.279 v1(12.616,121.354) ; v1(13.041,115.429) 13.041,115.729 13.491,116.179 U10.7@14.316,116.179 ; U7.L2@31.016,116.004 31.341,115.679 v1(31.341,114.854)
  Signal Layer 2 w0.12: v1(13.041,115.429) 30.766,115.429 v1(31.341,114.854)
  Bottom Layer w0.12: v1(12.616,121.354) 13.141,120.829 13.096,120.784 13.096,115.484 v1@13.066,115.454 ; v1(13.041,115.429) v1@13.066,115.454 ; R67.1@15.416,115.454 v1@13.066,115.454
T_SWO: CN5.8 R13.1 SB32.1 U8.3 | length 79.5
  Top Layer w0.12: v1(7.825,71.575) 8.149,71.899 18.051,71.899 v1(18.75,71.2) ; CN5.8@8.453,118.744 10.851,118.744 R13.1@10.866,118.729 10.866,118.629 11.491,118.004 v1(12.441,118.004) ; v1(12.691,119.354) 13.116,119.354 U8.3@13.766,120.004
  Signal Layer 2 w0.12: v1(6.491,117.529) 7.186,118.224 12.221,118.224 v1(12.441,118.004)
  Bottom Layer w0.12: v1(6.491,117.529) 3.616,114.654 3.616,112.829 1.766,110.979 1.766,105.104 3.066,103.804 3.066,103.179 2.816,102.929 2.403,102.929 1.766,102.292 1.766,95.704 2.341,95.129 3.659,95.129 4.351,94.437 4.351,93.219 5.026,92.544 6.401,92.544 6.891,92.054 6.891,87.555 7.413,87.033 7.413,83.145 7.166,82.898 7.166,74.919 7.653,74.432 7.653,71.747 v1(7.825,71.575) ; v1(12.441,118.004) 12.441,119.104 v1(12.691,119.354) ; v1(18.75,71.2) SB32.1@19.9,71.2
T_SWOa: SB5.1 U7.D12 U10.3 | length 17.6
  Top Layer w0.12: U10.3@17.416,116.679 v1(18.166,116.679) ; v1(18.166,122.879) 18.191,122.854 19.366,122.854 ; 19.366,122.849 25.252,122.849 25.471,122.63 25.471,122.418 25.69,122.199 26.161,122.199 U7.D12@26.466,122.504
  Bottom Layer w0.12: SB5.1@16.391,116.679 v1(18.166,116.679) v1(18.166,122.879)
T_VCP_RX: CN5.13 R23.2 SB12.2 SB34.1 U24.1 | length 135.3
  Top Layer w0.12: CN5.13@4.389,114.934 4.389,113.156 5.241,112.304 8.716,112.304 v1(9.641,113.229) 9.941,113.229 R23.2@10.866,112.304 ; v1(8.906,70.975) 16.75,70.975 v1(18.65,69.075) ; v1(43.275,113.475) 43.905,112.845 47.245,112.845 v1(47.35,112.95)
  Signal Layer 2 w0.12: v1(9.641,113.229) 9.851,113.019 17.631,113.019 18.591,113.979 24.191,113.979 24.536,114.324 29.271,114.324 29.616,113.979 30.041,113.979 30.496,114.434 35.061,114.434 35.636,115.009 36.313,115.009 37.343,113.979 41.845,113.979 42.349,113.475 v1(43.275,113.475)
  Bottom Layer w0.12: v1(8.906,70.975) 8.906,72.177 8.553,72.53 8.553,76.262 7.586,77.229 7.586,79.711 8.15,80.275 8.15,81.36 8.741,81.951 8.741,85.041 9.198,85.498 9.198,87.334 8.316,88.216 8.316,99.668 7.955,100.029 7.955,107.255 9.641,108.941 v1(9.641,113.229) U24.1@9.641,114.504 ; v1(18.65,69.075) SB34.1@19.9,69.075 ; SB12.2@45.475,85.55 45.321,85.704 45.321,93.196 45.77,93.645 45.77,96.07 47.353,97.653 47.353,112.375 47.35,112.379 v1(47.35,112.95)
T_VCP_TX: CN5.14 R3.1 SB9.1 SB19.2 U24.3 | length 88.1
  Top Layer w0.12: v1(7.816,126.954) R3.1@8.591,126.954 ; v1(8.341,113.529) 8.341,114.812 CN5.14@8.458,114.929 ; v1(42.875,112.829) 43.279,112.425 v1(47.975,112.425)
  Signal Layer 2 w0.12: v1(8.341,113.529) 9.271,112.599 17.805,112.599 18.765,113.559 24.365,113.559 24.71,113.904 29.097,113.904 29.442,113.559 30.261,113.559 30.716,114.014 36.714,114.014 37.169,113.559 41.436,113.559 42.166,112.829 v1(42.875,112.829)
  Bottom Layer w0.12: v1(7.816,126.954) 7.666,126.804 7.666,115.554 8.341,114.879 U24.3@8.341,114.504 v1(8.341,113.529) ; SB9.1@47.875,87.25 SB19.2@47.875,85.55 46.95,85.55 46.795,85.705 46.795,86.424 46.161,87.058 46.161,89.511 47.773,91.123 47.773,112.223 v1(47.975,112.425)
TD_N: R78.1 U15.20 U16.4 U17.3 | length 21.1
  Top Layer w0.13: v1@36.05,30.05 36.622,30.05 36.816,30.244 36.816,31.054 U16.4@36.741,31.129 36.801,31.189 36.801,32.13 36.256,32.675 36.256,34.105 36.75,34.6 36.75,35.42 v1(36.616,35.554) 36.759,35.697 36.759,36.062 36.991,36.294 36.991,36.629 U15.20@36.941,36.679 ; U17.3@43.251,27.434 43.251,27.839 44.309,28.897 44.309,29.416 v1@44.1,29.625
  Bottom Layer w0.13: v1(35.9,30.05) 36.23,30.05 37.139,30.96 39.74,30.96 41.58,29.12 43.607,29.12 v1(44.091,29.604) ; R78.1@36.191,34.829 36.616,35.254 v1(36.616,35.554)
TD_P: R77.1 U15.21 U16.3 U17.1 | length 21.6
  Top Layer w0.11: 37.216,30.379 37.216,31.815
  Top Layer w0.13: v1@36.475,29.6 36.712,29.6 37.216,30.104 37.216,30.379 ; 37.216,31.815 37.216,32.332 36.741,32.807 U16.3@36.741,33.429 36.741,34.05 37.132,34.441 37.132,35.42 v1(37.266,35.554) 37.141,35.679 37.141,35.904 37.373,36.136 37.373,36.611 U15.21@37.441,36.679 ; v1@44.837,29.637 44.691,29.491 44.691,28.954 45.791,27.854 U17.1@45.791,27.434
  Bottom Layer w0.13: v1(36.466,29.604) 36.466,29.746 37.297,30.578 39.582,30.578 41.422,28.738 43.925,28.738 v1(44.841,29.654) ; R77.1@37.191,34.829 37.191,35.479 v1(37.266,35.554)
TX_N: CN14.2 U17.14 | length 10.6
  Top Layer w0.13: U17.14@43.251,18.284 43.251,17.374 44.359,16.266 44.359,15.821 45.051,15.129 46.866,15.129 48.116,13.879 48.116,13.014 48.114,13.012 48.114,12.106 47.708,11.7 CN14.2@46.919,11.7
TX_P: CN14.1 U17.16 | length 11
  Top Layer w0.13: U17.16@45.791,18.284 45.791,17.316 44.741,16.266 44.741,15.979 45.209,15.511 47.024,15.511 48.498,14.037 48.498,12.856 48.496,12.854 48.496,11.947 47.939,11.39 CN14.1@47.939,10.6
USB_DEV_HS_CN_N: CN1.2 U5.5 | length 2.1
  Top Layer w0.155: U5.5@49.541,127.154 49.482,127.213 49.482,129.023 CN1.2@49.616,129.158
USB_DEV_HS_CN_P: CN1.3 U5.6 | length 2.1
  Top Layer w0.155: CN1.3@48.966,129.158 49.1,129.023 49.1,127.213 U5.6@49.041,127.154
USB_DEV_HS_N: U5.2 U7.R14 | length 17.5
  Top Layer w0.155: U7.R14@33.616,123.804 33.751,123.938 48.814,123.938 49.416,124.54 49.472,124.596 49.472,125.785 U5.2@49.541,125.854
USB_DEV_HS_P: U5.1 U7.R15 | length 16.8
  Top Layer w0.155: U7.R15@33.616,124.454 33.751,124.319 48.657,124.319 49.091,124.754 49.091,125.804 U5.1@49.041,125.854
USB_FS_ID: CN13.4 SB24.2 U22.1 | length 83.1
  Top Layer w0.12: v1(18.941,6.479) 18.941,5.891 U22.1@18.928,5.879 19.516,5.879 20.173,5.222 CN13.4@20.173,4.139
  Bottom Layer w0.12: v1(18.941,6.479) 21.791,6.479 22.786,7.474 22.786,11.791 23.195,12.2 23.195,24.331 22.63,24.896 22.63,29.906 22.23,30.306 22.23,30.967 22.395,31.132 22.395,42.706 21.65,43.451 21.65,61.939 27.012,67.301 27.012,69.224 25.735,70.501 25.735,71.691 30.182,76.138 30.663,76.138 30.9,76.375 SB24.2@30.9,76.975
USB_FS_N: SB21.2 U19.1 | length 77.1
  Top Layer w0.155: v1(21.491,11.979) 21.357,11.844 21.357,10.538 22.116,9.779 U19.1@22.116,9.429
  Bottom Layer w0.155: v1(21.491,11.979) 21.222,12.248 21.222,23.602 20.756,24.068 20.756,63.406 24.206,66.856 24.206,73.392 25.383,74.569 27.394,74.569 28.716,75.891 28.716,80.579 SB21.2@29.266,81.129
USB_FS_OVCR: LD7.2 R61.2 SB76.1 U18.3 | length 78.7
  Top Layer w0.12: LD7.2@27.866,3.479 27.866,3.729 29.366,5.229 29.366,7.604 29.791,8.029 30.841,8.029 31.291,8.479 31.291,10.004 30.941,10.354 R61.2@30.941,11.024 U18.3@29.641,11.024 29.641,11.909 28.55,13 28.55,14.15 28.175,14.525 v1(28.15,14.525) ; v1(51.625,21.575) v1(59.95,21.575)
  Signal Layer 2 w0.12: v1(27.475,31.775) 27.584,31.884 34.666,31.884 35.351,31.199 46.514,31.199 47.77,32.455 v1(49.8,32.455)
  Bottom Layer w0.12: v1(27.475,31.775) 27.475,15.2 v1(28.15,14.525) ; v1(49.8,32.455) 49.8,31.725 51.65,29.875 51.65,21.6 v1(51.625,21.575) ; SB76.1@59.55,18.85 59.55,19.95 59.95,20.35 v1(59.95,21.575)
USB_FS_P: SB22.2 U19.3 | length 77.1
  Top Layer w0.155: U19.3@20.216,9.429 20.216,9.779 20.975,10.538 20.975,11.844 v1(20.841,11.979)
  Bottom Layer w0.155: v1@20.953,11.867 v1(20.841,11.979) 20.841,23.445 20.375,23.911 20.375,63.564 23.825,67.014 23.825,73.55 25.225,74.95 27.236,74.95 28.335,76.049 28.335,80.56 SB22.2@27.766,81.129
USB_FS_PWR_EN: R56.2 SB77.2 U18.4 | length 5.5
  Top Layer w0.12: v1(28.974,13.224) U18.4@29.641,13.224 29.646,13.229 R56.2@31.066,13.229
  Bottom Layer w0.12: SB77.2@28.646,16.544 28.646,13.552 v1(28.974,13.224)
USB_FS_VBUS: C84.2 CN13.1 R60.1 R62.1 U18.1 U21.1 | length 12.4
  Top Layer w0.3: CN13.1@22.123,4.139 22.123,5.011 23.241,6.129 U21.1@24.241,6.129 24.241,7.279 25.541,8.579 C84.2@26.641,8.579 26.641,9.204 26.891,9.454 R62.1@27.691,9.454 27.741,9.504 U18.1@27.741,10.629 ; R60.1@26.266,10.529 27.641,10.529 U18.1@27.741,10.629 ; U18.1@27.741,11.024 U18.1@27.741,10.629
VBAT: C61.2 CN11.33 SB52.1 U14.6 | length 32.3
  Top Layer w0.3: CN11.33@3.246,60.959 4.555,59.65 ; 4.591,59.614 4.555,59.65 ; U14.6@28.866,60.479 28.866,59.566 26.525,57.225 C61.2@26.525,57.025 v1@25.723,57.025 ; 4.555,59.65 20.955,59.65 23.85,56.755 25.453,56.755 v1@25.723,57.025 ; v1@25.723,57.025 v1(25.726,57.028) 25.703,57.028 25.7,57.025 v1@25.723,57.025
  Bottom Layer w0.3: v1(25.726,57.028) 25.726,58.326 26.525,59.125 SB52.1@26.525,59.325
VCAP: C48.2 C50.2 U14.71 U14.106 | length 45.6
  Top Layer w0.3: U14.106@27.366,82.129 27.366,83.434 ; U14.71@45.941,79.554 47.254,79.554 47.425,79.725
  Top Layer w0.5: v1@26.25,79.925 v1(26.25,80.475) ; v1(26.35,86.2) v1(26.775,85.775) 27.225,85.325 C48.2@27.225,84.675 27.2,84.65 27.2,83.6 27.366,83.434
  Top Layer w0.6: 47.425,79.725 47.575,79.875 C50.2@48.225,79.875 v1(48.225,78.875) v1(48.675,78.425)
  Signal Layer 2 w0.5: v1(26.35,86.2) v1(26.775,85.775)
  Signal Layer 2 w0.6: 26.825,80.475 v1(26.25,79.9) v1(26.25,80.475) 26.825,80.475 ; 26.825,80.475 27.8,80.475 29.4,78.875 35.75,78.875 36.2,78.425 47.775,78.425 ; 47.775,78.425 v1(48.675,78.425) v1(48.225,78.875) 47.775,78.425
  Signal Layer 3 w0.5: v1(26.25,79.9) v1(26.25,80.475) ; v1(26.35,86.2) v1(26.775,85.775)
  Signal Layer 3 w0.6: v1(48.225,78.875) v1(48.675,78.425)
  Bottom Layer w0.5: v1(26.25,79.9) v1(26.25,80.475) 26.25,85.25 26.35,85.35 ; 26.35,85.35 v1(26.35,86.2) v1(26.775,85.775) 26.35,85.35
  Bottom Layer w0.6: v1(48.225,78.875) v1(48.675,78.425)
VDD_MCU: C4.1 C26.1 C46.2 C47.2 C49.2 C51.2 C52.2 C53.2 C54.2 C55.2 C56.2 C57.2 C60.2 C63.1 C73.2 JP5.2 R4.1 R37.1 R40.2 R43.2 R46.2 R47.2 R48.2 R56.1 R61.1 SB11.1 SB25.1 SB52.2 U1.8 U10.8 U14.17 U14.30 U14.39 U14.52 U14.62 U14.72 U14.84 U14.108 U14.131 U14.144 U15.9 | length 114.7
  Top Layer w0.3: U1.8@10.616,128.179 C4.1@11.741,128.179 v1(11.741,129.104) ; R4.1@11.766,126.779 v1(12.491,126.779) ; v1(13.141,114.454) C26.1@13.791,114.454 ; v1(13.791,113.604) C26.1@13.791,114.454 ; U10.8@14.316,115.679 14.283,115.679 13.791,115.187 C26.1@13.791,114.454 ; v1(21.975,63.175) 21.975,62.75 C56.2@22.25,62.475 22.271,62.454 U14.144@24.291,62.454 ; v1(22.525,70.6) 22.075,70.15 C52.2@22.075,69.975 C54.2@22.075,69.05 22.079,69.054 U14.131@24.291,69.054 ; v1(24.025,84.225) C47.2@24.8,84.225 26.266,82.759 U14.108@26.266,82.129 ; v1(31.741,43.304) R40.2@32.466,43.304 ; v1(32.016,40.429) R48.2@32.741,40.429 ; v1(32.016,41.479) R47.2@32.741,41.479 ; v1(33.875,57.525) C57.2@33.875,58.225 33.875,58.85 34.366,59.341 U14.17@34.366,60.479 ; v1(36.466,43.104) C73.2@37.091,42.479 37.091,41.904 37.941,41.054 U15.9@37.941,40.579 ; R43.2@38.291,43.304 v1(38.291,44.029) ; U14.84@38.366,82.129 38.366,84.309 C46.2@38.35,84.325 v1(39.025,84.325) ; U14.30@40.866,60.479 v1(40.866,59.134) 41.325,58.675 C60.2@41.325,58.2 ; R46.2@41.441,43.304 v1(41.441,44.029) ; U14.39@45.941,63.554 46.821,63.554 47.35,63.025 C55.2@48.2,63.025 v1(48.825,63.025) ; U14.52@45.941,70.054 45.95,70.045 47.755,70.045 C53.2@48.15,69.65 48.15,69.583 48.575,69.158 v1(48.575,68.975) ; U14.62@45.941,75.054 48.021,75.054 C51.2@48.15,74.925 48.175,74.9 v1(48.175,74) ; U14.72@45.941,80.154 46.91,80.154 47.756,81 C49.2@48.15,81 48.15,81.2 v1(48.625,81.675) ; R37.1@47.925,58.175 47.925,57.95 48.425,57.45 C63.1@48.425,57.075 v1(49.025,57.075)
  Top Layer w0.5: v1(18.566,86.879) v1(19.166,86.879) v1(19.841,86.879) ; R56.1@31.066,14.129 v1(31.066,14.779) ; v1(31.841,11.804) R61.1@31.841,11.024 31.841,10.479 31.941,10.379 v1(31.941,9.954)
  Signal Layer 2 w0.5: v1(18.566,86.879) v1(19.166,86.879) v1(19.841,86.879) ; v1(31.841,11.804) 31.841,10.054 v1(31.941,9.954)
  Signal Layer 3 w0.5: v1(13.791,113.604) v1@13.791,113.804
  Signal Layer 3 w0.8: v1(11.741,129.104) 11.741,127.529 v1(12.491,126.779) 11.366,125.654 11.366,115.679 12.591,114.454 v1(13.141,114.454) v1@13.791,113.804 ; v1(13.791,113.604) 13.791,110.229 15.641,108.379 15.641,97.279 15.016,96.654 15.016,93.629 15.916,92.729 15.916,91.629 16.941,90.604 16.941,88.504 v1(18.566,86.879) v1(19.166,86.879) v1(19.841,86.879)
  Bottom Layer w0.3: v1(25.25,61.05) 26,61.05 26.525,60.525 SB52.2@26.525,60.425 ; SB25.1@26.25,78.075 v1(26.25,79.225)
  Bottom Layer w0.5: v1(13.141,114.454) 13.141,114.254 v1(13.791,113.604) ; v1(18.566,86.879) v1(19.166,86.879) v1(19.841,86.879) 20.7,87.738 20.7,88.05 21.45,88.8 SB11.1@21.975,88.8 ; v1(31.066,14.779) 31.841,14.004 v1(31.841,11.804) 31.841,10.054 v1(31.941,9.954)
VDDA: C62.1 C66.1 C67.2 CN10.1 R36.1 R37.2 U14.33 | length 41.2
  Top Layer w0.3: v1(42.375,62.025) 42.366,62.016 U14.33@42.366,60.479 42.366,59.597 42.743,59.22 42.949,59.22 43.224,58.945 44.805,58.945 R36.1@45.575,58.175 ; C67.2@45.275,56.5 45.775,57 ; C62.1@47.525,57.075 C66.1@46.475,57.075 ; R36.1@45.575,58.175 45.575,57.2 45.775,57 ; R36.1@45.575,58.175 R37.2@46.525,58.175 46.525,57.125 C66.1@46.475,57.075 ; 45.775,57 C66.1@46.4,57 C66.1@46.475,57.075
  Signal Layer 2 w0.3: v1(41,74.15) 41.395,74.545 55.7,74.545 CN10.1@56.586,73.659
  Bottom Layer w0.3: v1(41,74.15) 41,66.933 42.775,65.158 42.775,62.425 v1(42.375,62.025)
VIN: C42.2 CN8.15 CN11.24 U12.3 | length 80.6
  Top Layer w0.5: v1@18.266,100.654 U12.3@18.266,101.754 ; U12.3@18.266,101.754 18.246,101.774 C42.2@16.541,101.774 v1(16.541,100.629) v1(18.266,100.629) v1(19.641,100.629) v1(19.641,101.754) U12.3@18.266,101.754
  Top Layer w1: CN11.24@5.786,73.659 CN8.15@10.866,73.659
  Signal Layer 2 w0.4: 1.491,77.379 1.556,77.444 4.501,77.444 4.516,77.429 ; 1.491,80.129 1.636,79.984 3.986,79.984 4.516,79.454 4.516,77.429 ; 1.791,75.404 2.266,74.929 4.161,74.929 ; 4.516,74.929 4.516,77.429
  Signal Layer 2 w0.8: 1.791,75.404 1.491,75.704 1.491,77.379 1.491,80.129 1.491,103.754 2.041,104.304 7.191,104.304 8.451,103.044 11.465,103.044 12.05,102.459 13.337,102.459 13.402,102.524 14.225,102.524 14.495,102.254 15.026,102.254 v1@16.541,100.739
  Signal Layer 2 w1: 4.161,74.929 4.516,74.929 CN11.24@5.786,73.659 CN8.15@10.866,73.659
VREFP: C58.2 C64.1 C65.2 R36.2 SB42.2 U14.32 | length 10.9
  Top Layer w0.3: v1(41.575,62.15) 41.866,61.859 U14.32@41.866,60.479 41.866,59.503 42.569,58.8 42.775,58.8 43.3,58.275 C58.2@43.3,58.225 ; C58.2@43.3,58.225 43.3,58.125 42.8,57.625 C64.1@42.8,57 C65.2@44.15,57 44.175,57.025 R36.2@44.175,58.175 43.35,58.175 C58.2@43.3,58.225
  Bottom Layer w0.3: v1(41.575,62.15) 41.95,62.525 SB42.2@41.95,63.3
WAKEUP_KEY: B1.3 B1.4 R64.2 R74.2 U23.1 | length 72.2
  Top Layer w0.12: B1.3@3.017,4.023 B1.4@12.517,4.023 14.56,4.023 U23.1@14.566,4.016 R64.2@14.566,5.029 v1(15.641,5.029)
  Bottom Layer w0.12: v1(15.641,5.029) 16.086,5.474 21.125,5.474 23.026,7.374 23.026,10.639 23.675,11.288 23.675,25.222 23.68,25.227 23.68,25.568 23.52,25.728 23.52,30.967 23.355,31.132 23.355,41.318 25.015,42.978 25.015,54.04 26.6,55.625 R74.2@26.825,55.625
pads on no net: CART1.1 CN1.4 CN5.0 CN5.1 CN5.2 CN5.9 CN8.1 CN11.10 CN11.26 CN11.67 CN13.11 CN13.12 MIRE-1.1 MIRE-2.1 MIRE-3.1 MIRE-4.1 MIRE-5.1 MIRE-6.1 U1.2 U5.4 U7.A1 U7.A2 U7.A3 U7.A4 U7.A5 U7.A6 U7.A8 U7.A9 U7.A10 U7.A11 U7.A12 U7.A13 U7.B1 U7.B2 U7.B3 U7.B4 U7.B5 U7.B6 U7.B7 U7.B8 U7.B9 U7.B10 U7.B11 U7.B12 U7.B13 U7.B14 U7.B15 U7.C2 U7.C3 U7.C4 U7.C11 U7.C12 U7.C13 U7.C14 U7.C15 U7.D1 U7.D2 U7.D3 U7.D4 U7.D10 U7.D11 U7.D13 U7.D14 U7.E1 U7.E2 U7.E3 U7.E4 U7.E12 U7.E13 U7.E14 U7.E15 U7.F1 U7.F4 U7.F14 U7.G4 U7.G14 U7.G15 U7.H1 U7.H2 U7.H3 U7.H4 U7.H14 U7.H15 U7.J2 U7.J3 U7.J4 U7.K1 U7.K2 U7.K3 U7.K12 U7.K14 U7.K15 U7.L1 U7.L3 U7.L12 U7.L13 U7.L14 U7.L15 U7.M2 U7.M3 U7.M4 U7.M5 U7.M6 U7.M7 U7.M12 U7.M13 U7.M14 U7.M15 U7.N2 U7.N4 U7.N5 U7.N6 U7.N7 U7.N11 U7.N13 U7.N14 U7.N15 U7.P2 U7.P4 U7.P5 U7.P6 U7.P7 U7.P8 U7.P9 U7.P10 U7.P11 U7.P12 U7.P13 U7.P14 U7.P15 U7.R2 U7.R3 U7.R6 U7.R7 U7.R8 U7.R9 U7.R10 U7.R11 U7.R12 U7.R13 U11.3 U14.0 U17.4 U17.5 U17.12 U17.13 U19.5 U24.4

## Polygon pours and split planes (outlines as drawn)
GND on Bottom Layer "GND_L06_P116" (solid, remove dead copper, pour order 116): 20.266,133.254 20.266,108.279 20.441,108.104 25.741,108.104 26.241,107.604 26.241,99.479 26.666,99.054 35.991,99.054 37.675,97.37 37.675,87.275 36.475,86.075 29.687,86.075 29.391,85.779 25.866,82.254 25.866,75.084 29.691,71.259 29.691,53.054 29.266,52.629 29.266,44.804 29.691,44.379 33.241,44.379 33.791,43.829 33.791,40.354 32.991,39.554 31.191,39.554 30.766,39.129 30.766,37.729 33.316,35.179 33.316,20.3 56.4,20.3 56.4,0.054 68.491,0.054 69.916,1.479 69.916,132.004 68.666,133.254 21.541,133.254
GND on Bottom Layer "GND_L06_P112" (solid, remove dead copper, pour order 112): 22.011,76.625 21.975,76.661 21.975,78.525 26.479,83.029 26.866,83.029 26.866,75.187 30.266,71.787 30.266,44.004 27.216,40.954 27.216,32.279 27.816,31.679 28.966,30.529 28.966,9.454 29.516,8.904 33.325,8.904 33.325,0.204 1.241,0.204 0.066,1.379 0.066,131.779 1.641,133.354 20.391,133.354 20.441,133.304 20.441,108.104 19.966,107.629 19.966,105.804 19.091,104.929 19.091,103.079 18.691,102.679 16.266,102.679 15.791,102.204 15.791,100.484 16.421,99.854 25.216,99.854 25.241,99.829 25.241,89.304 22.769,86.831 22.706,86.831 15.1,79.225 15.1,73.475 15.575,73 21.8,73 22.011,73.211
SHGND on Bottom Layer "SHGND_L06_P126" (solid, remove dead copper, pour order 126): 35.641,17.325 53.369,17.325 53.369,0 35.741,0 35.641,0.004
VDD_MCU on Bottom Layer "VDD_MCU_L06_P086" (solid, remove dead copper, pour order 86): 32.591,9.154 33.041,9.604 33.041,34.943 30.341,37.643 30.341,39.229 30.991,39.879 32.791,39.879 33.366,40.454 33.366,43.729 33.041,44.054 30.991,44.054 27.541,40.604 27.541,32.479 29.241,30.779 29.241,9.554 29.641,9.154
3V3_VDD on Bottom Layer "3V3_VDD_L06_P080" (solid, remove dead copper, pour order 80): 15.325,73.675 15.68,73.32 21.22,73.32 21.6,73.7 21.6,78.563 26.416,83.379 29.041,86.004 29.862,86.825 37,86.825 37,97.47 35.766,98.704 26.241,98.704 25.891,98.354 25.891,96.679 26.041,96.529 27.141,96.529 27.441,96.229 27.441,90.754 15.325,78.638
VIN on Bottom Layer "VIN_L06_P084" (solid, remove dead copper, pour order 84): 16.491,102.304 16.141,101.954 16.141,100.604 16.466,100.279 19.816,100.279 20.066,100.529 20.066,102.029 19.791,102.304
5V_VIN on Bottom Layer "5V_VIN_L06_P036" (solid, remove dead copper, pour order 36): 19.341,104.754 20.291,105.704 20.291,107.479 20.641,107.829 25.616,107.829 25.991,107.454 25.991,100.604 25.641,100.254 20.466,100.254 20.266,100.454 20.266,102.404 19.566,103.104 19.341,103.329
3V3_VDD on Signal Layer 3 "3V3_VDD_L04_P078" (solid, remove dead copper, pour order 78): 21.35,75.975 20.775,76.55 17.45,76.55 15.875,74.975 15.875,67.625 14.2,65.979 10.316,65.979 8.516,64.179 8.516,39.554 9.971,38.099 11.496,38.099 16.366,33.229 16.366,18.054 7.616,9.304 7.616,8.204 7.591,8.179 8.491,7.279 12.716,7.279 21.441,16.004 21.441,40.91 21.35,41.001
3V3_PER on Signal Layer 3 "3V3_PER_L04_P122" (solid, remove dead copper, pour order 122): 49.813,82.563 49.8,82.55 49.8,81.05 49,80.25 49,72.789 49.875,71.914 49.875,56.673 48.9,55.698 48.9,52.839 47.825,51.764 47.825,45.075 48.05,44.85 48.025,44.825 48.025,41.25 46.615,39.84 46.6,39.125 46.6,37.35 53.648,37.35 53.726,37.428 53.744,37.444 58.306,37.444 63.216,42.354 63.216,68.204 59.141,72.279 59.141,90.629 54.091,95.679 48.016,95.679 48.016,84.359
3V3_PER on Signal Layer 3 "3V3_PER_L04_P120" (solid, remove dead copper, pour order 120): 51.075,39.475 28.375,39.475 27.391,38.491 27.391,33.534 28.525,32.4 30.4,32.4 30.4,36.225 31.55,37.375 31.575,37.35 51.075,37.35
GND on Signal Layer 3 "GND_L04_P108" (solid, remove dead copper, pour order 108): 6.591,9.904 0.191,9.904 0.091,9.804 0.091,1.629 1.691,0.029 28.591,0.029 28.741,0.179 28.741,0.854 28.191,1.404 28.191,4.766 28.191,17.204 26.816,18.579 26.816,35.379 26.816,39.704 26.366,40.154 25.07,41.45 22.15,41.45 21.666,40.966 21.666,15.829 12.941,7.104 8.091,7.104 7.391,7.804 7.391,9.104
GND on Signal Layer 3 "GND_L04_P106" (solid, remove dead copper, pour order 106): 8.241,37.229 11.736,37.229 15.791,33.174 15.791,18.279 8.991,11.479 8.241,11.479
GND on Signal Layer 3 "GND_L04_P104" (solid, remove dead copper, pour order 104): 58.913,36.812 58.9,36.825 51.175,36.825 50.25,35.9 50.25,18.275 52.5,16.025 52.541,15.175 52.541,0.229 52.666,0.104 68.416,0.104 69.966,1.654 69.966,131.879 68.691,133.154 34.191,133.154 34.091,133.054 34.091,132.504 35.391,131.204 62.816,131.204 64.091,129.929 64.091,124.654 64.091,112.841 63.254,112.004 49.866,112.004 47.666,114.204 45.866,114.204 45.441,113.779 45.441,110.329 43.916,108.804 41.766,108.804 41.491,108.529 41.491,108.254 43.391,106.354 45.041,106.354 46.741,104.654 46.741,100.654 49.616,97.779 50.666,97.779 51.816,98.929 51.816,107.179 52.116,107.479 53.241,107.479 53.641,107.079 53.641,96.579 59.866,90.354 59.866,72.404 63.991,68.279 63.991,41.891
GND on Signal Layer 3 "GND_L04_P100" (solid, remove dead copper, pour order 100): 21.591,81.477 21.575,81.461 21.575,77.5 21,76.925 17.127,76.925 17.114,76.938 16.404,76.229 15.3,75.125 15.3,67.925 13.8,66.425 8.925,66.425 8.075,67.275 8.075,71.817 8.066,71.826 8.066,74.229 10.066,76.229 10.066,78.379 10.966,79.279 12.466,79.279 12.966,79.779 12.966,82.679 12.591,83.054 11.091,83.054 10.216,83.929 10.216,91.229 5.866,95.579 5.866,114.279 5.091,115.054 1.966,115.054 1.591,114.679 0.116,114.679 0.116,131.829 1.466,133.179 15.641,133.179 14.116,131.654 14.116,110.154 15.141,109.129 15.141,109.104 15.316,108.929 38.166,108.929 38.491,108.604 38.491,105.779 38.191,105.479 34.566,105.479 33.516,104.429 33.516,103.354 29.891,99.729 26.616,99.729 26.241,100.104 26.241,107.604 25.766,108.079 20.441,108.079 20.016,107.654 20.016,106.004 19.066,105.054 19.066,103.229 19.491,102.804 19.491,102.379 16.316,102.379 16.091,102.154 16.091,97.729 15.016,96.654 15.016,93.629 15.916,92.729 15.916,91.229 16.941,90.204 16.941,88.229 17.791,87.379 20.716,87.379 21.591,86.504 21.591,84.804
3V3_PER on Signal Layer 3 "3V3_PER_L04_P074" (solid, remove dead copper, pour order 74): 34.541,101.129 30.641,97.229 18.841,97.229 17.85,96.238 17.85,93.87 18.166,93.554 18.166,91.729 20.341,89.554 20.341,88.154 19.966,87.779 18.491,87.779 17.566,88.704 17.566,89.979 16.516,91.029 16.516,92.929 15.541,93.904 15.541,96.254 18.741,99.454 30.016,99.454 34.391,103.829 34.541,103.679
3V3_PER on Signal Layer 3 "3V3_PER_L04_P072" (solid, remove dead copper, pour order 72): 47.435,96.26 31.406,96.26 30.341,97.325 30.341,99.329 35.091,104.079 38.191,104.079 38.791,104.679 38.791,108.529 39.166,108.904 40.591,108.904 40.591,108.879 43.291,106.179 44.841,106.179 46.416,104.604 46.416,100.479 51.516,95.379 51.516,94.804 48.891,94.804
5V on Signal Layer 3 "5V_L04_P066" (solid, remove dead copper, pour order 66): 1.616,113.729 1.616,114.129 2.116,114.629 4.816,114.629 5.316,114.129 5.316,95.454 9.916,90.854 9.916,83.354 10.466,82.804 12.341,82.804 12.556,82.589 12.556,79.819 12.366,79.629 10.491,79.629 9.891,79.029 9.891,76.554 7.741,74.404 7.741,11.254 6.716,10.229 1.216,10.229 0.891,10.554 0.891,80.104 2.141,81.354 4.341,81.354 6.616,83.629 6.616,84.904 5.891,85.629 2.191,85.629 1.616,86.204
3V3_STLK on Signal Layer 3 "3V3_STLK_L04_P042" (solid, remove dead copper, pour order 42): 33.866,132.179 34.691,131.354 34.691,128.554 34.716,128.529 34.716,126.504 44.966,116.254 44.966,110.404 43.766,109.204 15.766,109.204 14.541,110.429 14.541,131.429 15.291,132.179
5V_USB_CHGR on Signal Layer 3 "5V_USB_CHGR_L04_P040" (solid, remove dead copper, pour order 40): 63.716,113.591 62.554,112.429 50.141,112.429 35.641,126.929 35.641,129.779 36.741,130.879 62.641,130.879 63.716,129.804 63.716,124.829
VDD_MCU on Signal Layer 3 "VDD_MCU_L04_P012" (solid, remove dead copper, pour order 12): 47.75,41.525 47.7,41.575 47.7,51.8 48.694,52.794 48.694,55.094 49.31,55.71 49.31,56.396 49.67,56.756 49.67,73.809 48.675,74.804 48.675,80.3 49.425,81.05 49.4,81.075 49.4,82.175 47.7,83.875 47.7,94.075 46.396,95.379 21.866,95.379 21.866,41.604 25.266,41.604 27.166,39.704 45.929,39.704
NetC85_2 on Signal Layer 3 "NETC85_2_L04_P046" (solid, remove dead copper, pour order 46): 33.941,23.129 33.091,22.279 33.091,18.278 33.969,17.4 49.241,17.4 49.241,22.479 48.591,23.129
GND on Signal Layer 3 "GND_L04_P102" (solid, remove dead copper, pour order 102): 21.391,96.254 21.766,95.879 21.766,91.179 21.541,90.954 20.591,90.954 19.466,92.079 19.466,95.654 20.066,96.254
3V3 on Signal Layer 3 "3V3_L04_P070" (solid, remove dead copper, pour order 70): 53.116,107.229 53.391,106.954 53.391,96.904 53.116,96.629 50.641,96.629 50.416,96.854 50.416,97.154 52.091,98.829 52.091,107.004 52.316,107.229
5V_VIN on Signal Layer 3 "5V_VIN_L04_P030" (solid, remove dead copper, pour order 30): 19.341,104.754 20.291,105.704 20.291,107.479 20.641,107.829 25.616,107.829 25.991,107.454 25.991,100.604 25.641,100.254 20.466,100.254 20.266,100.454 20.266,102.404 19.566,103.104 19.341,103.329
VIN on Signal Layer 3 "VIN_L04_P032" (solid, remove dead copper, pour order 32): 19.791,100.254 20.041,100.504 20.041,102.004 19.916,102.129 16.416,102.129 16.266,101.979 16.266,100.429 16.441,100.254
3V3_PER on Signal Layer 3 "3V3_PER_L04_P118" (solid, remove dead copper, pour order 118): 31.087,15.712 31.075,15.725 31.085,24.285 30.416,24.954 30.416,35.254 27.391,35.254 27.391,18.684 28.441,17.634 28.441,1.504 28.916,1.029 34.116,1.029 34.666,1.579 34.666,4.7 31.075,8.263 31.075,15.7
NetC78_2 on Signal Layer 3 "NETC78_2_L04_P044" (solid, remove dead copper, pour order 44): 31.891,37.104 30.891,36.104 30.891,25.154 32.316,23.729 48.316,23.729 49.116,24.529 49.116,36.604 48.616,37.104
GND on Top Layer "GND_L01_P114" (solid, remove dead copper, pour order 114): 1.574,133.34 0.112,131.879 0.112,107.629 20.162,107.629 20.662,108.129 25.862,108.129 26.612,107.379 26.612,100.379 25.987,99.754 16.287,99.754 15.412,100.629 13.862,100.629 13.862,107.629 0.112,107.629 0.112,1.629 1.612,0.129 35.362,0.129 35.362,12.379 28.987,12.379 28.612,12.004 28.612,8.979 27.012,7.379 26.262,7.379 25.362,6.479 25.362,4.379 23.862,2.879 21.862,2.879 21.362,3.379 21.362,5.379 25.112,9.129 25.112,14.629 25.362,14.879 35.862,14.879 35.862,8.379 53.362,8.379 53.365,0 68.233,0 69.862,1.629 69.862,106.879 60.112,106.879 59.612,107.379 59.612,108.629 59.862,108.879 63.112,108.879 63.112,111.879 62.612,112.379 60.646,112.379 59.862,113.163 59.862,124.137 60.604,124.879 63.612,124.879 64.362,124.129 64.362,119.379 64.862,118.879 67.392,118.879 67.392,118.849 67.862,118.379 67.862,107.629 67.612,107.379 67.612,107.129 69.862,107.129 69.862,131.879 68.401,133.34
USB_FS_VBUS on Top Layer "USB_FS_VBUS_L01_P068" (solid, remove dead copper, pour order 68): 27.991,12.079 28.266,11.804 28.266,9.154 26.916,7.804 26.116,7.804 24.941,6.629 24.941,4.554 23.666,3.279 21.966,3.279 21.841,3.404 21.841,5.254 25.666,9.079 25.666,10.779 25.816,10.929 26.816,10.929 27.016,11.129 27.016,11.904 27.191,12.079
5V on Top Layer "5V_L01_P064" (solid, remove dead copper, pour order 64): 25.616,14.429 25.466,14.279 25.466,12.929 25.691,12.704 27.941,12.704 28.166,12.929 28.166,13.629 27.941,13.854 27.291,13.854 26.716,14.429
5V on Top Layer "5V_L01_P038" (solid, remove dead copper, pour order 38): 60.854,124.529 60.291,123.966 60.291,113.284 60.871,112.704 62.941,112.704 63.716,111.929 63.716,108.629 63.566,108.479 60.166,108.479 59.991,108.304 59.991,107.554 60.291,107.254 67.116,107.254 67.666,107.804 67.666,118.154 67.366,118.454 64.866,118.454 64.116,119.204 64.116,123.929 63.516,124.529
GND on Top Layer "GND_L01_P022" (solid, remove dead copper, pour order 22): 43.791,133.304 43.791,126.679 42.666,125.554 32.616,125.554 31.991,124.929 31.991,123.179 32.866,122.304 50.741,122.304 54.366,125.929 54.366,133.304
5V_VIN on Top Layer "5V_VIN_L01_P028" (solid, remove dead copper, pour order 28): 16.091,105.154 15.816,104.879 15.816,103.354 16.091,103.079 19.966,103.079 20.291,102.754 20.291,100.479 20.491,100.279 25.641,100.279 25.966,100.604 25.966,107.429 25.591,107.804 20.641,107.804 20.291,107.454 20.291,105.454 19.991,105.154
GND on Top Layer "GND_L01_P024" (solid, remove dead copper, pour order 24): 15.541,100.504 15.316,100.279 13.891,100.279 13.666,100.504 13.666,107.429 14.041,107.804 19.966,107.804 19.966,105.604 19.741,105.379 15.816,105.379 15.541,105.104
VIN on Top Layer "VIN_L01_P026" (solid, remove dead copper, pour order 26): 16.041,102.829 15.816,102.604 15.816,100.504 16.041,100.279 19.816,100.279 20.016,100.479 20.016,102.604 19.791,102.829
GND on Signal Layer 2 "GND_L03_P098" (solid, remove dead copper, pour order 98): 0.566,10.029 1.616,8.979 15.041,8.979 18.116,12.054 27.141,12.054 27.666,12.579 34.091,12.579 34.416,12.904 34.416,13.054 35.291,13.929 69.891,13.929 69.941,13.879 69.941,1.204 68.816,0.079 1.216,0.079 0.216,1.079 0.216,10.004 0.191,10.029
GND on Signal Layer 2 "GND_L03_P096" (solid, remove dead copper, pour order 96): 26.666,100.8 26.766,100.9 34.4,100.9 36.49,98.81 36.49,90.615 33.561,87.686 30.301,87.693 30.287,87.679 18.091,87.679 17.616,87.204 17.616,86.379 18.141,85.854 23.891,85.854 27.741,82.004 41.741,82.004 69.494,82 69.605,81.914 69.941,81.577 69.941,12.204 69.916,12.179 27.616,12.179 27.616,14.229 27.316,14.529 15.691,14.529 13.166,12.004 1.316,12.004 0.579,11.266 0.253,11.266 0.116,11.404 0.116,104.829 0.216,104.929 7.491,104.929 8.751,103.669 10.4,103.669 10.4,101.945 12.241,100.104 25.916,100.104 26.666,100.854
GND on Signal Layer 2 "GND_L03_P094" (solid, remove dead copper, pour order 94): 0.091,113.329 0.391,113.329 1.491,112.229 4.166,112.229 5.641,113.704 38.666,113.704 45.116,120.154 58.621,120.154 59.825,118.95 59.825,113.6 60.475,112.95 69.471,112.95 69.866,112.555 69.866,81.879 43.116,81.879 42.366,82.629 42.366,83.559 42.366,85.429 41.766,86.029 31.966,86.029 27.225,90.77 27.225,106.795 25.716,108.304 20.491,108.304 19.891,107.704 19.891,105.829 18.466,104.404 11.741,104.404 10.716,103.379 10.716,100.529 10.566,100.379 0.341,100.379 0.091,100.629
GND on Signal Layer 2 "GND_L03_P092" (solid, remove dead copper, pour order 92): 2,133.34 1.986,133.354 1.55,133.354 -0.009,131.795 -0.009,117.504 0.166,117.329 0.916,117.329 4.391,120.804 23.941,120.804 26.391,118.354 35.841,118.354 41.566,124.079 48.041,124.079 50.816,126.854 63.146,126.854 68,122 68,114.025 66.054,112.079 69.816,112.079 69.816,132.004 68.491,133.329
VIN on Signal Layer 2 "VIN_L03_P082" (solid, remove dead copper, pour order 82): 12.441,104.079 12.016,104.079 11.191,103.254 11.191,101.679 12.566,100.304 19.716,100.304 19.991,100.579 19.991,102.279 19.366,102.904 18.196,104.074 17.341,104.074
5V on Signal Layer 2 "5V_L03_P062" (solid, remove dead copper, pour order 62): 15.866,14.304 13.316,11.754 1.441,11.754 1.091,11.404 1.091,9.979 1.716,9.354 14.791,9.354 17.816,12.379 27.091,12.379 27.366,12.654 27.366,14.079 27.141,14.304
5V on Signal Layer 2 "5V_L03_P060" (solid, remove dead copper, pour order 60): 60.527,113.837 61.18,113.079 66.579,113.079 67.525,114.025 67.525,121.75 62.871,126.404 50.866,126.404 48.191,123.729 41.841,123.729 36.066,117.954 26.266,117.954 23.766,120.454 4.541,120.454 1.091,117.004 1.091,113.079 1.691,112.479 3.941,112.479 5.466,114.004 38.241,114.004 44.791,120.554 59.971,120.554 60.527,119.998
VDD_MCU on Signal Layer 2 "VDD_MCU_L03_P088" (solid, remove dead copper, pour order 88): 18.166,87.354 17.916,87.104 17.916,86.479 18.266,86.129 24.191,86.129 27.941,82.379 41.591,82.379 42.166,82.954 42.166,85.304 41.641,85.829 31.891,85.829 30.366,87.354
5V_VIN on Signal Layer 2 "5V_VIN_L03_P034" (solid, remove dead copper, pour order 34): 19.366,104.779 20.316,105.729 20.316,107.504 20.666,107.854 25.641,107.854 26.016,107.479 26.016,100.629 25.666,100.279 20.491,100.279 20.291,100.479 20.291,102.429 19.591,103.129 19.366,103.354
GND on Signal Layer 1 "GND_L02_P020" (solid, remove dead copper, pour order 20): 35.266,0 35.266,11.429 37.241,13.404 51.516,13.404 53.666,11.254 53.666,8.429 53.491,8.254 53.491,0 69.037,0 69.416,0.379 70,0.963 70,132.345 69.005,133.34 68,133.34 -0.034,133.379 -0.034,0.929 0.895,0
GND on Signal Layer 4 "GND_L05_P050" (solid, remove dead copper, pour order 50): 35.369,0.079 35.369,11.606 37.766,14.004 49.991,14.004 53.541,10.454 53.541,0.054 53.591,0.079 68.541,0.079 69.866,1.404 69.866,131.829 68.466,133.229 1.791,133.254 1.516,133.254 0.041,131.779 0.041,1.629 1.591,0.079

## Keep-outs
Bottom Layer:
  lines w0.01: 17.231,85.364 ccw(c13.428,86.337) 17.234,85.379 ; 57.551,67.287 ccw(c56.608,71.097) 57.756,67.344 ; 60.327,67.271 cw(c56.608,66.017) 60.36,67.169
Keep-Out Layer:
  lines w0.127: -0.004,1.999 ccw(c1.996,1.999) 1.996,-0.001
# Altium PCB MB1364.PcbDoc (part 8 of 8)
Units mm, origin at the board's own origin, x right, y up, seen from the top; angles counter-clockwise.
Board outline 70 x 133.34 mm, 6 copper layers (Top Layer, Signal Layer 1, Signal Layer 2, Signal Layer 3, Signal Layer 4, Bottom Layer), stack 1.57 mm thick; 321 components, 287 nets, 1372 pads, 2051 vias.

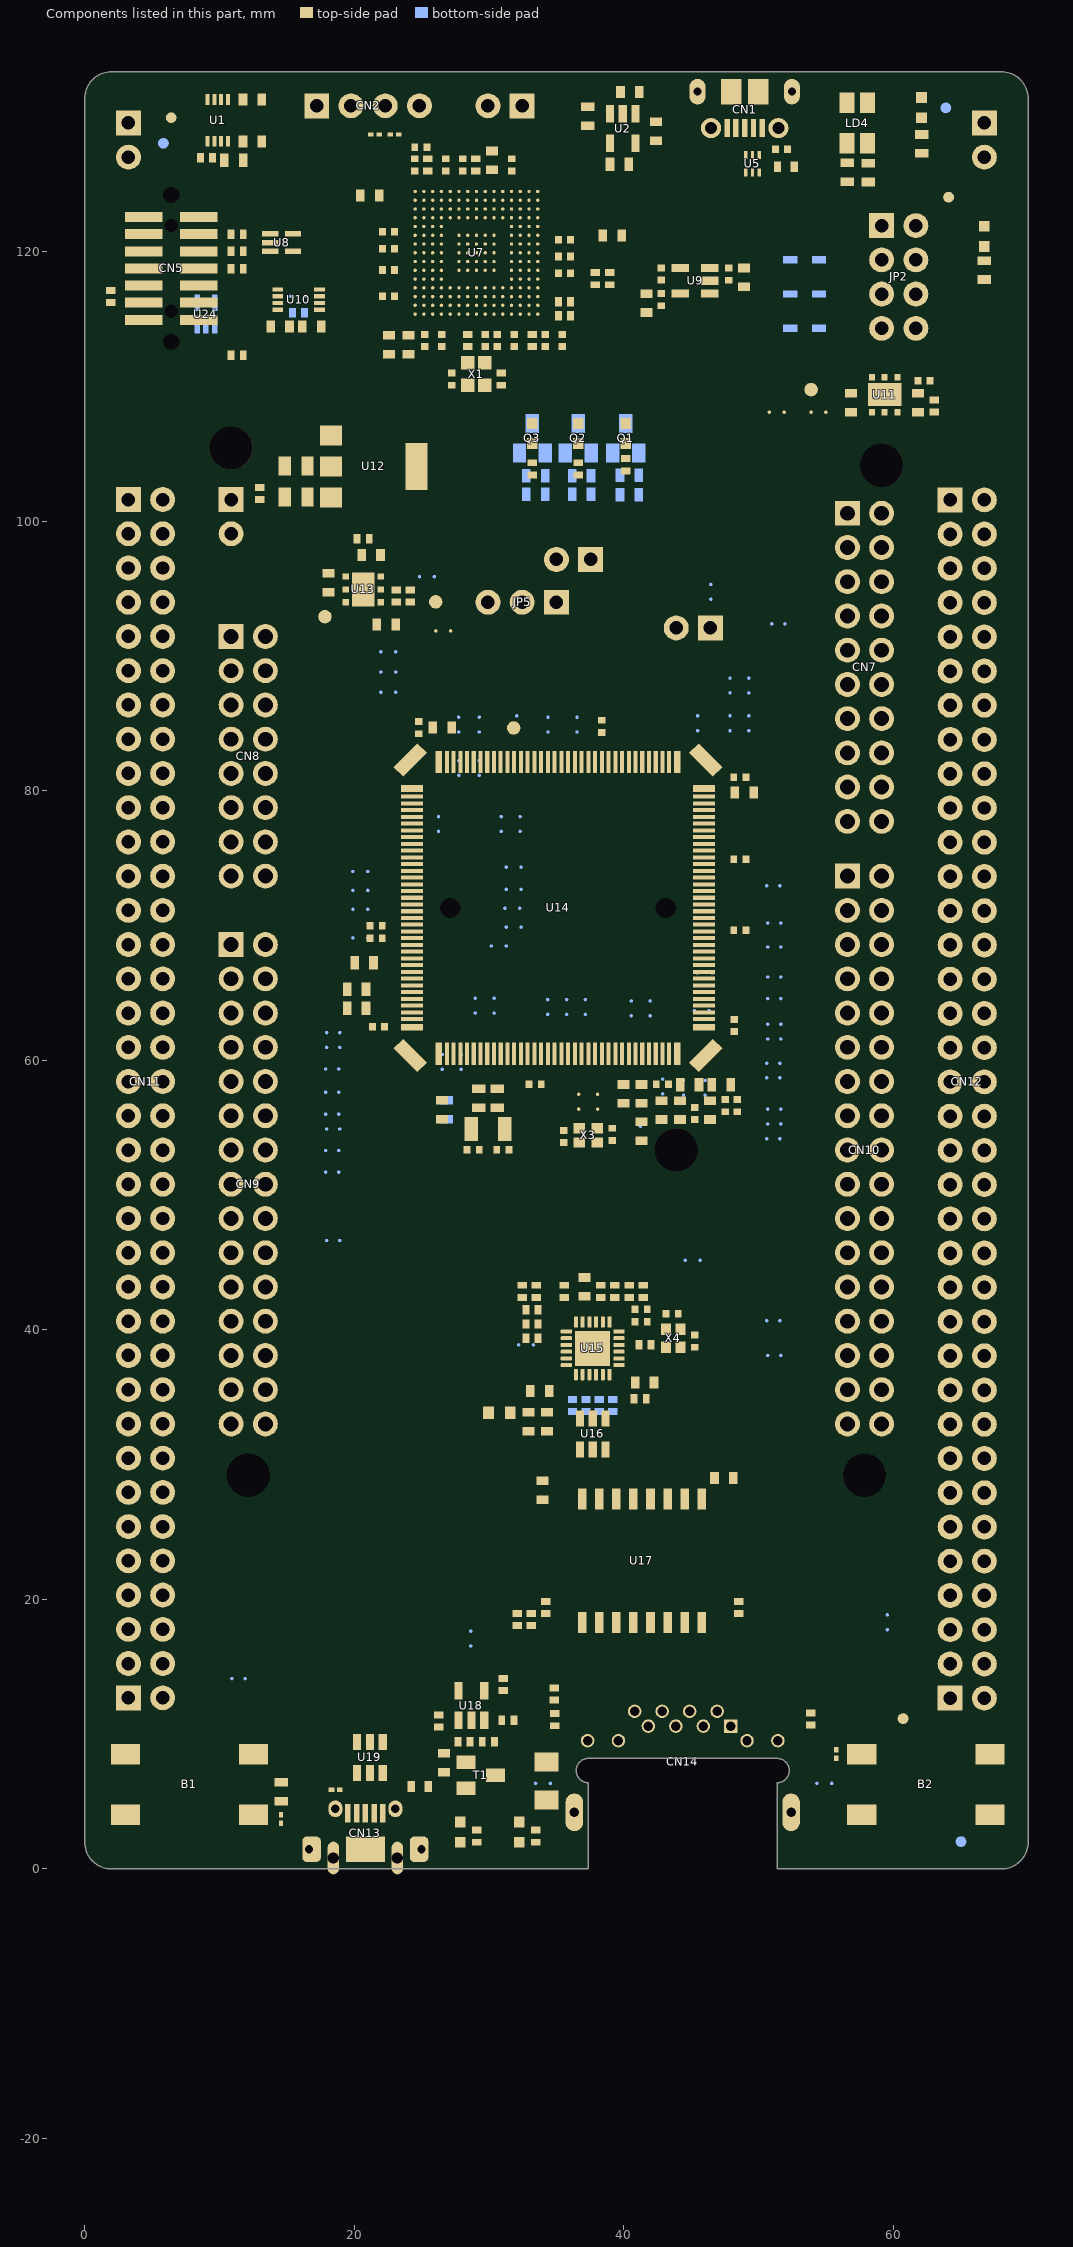
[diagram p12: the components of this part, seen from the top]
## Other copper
Top Layer:
  pour cut-out: 35.366,17.35 53.366,17.35 53.366,-0.121 35.366,-0.121
  pour cut-out: 29.6,20.55 36.366,20.55 36.366,0 29.6,0
  pour cut-out: 48.616,126.679 48.616,126.254 49.966,126.254 49.966,126.734 48.621,126.734 48.616,126.729
  pour cut-out: 35.366,-0.121 35.366,12.879 35.866,13.379 52.866,13.379 53.366,12.879 53.366,-0.121
  pour cut-out: 24.316,126.629 23.271,126.629 21.721,125.079 21.721,122.206 21.536,122.021 21.536,113.804 22.001,113.339 26.226,113.339 26.891,114.004 26.891,115.779 27.446,116.334 28.79,116.334 29.716,115.408 29.716,113.904 30.416,113.204 35.791,113.204 36.291,113.704 36.291,121.204 36.116,121.379 31.791,121.379 31.791,122.379 32.49,123.078 32.49,126.627
  text "1" at 67.368,104.084 h2 r90
Signal Layer 1:
  pour cut-out: 29.6,20.55 36.366,20.55 36.366,0 29.6,0
  pour cut-out: 35.366,17.35 53.366,17.35 53.366,-0.121 35.366,-0.121
  text "2" at 67.368,105.334 h2 r90
Signal Layer 2:
  pour cut-out: 35.366,17.35 53.366,17.35 53.366,-0.121 35.366,-0.121
  pour cut-out: 30.125,20.55 36.366,20.55 36.366,0 30.125,0
  pour cut-out: 35.366,-0.121 35.366,12.879 35.866,13.379 52.866,13.379 53.366,12.879 53.366,-0.121
  text "3" at 67.368,106.834 h2 r90
Signal Layer 3:
  pour cut-out: 35.325,17.421 53.325,17.421 53.325,-0.05 35.325,-0.05
  pour cut-out: 35.366,-0.121 35.366,12.879 35.866,13.379 52.866,13.379 53.366,12.879 53.366,-0.121
  text "4" at 67.368,109.084 h2 r90
Signal Layer 4:
  pour cut-out: 52.225,8.2 56.291,8.2 56.291,0 52.225,0
  pour cut-out: 35.366,17.35 53.366,17.35 53.366,-0.121 35.366,-0.121
  pour cut-out: 32.3,8.2 36.366,8.2 36.366,0 32.3,0
  text "5" at 67.368,110.584 h2 r90
Bottom Layer:
  pour cut-out: 56.459,0 53.525,0 53.525,20.225 56.459,20.225
  pour cut-out: 32.541,19.7 35.475,19.7 35.475,0 32.541,0
  pour cut-out: 32.575,17.366 32.575,20.3 56.325,20.3 56.325,17.366
  text "6" at 67.368,112.084 h2 r90
Multi-Layer:
  pour cut-out: 36.441,28.359 36.441,17.359 46.266,17.359 46.266,28.359
  pour cut-out: 65.75,103.85 67.75,103.85 67.75,112.35 65.75,112.35

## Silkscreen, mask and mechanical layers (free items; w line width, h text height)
Top Overlay:
  drawing of 1832 lines, arcs and shapes, not listed
  text "OVCR" at 60.186,132.098 h1.5
  text "COM" at 55.903,132.049 h1.5
  text "SWD" at 27.254,129.311 h1.5 r90
  text "STLK_RST" at 29.705,128.396 h0.91
  text "3V3" at 15.966,128.329 h1.5
  text "USB" at 45.027,127.236 h1.5
  text "STLK" at 15.394,127.064 h1.5
  text "GND" at 69.125,126.8 h1.5 r90
  text "GND" at 1.825,126.775 h1.5 r90
  text "PWR" at 44.861,126.086 h1.5
  text "ST-LINK V3" at 34.621,122.81 h1.5
  text "STLINK" at 52.72,121.407 h1.5
  text "VIN" at 55.15,118.795 h1.5
  text "5V" at 63.2,118.3 h1.5
  text "PWR" at 63.125,116.7 h1.5
  text "EXT" at 54.852,116.332 h1.5
  text "RX" at 0.706,114.299 h1.5
  text "TX" at 10.391,114.299 h1.5
  text "CHGR" at 53.48,113.769 h1.5
  text "MIPI10" at 4.326,111.224 h1.5
  text "3V3" at 52.749,110.764 h1.5
  text "5V_VIN" at 25.824,103.769 h1.5
  text "SCL" at 60.916,101.154 h1.2 r45
  text "User LEDs" at 34.039,101.13 h1.5
  text "D15" at 60.991,100.029 h1.2 r45
  text "VIN" at 17.315,99.842 h1.5
  text "3V3" at 36.435,98.66 h1.5
  text "SDA" at 60.916,98.379 h1.2 r45
  text "D14" at 60.991,97.229 h1.2 r45
  text "IDD" at 39.975,96.6 h1.5
  text "MCU_RST" at 7.776,96.466 h1.5
  text "+" at 62.291,95.379 h1.2 r45
  text "VREF" at 60.966,95.204 h1.2 r45
  text "I2S_A" at 54.017,94.409 h1.5 r90
  text "VDD" at 37.108,94.261 h1.5
  text "MCU" at 37.124,93.168 h1.5
  text "GND" at 60.891,92.779 h1.2 r45
  text "NC" at 7.741,92.154 h1.2 r315
  text "1V8" at 28.66,91.244 h1.5
  text "3V3" at 34.158,91.226 h1.5
  text "SCK" at 60.916,90.904 h1.2 r45
  text "VDD" at 28.393,90.104 h1.5
  text "VDD" at 33.891,90.086 h1.5
  text "D13" at 61.016,89.779 h1.2 r45
  text "IO" at 8.216,89.754 h1.2 r315
  text "RMII TXD1" at 41.862,89.533 h1.5
  text "REF" at 7.491,89.004 h1.2 r315
  text "MISO" at 60.966,88.079 h1.2 r45
  text "NRST" at 7.116,86.904 h1.2 r315
  text "D12" at 61.016,86.879 h1.2 r45
  text "I2S_B" at 54.719,85.921 h1.5 r90
  text "MOSI" at 60.991,85.329 h1.2 r45
  text "D11" at 60.966,84.079 h1.2 r45
  text "3V3" at 7.716,83.904 h1.2 r315
  text "SDMMC" at 16.676,82.753 h1.5 r90
  text "CS" at 60.891,82.629 h1.2 r45
  text "D10" at 60.966,81.479 h1.2 r45
  text "5V" at 7.841,81.354 h1.2 r315
  text "PWM" at 60.991,80.104 h1.2 r45
  text "GND" at 7.441,79.054 h1.2 r315
  text "D9" at 61.016,78.904 h1.2 r45
  text "SPI_B" at 54.151,78.837 h1.5 r90
  text "I/O" at 61.016,77.429 h1.2 r45
  text "GND" at 7.416,76.479 h1.2 r315
  text "D8" at 61.016,76.229 h1.2 r45
  text "IO" at 16.64,74.292 h1.5 r90
  text "I/O" at 61.041,74.204 h1.2 r45
  text "VIN" at 7.466,73.879 h1.2 r315
  text "AVDD" at 51.445,73.179 h1.5
  text "D7" at 61.041,72.954 h1.2 r45
  text "PWM" at 61.016,71.554 h1.2 r45
  text "AGND" at 51.342,70.602 h1.5
  text "D6" at 61.041,70.404 h1.2 r45
  text "A0" at 7.758,69.168 h1.2 r315
  text "PWM" at 61.041,69.029 h1.2 r45
  text "GND" at 52.309,68.223 h1.5
  text "D5" at 61.041,67.854 h1.2 r45
  text "A1" at 7.841,66.679 h1.2 r315
  text "I/O" at 61.016,66.429 h1.2 r45
  text "D4" at 61.041,65.204 h1.2 r45
  text "A2" at 7.866,64.129 h1.2 r315
  text "PWM" at 61.016,63.729 h1.2 r45
  text "D3" at 61.016,62.504 h1.2 r45
  text "A3" at 7.766,61.479 h1.2 r315
  text "USART" at 16.249,61.35 h1.5 r90
  text "I/O" at 61.016,61.129 h1.2 r45
  text "D2" at 61.041,59.954 h1.2 r45
  text "ADC_IN" at 54.018,59.134 h1.5 r90
  text "A4" at 7.816,59.004 h1.2 r315
  text "TX" at 60.992,58.483 h1.2 r45
  text "D1" at 60.991,57.254 h1.2 r45
  text "A5" at 7.766,56.429 h1.2 r315
  text "RX" at 61.016,55.729 h1.2 r45
  text "GND" at 14.885,55.395 h1.5
  text "D0" at 61.041,54.554 h1.2 r45
  text "COMP" at 8.392,50.222 h1.5 r90
  text "QSPI" at 53.866,49.124 h1.5 r90
  text "SAI_A" at 16.036,47.769 h1.5 r90
  text "I2C" at 8.534,44.676 h1.5 r90
  text "TIMER" at 62.301,41.166 h1.5 r90
  text "GND" at 7.366,41.129 h1.2 r315
  text "GND" at 52.309,40.207 h1.5
  text "SAI_B" at 16,37.601 h1.5 r90
  text "CAN" at 8.356,35.361 h1.5 r90
  text "TIMER" at 54.094,33.405 h1.5 r90
  text "IO" at 14.929,32.577 h1.5
  text "IO" at 8.202,32.51 h1.5
  text "MB1364C" at 51.85,18.252 h2
  text "Nucleo" at 8.393,16.043 h3.3
  text "GND" at 3.225,10.45 h1.5
  text "GND" at 64.25,10.45 h1.5
  text "USER" at 5.993,2.015 h1.5
  text "RESET" at 60.307,1.922 h1.5
  text "User" at 13.205,1.729 h1.5
  text "USB" at 13.229,0.491 h1.5
  text "OVCR" at 26.258,0.329 h1.5
  text "VBUS" at 31.537,0.337 h1.5
Bottom Overlay:
  lines w0.127: 23.525,19.75 48.525,19.75 48.525,28.75 23.525,28.75 23.525,19.75
  text "GND" at 68.45,126.875 h1.5 r270
  text "GND" at 0.625,126.775 h1.5 r270
  text "CN12" at 65.375,103.175 h1.5
  text "CN11" at 6.265,103.098 h1.5
  text "CN7" at 57.199,102.184 h1.5
  text "PC8" at 69.591,102.183 h1.2 r45
  text "PC11" at 9.533,101.167 h1.2
  text "PC10" at 1.766,100.979 h1.2 r315
  text "PC9" at 62.961,100.938 h1.2
  text "PC6" at 69.743,99.872 h1.2 r45
  text "PC12" at 1.791,98.579 h1.2 r315
  text "PD2" at 9.088,98.525 h1.2
  text "PB8" at 62.961,98.398 h1.2
  text "PC5" at 69.769,97.23 h1.2 r45
  text "3V3" at 1.866,96.504 h1.2 r315
  text "E5V" at 9.088,95.935 h1.2
  text "PB9" at 62.961,95.858 h1.2
  text "VDD" at 1.671,95.381 h1.2 r315
  text "U5V" at 69.667,94.563 h1.2 r45
  text "GND" at 9.088,93.445 h1.2
  text "BT0" at 1.595,93.318 h1.2 r315
  text "CN8" at 13.547,92.934 h1.5
  text "VREF+" at 62.69,92.664 h1.2 r315
  text "PD8" at 69.667,92.099 h1.2 r45
  text "NC" at 8.391,91.054 h1.2
  text "PF6" at 1.671,90.778 h1.2 r315
  text "GND" at 62.961,90.778 h1.2
  text "PA12" at 69.769,89.153 h1.2 r45
  text "+3V3" at 9.748,88.365 h1.2
  text "PA5" at 62.961,88.238 h1.2
  text "PF7" at 1.671,88.137 h1.2 r315
  text "PA11" at 69.489,86.41 h1.2 r45
  text "PA6" at 62.961,85.698 h1.2
  text "NRST" at 9.698,85.648 h1.2
  text "PA13" at 2.078,84.911 h1.2 r315
  text "PB12" at 69.591,83.895 h1.2 r45
  text "3V3" at 9.088,83.285 h1.2
  text "PA7" at 62.961,83.158 h1.2
  text "PA14" at 2.078,82.346 h1.2 r315
  text "PB11" at 69.642,81.38 h1.2 r45
  text "+5V" at 9.088,80.695 h1.2
  text "PB6" at 62.961,80.618 h1.2
  text "PA15" at 2.078,79.856 h1.2 r315
  text "GND" at 69.769,79.323 h1.2 r45
  text "GND" at 9.088,78.231 h1.2
  text "PC7" at 62.961,78.078 h1.2
  text "GND" at 1.671,78.053 h1.2 r315
  text "PB2" at 69.642,76.783 h1.2 r45
  text "GND" at 9.088,75.691 h1.2
  text "PA9" at 62.961,75.538 h1.2
  text "PB7" at 1.671,75.513 h1.2 r315
  text "CN10" at 59.578,75.041 h1.5
  text "PB1" at 69.489,74.065 h1.2 r45
  text "VIN" at 8.936,73.024 h1.2
  text "PA8" at 62.961,72.998 h1.2
  text "PC13" at 2.078,72.313 h1.2 r315
  text "PB15" at 69.591,71.373 h1.2 r45
  text "NC" at 8.466,70.704 h1.2
  text "PB10" at 62.961,70.458 h1.2
  text "CN9" at 13.647,69.951 h1.5
  text "PC14" at 2.078,69.696 h1.2 r315
  text "PB14" at 69.642,68.757 h1.2 r45
  text "PA0" at 9.088,68.096 h1.2
  text "PB4" at 62.961,67.918 h1.2
  text "PC15" at 1.9,67.36 h1.2 r315
  text "PB13" at 69.794,66.344 h1.2 r45
  text "PA1" at 8.783,65.505 h1.2
  text "PB5" at 62.961,65.378 h1.2
  text "OSCI" at 2.078,64.642 h1.2 r315
  text "AGND" at 69.86,64.007 h1.2 r45
  text "PA4" at 9.088,63.067 h1.2
  text "PB3" at 62.961,62.838 h1.2
  text "OSCO" at 2.078,62.102 h1.2 r315
  text "PC4" at 69.616,61.695 h1.2 r45
  text "PB0" at 9.088,60.425 h1.2
  text "PA10" at 62.961,60.298 h1.2
  text "VBAT" at 2.078,59.536 h1.2 r315
  text "NC" at 69.391,57.979 h1.2
  text "PC1" at 8.783,57.809 h1.2
  text "PA2" at 62.961,57.758 h1.2
  text "PC2" at 1.671,57.454 h1.2 r315
  text "NC" at 69.391,55.504 h1.2
  text "PC0" at 9.088,55.32 h1.2
  text "PA3" at 62.961,55.218 h1.2
  text "PC3" at 1.671,54.863 h1.2 r315
  text "PE8" at 69.616,53.847 h1.2 r45
  text "PD3" at 9.088,52.755 h1.2
  text "GND" at 62.961,52.678 h1.2
  text "PD4" at 1.595,52.628 h1.2 r315
  text "PF10" at 69.87,51.332 h1.2 r45
  text "NC" at 8.491,50.379 h1.2
  text "PD13" at 62.961,50.138 h1.2
  text "PD5" at 1.57,50.113 h1.2 r315
  text "PE7" at 69.667,48.716 h1.2 r45
  text "NC" at 8.516,47.904 h1.2
  text "PD6" at 1.57,47.598 h1.2 r315
  text "PD12" at 62.961,47.598 h1.2
  text "PD14" at 69.819,46.176 h1.2 r45
  text "PE2" at 9.088,45.16 h1.2
  text "PD7" at 1.519,45.135 h1.2 r315
  text "PD11" at 62.961,45.058 h1.2
  text "PD15" at 69.667,43.509 h1.2 r45
  text "PE4" at 9.088,42.747 h1.2
  text "PE3" at 1.544,42.544 h1.2 r315
  text "PE10" at 62.961,42.518 h1.2
  text "PF14" at 69.718,40.994 h1.2 r45
  text "GND" at 1.595,40.105 h1.2 r315
  text "PE12" at 62.961,39.978 h1.2
  text "PE5" at 9.088,39.928 h1.2
  text "PE9" at 69.667,38.556 h1.2 r45
  text "NC" at 1.966,37.729 h1.2
  text "NC" at 8.566,37.679 h1.2
  text "PE14" at 62.961,37.438 h1.2
  text "GND" at 69.667,36.041 h1.2 r45
  text "NC" at 2.016,35.179 h1.2
  text "PF8" at 9.088,35 h1.2
  text "PE15" at 62.961,34.898 h1.2
  text "PE11" at 69.794,33.578 h1.2 r45
  text "PF9" at 9.088,32.46 h1.2
  text "PD1" at 1.671,32.384 h1.2 r315
  text "PE13" at 62.961,32.358 h1.2
  text "NC" at 8.591,30.129 h1.2
  text "NC" at 62.941,30.054 h1.2
  text "NC" at 69.441,30.054 h1.2
  text "PD0" at 1.671,29.793 h1.2 r315
  text "PF15" at 69.819,28.32 h1.2 r45
  text "NC" at 1.916,27.554 h1.2
  text "GND" at 9.191,27.504 h1.2
  text "NC" at 62.991,27.479 h1.2
  text "PF11" at 69.642,25.704 h1.2 r45
  text "PE6" at 9.088,24.815 h1.2
  text "PG14" at 62.961,24.738 h1.2
  text "PE1" at 1.595,24.688 h1.2 r315
  text "PE0" at 69.667,23.468 h1.2 r45
  text "PG15" at 9.725,22.475 h1.2
  text "GND" at 62.961,22.198 h1.2
  text "PG9" at 1.62,22.097 h1.2 r315
  text "PG8" at 69.616,20.827 h1.2 r45
  text "PG10" at 9.829,19.887 h1.2
  text "PD10" at 62.961,19.658 h1.2
  text "PG12" at 2.078,18.871 h1.2 r315
  text "PG5" at 69.616,18.102 h1.2 r45
  text "MB1364C" at 41.475,17.675 h2.5
  text "PG7" at 62.975,17.4 h1.2
  text "NC" at 2.016,17.354 h1.2
  text "PG13" at 9.829,17.322 h1.2
  text "PG6" at 69.743,15.975 h1.2 r45
  text "PG11" at 9.829,14.909 h1.2
  text "PG4" at 62.841,14.754 h1.2
  text "PD9" at 1.671,14.477 h1.2 r315
  text "GND" at 5.975,10.075 h1.5
  text "GND" at 67,10.075 h1.5
Top Solder:
  region: 67.75,103.85 67.75,112.35 65.75,112.35 65.75,103.85
Bottom Solder:
  region: 67.75,103.85 67.75,112.35 65.75,112.35 65.75,103.85
M1-Board Shape:
  lines w0.1: 51.369,6.4 ccw(c51.369,7.3) 52.269,7.3 ; 51.369,6.4 ccw(c51.369,6.4) 51.369,6.4 ; 51.369,6.4 51.369,0 68,0 ; 52.269,7.3 ccw(c51.369,7.3) 51.369,8.2 37.369,8.2 ccw(c37.369,7.3) 36.469,7.3 ccw(c37.369,7.3) 37.369,6.4 37.369,0 2,0 cw(c2,2) 0,2 0,131.34 cw(c2,131.34) 2,133.34 68,133.34 cw(c68,131.34) 70,131.34 70,2 cw(c68,2) 68,0 ; 52.269,7.3 52.269,7.3 ; 68,0 68,0
Drill Drawing:
  drawing of 561 lines, arcs and shapes, not listed
  text "THE COMPONENTS WITH PLATED THROUGH HOLE (PTH) MAY BE WELDED (CABLED) IN \"PIN-IN-PASTE\" MODE (IF NECESSARY)" at 1.025,183.45 h3.5
  text "PCB SPECIFICATIONS :" at 2.061,176.279 h3
  text "PCB : TYPE 3" at 150.473,176.047 h3
  text "A.   MATERIAL :" at 2.061,172.279 h3
  text "FR-4" at 40.561,172.279 h3
  text "TG-170" at 57.061,172.279 h3
  text "X  TG-150" at 75.311,172.279 h3
  text "TG-140" at 91.311,172.279 h3
  text "ASPECT-RATIO, AXE Z :" at 150.473,170.547 h3
  text "B.   MATERIAL FAMILY :" at 2.061,169.279 h3
  text "N/A" at 40.561,169.279 h3
  text "C.   SOLDERMASK COLOR :" at 2.061,166.279 h3
  text "GREEN" at 40.561,166.279 h3
  text "X  WHITE" at 57.061,166.279 h3
  text "RED" at 75.311,166.279 h3
  text "BLACK" at 91.311,166.279 h3
  text "6:1 to 8:1 / LEVEL \"B\"" at 150.491,163.799 h3
  text "D.   SILKSCREEN COLOR :" at 2.061,163.279 h3
  text "WHITE" at 40.561,163.279 h3
  text "YELLOW" at 57.061,163.279 h3
  text "BLACK" at 75.311,163.279 h3
  text "X  Blue ink PANTONE 2955" at 91.311,163.279 h3
  text "E.   SURFACE FINISH :" at 2.061,160.279 h3
  text "X  ENIG" at 40.561,160.279 h3
  text "IMMERSION SILVER" at 57.061,160.279 h3
  text "IMMERSION TIN" at 91.311,160.279 h3
  text "MINIMUM PARAMETERS" at 150.518,158.198 h3
  text "HASL" at 40.561,157.279 h3
  text "HASL (PB-FREE)" at 57.061,157.279 h3
  text "GOLDEN FINGER" at 91.311,157.279 h3
  text "F.   IMPEDANCE CONTROL :" at 2.061,154.279 h3
  text "NO" at 40.561,154.279 h3
  text "X  YES  (SEE IMPEDANCE TABLE FOR DETAIL INFORMATION)" at 57.061,154.279 h3
  text "DEFAULT" at 150.518,152.698 h3
  text "G.   THROUGH VIA :" at 2.061,151.279 h3
  text "PLUG THE VIAS WHICH ARE COVERED WITH SOLDERMASK ONE OR TWO SIDE." at 40.561,151.279 h3
  text "PLUG MATERIAL :" at 40.561,148.279 h3
  text "X  SOLDERMASK" at 66.061,148.279 h3
  text "NON-CONDUCTIVE EPOXY." at 91.311,148.279 h3
  text "TRACKS : 0.120mm           / GAPS : 0.120mm" at 150.518,146.948 h3
  text "H.   STACK-UP :" at 2.061,145.279 h3
  text "SEE LAYER STACK-UP SEQUENCE FOR OVERALL THICKNESS." at 40.561,145.279 h3
  text "Layer" at 79.741,134.779 h2
  text "Name" at 88.115,134.779 h2
  text "Material" at 104.312,134.779 h2
  text "Thickness" at 118.866,134.779 h2
  text "Constant" at 130.821,134.779 h2
  text "Board Layer Stack" at 141.885,134.779 h2
  text "IMPEDANCE TABLE    RMII" at 163.739,134.594 h3
  text "1" at 79.741,130.779 h2
  text "Top Overlay" at 88.115,130.779 h2
  text "LAYER" at 167.989,129.594 h3
  text "TRACE" at 184.239,129.594 h3
  text "SPACING" at 194.739,129.594 h3
  text "IMPEDANCE" at 208.239,129.594 h3
  text "IMPEDANCE" at 225.239,129.594 h3
  text "TOL." at 243.989,129.594 h3
  text "(mm)" at 198.064,127.119 h2.5
  text "(mm)" at 186.239,127.069 h2.5
  text "(Single ended)" at 208.739,126.844 h2.5
  text "(Differential)" at 226.489,126.844 h2.5
  text "2" at 79.741,126.779 h2
  text "Top Solder" at 88.115,126.779 h2
  text "Solder Resist" at 104.312,126.779 h2
  text "0,015mm" at 118.866,126.779 h2
  text "3,5" at 130.821,126.779 h2
  text "+/- 15%" at 243.044,123.204 h3
  text "0.127" at 185.214,123.119 h3
  text "TOP/BOTTOM" at 164.219,123.079 h3
  text "n/a" at 197.239,123.094 h3
  text "50 ohm" at 211.594,123.029 h3
  text "n/a" at 231.144,122.979 h3
  text "3" at 79.741,122.779 h2
  text "Top Layer" at 88.115,122.779 h2
  text "Copper" at 104.312,122.779 h2
  text "0,042mm" at 118.866,122.779 h2
  text "+/- 15%" at 243.049,119.689 h3
  text "0.102" at 185.219,119.604 h3
  text "n/a" at 197.244,119.579 h3
  text "LAYER 3" at 166.164,119.544 h3
  text "50 ohm" at 211.599,119.514 h3
  text "n/a" at 231.149,119.464 h3
  text "4" at 79.741,118.779 h2
  text "Dielectric 1" at 88.115,118.779 h2
  text "FR-4" at 104.312,118.779 h2
  text "0,099mm" at 118.866,118.779 h2
  text "4,2" at 130.821,118.779 h2
  text "5" at 79.741,114.779 h2
  text "Signal Layer 1" at 88.115,114.779 h2
  text "Copper" at 104.312,114.779 h2
  text "0,035mm" at 118.866,114.779 h2
  text "IMPEDANCE TABLE    RD / RX / TD / TX" at 163.739,114.274 h3
  text "6" at 79.741,110.779 h2
  text "Dielectric 2" at 88.115,110.779 h2
  text "0,102mm" at 118.866,110.779 h2
  text "4,2" at 130.821,110.779 h2
  text "LAYER" at 167.989,109.655 h3
  text "TRACE" at 184.239,109.655 h3
  text "SPACING" at 194.739,109.655 h3
  text "IMPEDANCE" at 208.239,109.655 h3
  text "IMPEDANCE" at 225.239,109.655 h3
  text "TOL." at 243.989,109.655 h3
  text "(mm)" at 198.064,107.18 h2.5
  text "(mm)" at 186.239,107.13 h2.5
  text "(Single ended)" at 208.739,106.905 h2.5
  text "(Differential)" at 226.489,106.905 h2.5
  text "7" at 79.741,106.779 h2
  text "Signal Layer 2" at 88.115,106.779 h2
  text "Copper" at 104.312,106.779 h2
  text "0,035mm" at 118.866,106.779 h2
  text "+/- 15%" at 243.044,103.265 h3
  text "0.130" at 185.214,103.18 h3
  text "TOP/BOTTOM" at 164.219,103.14 h3
  text "0.251" at 197.239,103.155 h3
  text "n/a" at 211.594,103.09 h3
  text "100 ohm" at 227.68,103.041 h3
  text "8" at 79.741,102.779 h2
  text "Dielectric 3" at 88.115,102.779 h2
  text "0,946mm" at 118.866,102.779 h2
  text "4,2" at 130.821,102.779 h2
  text "+/- 15%" at 243.049,99.75 h3
  text "0.104" at 185.219,99.665 h3
  text "0.277" at 197.244,99.64 h3
  text "LAYER 3" at 166.164,99.605 h3
  text "100 ohm" at 227.68,99.612 h3
  text "n/a" at 211.599,99.575 h3
  text "9" at 79.741,98.779 h2
  text "Signal Layer 3" at 88.115,98.779 h2
  text "Copper" at 104.312,98.779 h2
  text "0,035mm" at 118.866,98.779 h2
  text "IMPEDANCE TABLE   USB FS, USB HS USER, USB HS STLINK" at 163.739,94.843 h3
  text "10" at 79.741,94.779 h2
  text "Dielectric 4" at 88.115,94.779 h2
  text "0,102mm" at 118.866,94.779 h2
  text "4,2" at 130.821,94.779 h2
  text "11" at 79.741,90.779 h2
  text "Signal Layer 4" at 88.115,90.779 h2
  text "Copper" at 104.312,90.779 h2
  text "0,035mm" at 118.866,90.779 h2
  text "LAYER" at 167.989,89.843 h3
  text "TRACE" at 184.239,89.843 h3
  text "SPACING" at 194.739,89.843 h3
  text "IMPEDANCE" at 208.239,89.843 h3
  text "IMPEDANCE" at 225.239,89.843 h3
  text "TOL." at 243.989,89.843 h3
  text "(mm)" at 198.064,87.368 h2.5
  text "(mm)" at 186.239,87.318 h2.5
  text "(Single ended)" at 208.739,87.093 h2.5
  text "(Differential)" at 226.489,87.093 h2.5
  text "12" at 79.741,86.779 h2
  text "Dielectric 5" at 88.115,86.779 h2
  text "0,099mm" at 118.866,86.779 h2
  text "4,2" at 130.821,86.779 h2
  text "+/- 15%" at 243.044,83.453 h3
  text "0.155" at 185.214,83.368 h3
  text "TOP/BOTTOM" at 164.219,83.328 h3
  text "0.226" at 197.239,83.343 h3
  text "n/a" at 211.594,83.278 h3
  text "90 ohm" at 227.68,83.102 h3
  text "13" at 79.741,82.779 h2
  text "Bottom Layer" at 88.115,82.779 h2
  text "Copper" at 104.312,82.779 h2
  text "0,042mm" at 118.866,82.779 h2
  text "+/- 15%" at 243.049,79.938 h3
  text "0.130" at 185.219,79.853 h3
  text "0.251" at 197.244,79.828 h3
  text "LAYER 3" at 166.164,79.793 h3
  text "90 ohm" at 227.68,79.8 h3
  text "n/a" at 211.599,79.763 h3
  text "14" at 79.741,78.779 h2
  text "Bottom Solder" at 88.115,78.779 h2
  text "Solder Resist" at 104.312,78.779 h2
  text "0,015mm" at 118.866,78.779 h2
  text "3,5" at 130.821,78.779 h2
  text "15" at 79.741,74.779 h2
  text "Bottom Overlay" at 88.115,74.779 h2
  text "Symbol" at 80.452,67.033 h2.4
  text "Count" at 89.851,67.033 h2.4
  text "Hole Size" at 100.625,67.033 h2.4
  text "Plated" at 119.896,67.033 h2.4
  text "Hole Type" at 128.147,67.033 h2.4
  text "Drill Layer Pair" at 140.158,67.033 h2.4
  text "Hole Length" at 162.939,67.033 h2.4
  text "Routed Path Length" at 181.238,67.033 h2.4
  text "2042" at 89.851,62.89 h2
  text "0,200mm (7,87mil)" at 100.625,62.89 h2
  text "PTH" at 119.896,62.89 h2
  text "Round" at 128.147,62.89 h2
  text "Top Layer - Bottom Layer" at 140.158,62.89 h2
  text "-" at 162.939,62.89 h2
  text "-" at 181.238,62.89 h2
  text "9" at 89.851,58.747 h2
  text "0,300mm (11,81mil)" at 100.625,58.747 h2
  text "PTH" at 119.896,58.747 h2
  text "Round" at 128.147,58.747 h2
  text "Top Layer - Bottom Layer" at 140.158,58.747 h2
  text "-" at 162.939,58.747 h2
  text "-" at 181.238,58.747 h2
  text "4" at 89.851,54.604 h2
  text "0,600mm (23,62mil)" at 100.625,54.604 h2
  text "PTH" at 119.896,54.604 h2
  text "Slot" at 128.147,54.604 h2
  text "Top Layer - Bottom Layer" at 140.158,54.604 h2
  text "1,300mm (51,18mil)" at 162.939,54.604 h2
  text "0,700mm (27,56mil)" at 181.238,54.604 h2
  text "2" at 89.851,50.461 h2
  text "0,650mm (25,59mil)" at 100.625,50.461 h2
  text "PTH" at 119.896,50.461 h2
  text "Slot" at 128.147,50.461 h2
  text "Top Layer - Bottom Layer" at 140.158,50.461 h2
  text "0,850mm (33,47mil)" at 162.939,50.461 h2
  text "0,200mm (7,88mil)" at 181.238,50.461 h2
  text "12" at 89.851,46.318 h2
  text "0,700mm (27,56mil)" at 100.625,46.318 h2
  text "PTH" at 119.896,46.318 h2
  text "Round" at 128.147,46.318 h2
  text "Top Layer - Bottom Layer" at 140.158,46.318 h2
  text "-" at 162.939,46.318 h2
  text "-" at 181.238,46.318 h2
  text "2" at 89.851,42.175 h2
  text "0,700mm (27,56mil)" at 100.625,42.175 h2
  text "PTH" at 119.896,42.175 h2
  text "Slot" at 128.147,42.175 h2
  text "Top Layer - Bottom Layer" at 140.158,42.175 h2
  text "2,200mm (86,61mil)" at 162.939,42.175 h2
  text "1,500mm (59,06mil)" at 181.238,42.175 h2
  text "2" at 89.851,38.032 h2
  text "0,850mm (33,47mil)" at 100.625,38.032 h2
  text "NPTH" at 119.896,38.032 h2
  text "Slot" at 128.147,38.032 h2
  text "Top Layer - Bottom Layer" at 140.158,38.032 h2
  text "2,425mm (95,47mil)" at 162.939,38.032 h2
  text "1,575mm (62,01mil)" at 181.238,38.032 h2
  text "2" at 89.851,33.889 h2
  text "0,900mm (35,43mil)" at 100.625,33.889 h2
  text "PTH" at 119.896,33.889 h2
  text "Round" at 128.147,33.889 h2
  text "Top Layer - Bottom Layer" at 140.158,33.889 h2
  text "-" at 162.939,33.889 h2
  text "-" at 181.238,33.889 h2
  text "2" at 89.851,29.746 h2
  text "0,970mm (38,19mil)" at 100.625,29.746 h2
  text "NPTH" at 119.896,29.746 h2
  text "Round" at 128.147,29.746 h2
  text "Top Layer - Bottom Layer" at 140.158,29.746 h2
  text "-" at 162.939,29.746 h2
  text "-" at 181.238,29.746 h2
  text "B" at 79.664,29.492 h1.84
  text "171" at 89.851,25.603 h2
  text "1,000mm (39,37mil)" at 100.625,25.603 h2
  text "PTH" at 119.896,25.603 h2
  text "Round" at 128.147,25.603 h2
  text "Top Layer - Bottom Layer" at 140.158,25.603 h2
  text "-" at 162.939,25.603 h2
  text "-" at 181.238,25.603 h2
  text "100" at 89.851,21.46 h2
  text "1,100mm (43,31mil)" at 100.625,21.46 h2
  text "PTH" at 119.896,21.46 h2
  text "Round" at 128.147,21.46 h2
  text "Top Layer - Bottom Layer" at 140.158,21.46 h2
  text "-" at 162.939,21.46 h2
  text "-" at 181.238,21.46 h2
  text "2" at 89.851,17.316 h2
  text "1,190mm (46,85mil)" at 100.625,17.316 h2
  text "NPTH" at 119.896,17.316 h2
  text "Round" at 128.147,17.316 h2
  text "Top Layer - Bottom Layer" at 140.158,17.316 h2
  text "-" at 162.939,17.316 h2
  text "-" at 181.238,17.316 h2
  text "C" at 79.664,17.063 h1.84
  text "2" at 89.851,13.173 h2
  text "1,500mm (59,06mil)" at 100.625,13.173 h2
  text "NPTH" at 119.896,13.173 h2
  text "Round" at 128.147,13.173 h2
  text "Top Layer - Bottom Layer" at 140.158,13.173 h2
  text "-" at 162.939,13.173 h2
  text "-" at 181.238,13.173 h2
  text "5" at 89.851,9.03 h2
  text "3,200mm (125,98mil)" at 100.625,9.03 h2
  text "NPTH" at 119.896,9.03 h2
  text "Round" at 128.147,9.03 h2
  text "Top Layer - Bottom Layer" at 140.158,9.03 h2
  text "-" at 162.939,9.03 h2
  text "-" at 181.238,9.03 h2
  text "2357 Total" at 89.851,4.887 h2
  text "Slot definitions :" at 80.452,1.987 h2
  text "Routed Path Length" at 94.105,1.987 h2
  text "= Calculated from tool start centre position to tool end centre position." at 111.018,1.987 h2
  text "Hole Length" at 94.105,0.33 h2
  text "= Routed Path Length + Tool Size = Slot length as defined in the PCB layout" at 104.739,0.33 h2

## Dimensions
2,0 to 2,133.34 on M2-Board Dimensions
0,131.34 to 70,131.34 on M2-Board Dimensions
